VERSION 5.8 ;
BUSBITCHARS "[]" ;
DIVIDERCHAR "/" ;
UNITS
    DATABASE MICRONS 1000 ;
END UNITS

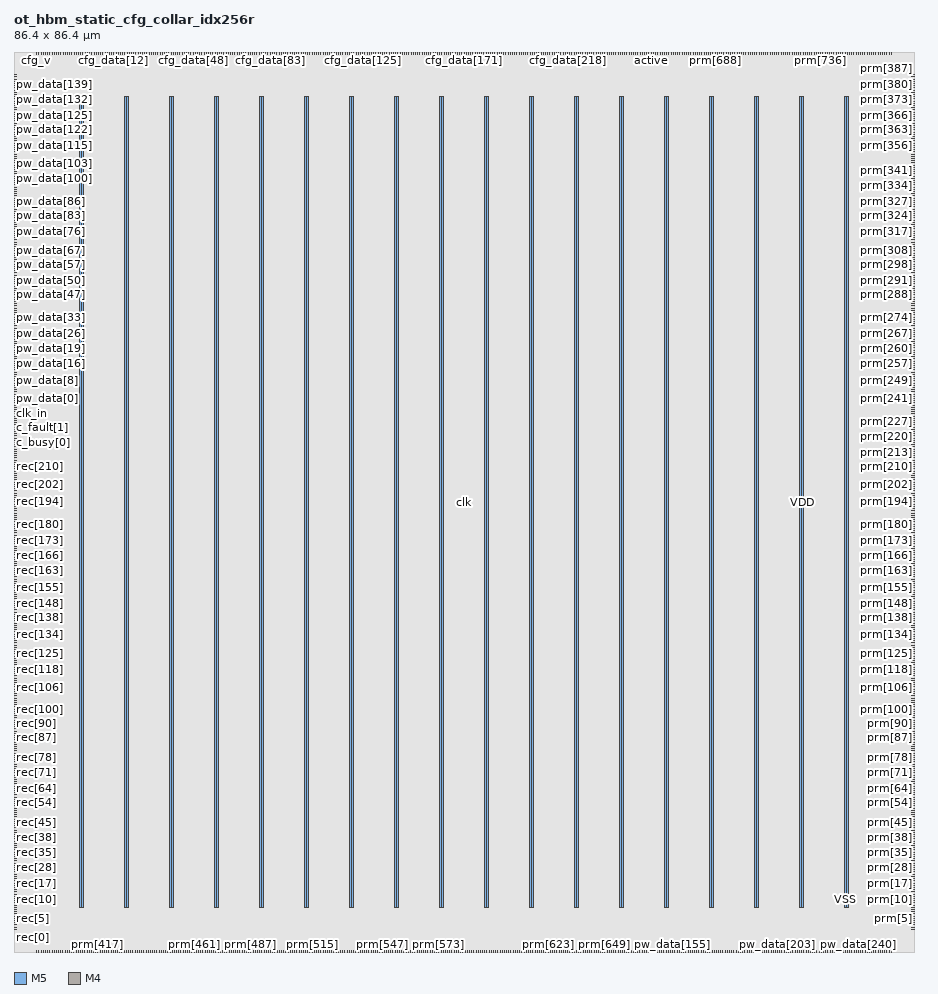
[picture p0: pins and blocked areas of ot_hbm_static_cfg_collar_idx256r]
MACRO ot_hbm_static_cfg_collar_idx256r
  FOREIGN ot_hbm_static_cfg_collar_idx256r 0 0 ;
  CLASS BLOCK ;
  SIZE 86.4 BY 86.4 ;
  PIN active
    DIRECTION OUTPUT ;
    USE SIGNAL ;
    PORT
      LAYER M5 ;
        RECT  61.164 86.208 61.188 86.4 ;
    END
  END active
  PIN c_busy[0]
    DIRECTION INPUT ;
    USE SIGNAL ;
    PORT
      LAYER M4 ;
        RECT  0 48.876 0.192 48.9 ;
    END
  END c_busy[0]
  PIN c_busy[1]
    DIRECTION INPUT ;
    USE SIGNAL ;
    PORT
      LAYER M4 ;
        RECT  0 49.116 0.192 49.14 ;
    END
  END c_busy[1]
  PIN c_done
    DIRECTION INPUT ;
    USE SIGNAL ;
    PORT
      LAYER M5 ;
        RECT  61.788 86.208 61.812 86.4 ;
    END
  END c_done
  PIN c_done__W
    DIRECTION INPUT ;
    USE SIGNAL ;
    PORT
      LAYER M4 ;
        RECT  0 52.908 0.192 52.932 ;
    END
  END c_done__W
  PIN c_fault[0]
    DIRECTION INPUT ;
    USE SIGNAL ;
    PORT
      LAYER M4 ;
        RECT  0 49.308 0.192 49.332 ;
    END
  END c_fault[0]
  PIN c_fault[1]
    DIRECTION INPUT ;
    USE SIGNAL ;
    PORT
      LAYER M4 ;
        RECT  0 49.548 0.192 49.572 ;
    END
  END c_fault[1]
  PIN c_fault[2]
    DIRECTION INPUT ;
    USE SIGNAL ;
    PORT
      LAYER M4 ;
        RECT  0 49.74 0.192 49.764 ;
    END
  END c_fault[2]
  PIN c_fault[3]
    DIRECTION INPUT ;
    USE SIGNAL ;
    PORT
      LAYER M4 ;
        RECT  0 49.932 0.192 49.956 ;
    END
  END c_fault[3]
  PIN c_fault[4]
    DIRECTION INPUT ;
    USE SIGNAL ;
    PORT
      LAYER M4 ;
        RECT  0 50.172 0.192 50.196 ;
    END
  END c_fault[4]
  PIN cfg_addr[0]
    DIRECTION INPUT ;
    USE SIGNAL ;
    PORT
      LAYER M5 ;
        RECT  4.476 86.208 4.5 86.4 ;
    END
  END cfg_addr[0]
  PIN cfg_addr[10]
    DIRECTION INPUT ;
    USE SIGNAL ;
    PORT
      LAYER M5 ;
        RECT  6.588 86.208 6.612 86.4 ;
    END
  END cfg_addr[10]
  PIN cfg_addr[11]
    DIRECTION INPUT ;
    USE SIGNAL ;
    PORT
      LAYER M5 ;
        RECT  6.828 86.208 6.852 86.4 ;
    END
  END cfg_addr[11]
  PIN cfg_addr[1]
    DIRECTION INPUT ;
    USE SIGNAL ;
    PORT
      LAYER M5 ;
        RECT  4.716 86.208 4.74 86.4 ;
    END
  END cfg_addr[1]
  PIN cfg_addr[2]
    DIRECTION INPUT ;
    USE SIGNAL ;
    PORT
      LAYER M5 ;
        RECT  4.908 86.208 4.932 86.4 ;
    END
  END cfg_addr[2]
  PIN cfg_addr[3]
    DIRECTION INPUT ;
    USE SIGNAL ;
    PORT
      LAYER M5 ;
        RECT  5.148 86.208 5.172 86.4 ;
    END
  END cfg_addr[3]
  PIN cfg_addr[4]
    DIRECTION INPUT ;
    USE SIGNAL ;
    PORT
      LAYER M5 ;
        RECT  5.34 86.208 5.364 86.4 ;
    END
  END cfg_addr[4]
  PIN cfg_addr[5]
    DIRECTION INPUT ;
    USE SIGNAL ;
    PORT
      LAYER M5 ;
        RECT  5.532 86.208 5.556 86.4 ;
    END
  END cfg_addr[5]
  PIN cfg_addr[6]
    DIRECTION INPUT ;
    USE SIGNAL ;
    PORT
      LAYER M5 ;
        RECT  5.772 86.208 5.796 86.4 ;
    END
  END cfg_addr[6]
  PIN cfg_addr[7]
    DIRECTION INPUT ;
    USE SIGNAL ;
    PORT
      LAYER M5 ;
        RECT  5.964 86.208 5.988 86.4 ;
    END
  END cfg_addr[7]
  PIN cfg_addr[8]
    DIRECTION INPUT ;
    USE SIGNAL ;
    PORT
      LAYER M5 ;
        RECT  6.204 86.208 6.228 86.4 ;
    END
  END cfg_addr[8]
  PIN cfg_addr[9]
    DIRECTION INPUT ;
    USE SIGNAL ;
    PORT
      LAYER M5 ;
        RECT  6.396 86.208 6.42 86.4 ;
    END
  END cfg_addr[9]
  PIN cfg_data[0]
    DIRECTION INPUT ;
    USE SIGNAL ;
    PORT
      LAYER M5 ;
        RECT  7.02 86.208 7.044 86.4 ;
    END
  END cfg_data[0]
  PIN cfg_data[100]
    DIRECTION INPUT ;
    USE SIGNAL ;
    PORT
      LAYER M5 ;
        RECT  28.188 86.208 28.212 86.4 ;
    END
  END cfg_data[100]
  PIN cfg_data[101]
    DIRECTION INPUT ;
    USE SIGNAL ;
    PORT
      LAYER M5 ;
        RECT  28.38 86.208 28.404 86.4 ;
    END
  END cfg_data[101]
  PIN cfg_data[102]
    DIRECTION INPUT ;
    USE SIGNAL ;
    PORT
      LAYER M5 ;
        RECT  28.62 86.208 28.644 86.4 ;
    END
  END cfg_data[102]
  PIN cfg_data[103]
    DIRECTION INPUT ;
    USE SIGNAL ;
    PORT
      LAYER M5 ;
        RECT  28.812 86.208 28.836 86.4 ;
    END
  END cfg_data[103]
  PIN cfg_data[104]
    DIRECTION INPUT ;
    USE SIGNAL ;
    PORT
      LAYER M5 ;
        RECT  29.004 86.208 29.028 86.4 ;
    END
  END cfg_data[104]
  PIN cfg_data[105]
    DIRECTION INPUT ;
    USE SIGNAL ;
    PORT
      LAYER M5 ;
        RECT  29.244 86.208 29.268 86.4 ;
    END
  END cfg_data[105]
  PIN cfg_data[106]
    DIRECTION INPUT ;
    USE SIGNAL ;
    PORT
      LAYER M5 ;
        RECT  29.436 86.208 29.46 86.4 ;
    END
  END cfg_data[106]
  PIN cfg_data[107]
    DIRECTION INPUT ;
    USE SIGNAL ;
    PORT
      LAYER M5 ;
        RECT  29.676 86.208 29.7 86.4 ;
    END
  END cfg_data[107]
  PIN cfg_data[108]
    DIRECTION INPUT ;
    USE SIGNAL ;
    PORT
      LAYER M5 ;
        RECT  29.868 86.208 29.892 86.4 ;
    END
  END cfg_data[108]
  PIN cfg_data[109]
    DIRECTION INPUT ;
    USE SIGNAL ;
    PORT
      LAYER M5 ;
        RECT  30.06 86.208 30.084 86.4 ;
    END
  END cfg_data[109]
  PIN cfg_data[10]
    DIRECTION INPUT ;
    USE SIGNAL ;
    PORT
      LAYER M5 ;
        RECT  9.132 86.208 9.156 86.4 ;
    END
  END cfg_data[10]
  PIN cfg_data[110]
    DIRECTION INPUT ;
    USE SIGNAL ;
    PORT
      LAYER M5 ;
        RECT  30.3 86.208 30.324 86.4 ;
    END
  END cfg_data[110]
  PIN cfg_data[111]
    DIRECTION INPUT ;
    USE SIGNAL ;
    PORT
      LAYER M5 ;
        RECT  30.492 86.208 30.516 86.4 ;
    END
  END cfg_data[111]
  PIN cfg_data[112]
    DIRECTION INPUT ;
    USE SIGNAL ;
    PORT
      LAYER M5 ;
        RECT  30.732 86.208 30.756 86.4 ;
    END
  END cfg_data[112]
  PIN cfg_data[113]
    DIRECTION INPUT ;
    USE SIGNAL ;
    PORT
      LAYER M5 ;
        RECT  30.924 86.208 30.948 86.4 ;
    END
  END cfg_data[113]
  PIN cfg_data[114]
    DIRECTION INPUT ;
    USE SIGNAL ;
    PORT
      LAYER M5 ;
        RECT  31.116 86.208 31.14 86.4 ;
    END
  END cfg_data[114]
  PIN cfg_data[115]
    DIRECTION INPUT ;
    USE SIGNAL ;
    PORT
      LAYER M5 ;
        RECT  31.356 86.208 31.38 86.4 ;
    END
  END cfg_data[115]
  PIN cfg_data[116]
    DIRECTION INPUT ;
    USE SIGNAL ;
    PORT
      LAYER M5 ;
        RECT  31.548 86.208 31.572 86.4 ;
    END
  END cfg_data[116]
  PIN cfg_data[117]
    DIRECTION INPUT ;
    USE SIGNAL ;
    PORT
      LAYER M5 ;
        RECT  31.788 86.208 31.812 86.4 ;
    END
  END cfg_data[117]
  PIN cfg_data[118]
    DIRECTION INPUT ;
    USE SIGNAL ;
    PORT
      LAYER M5 ;
        RECT  31.98 86.208 32.004 86.4 ;
    END
  END cfg_data[118]
  PIN cfg_data[119]
    DIRECTION INPUT ;
    USE SIGNAL ;
    PORT
      LAYER M5 ;
        RECT  32.172 86.208 32.196 86.4 ;
    END
  END cfg_data[119]
  PIN cfg_data[11]
    DIRECTION INPUT ;
    USE SIGNAL ;
    PORT
      LAYER M5 ;
        RECT  9.372 86.208 9.396 86.4 ;
    END
  END cfg_data[11]
  PIN cfg_data[120]
    DIRECTION INPUT ;
    USE SIGNAL ;
    PORT
      LAYER M5 ;
        RECT  32.412 86.208 32.436 86.4 ;
    END
  END cfg_data[120]
  PIN cfg_data[121]
    DIRECTION INPUT ;
    USE SIGNAL ;
    PORT
      LAYER M5 ;
        RECT  32.604 86.208 32.628 86.4 ;
    END
  END cfg_data[121]
  PIN cfg_data[122]
    DIRECTION INPUT ;
    USE SIGNAL ;
    PORT
      LAYER M5 ;
        RECT  32.844 86.208 32.868 86.4 ;
    END
  END cfg_data[122]
  PIN cfg_data[123]
    DIRECTION INPUT ;
    USE SIGNAL ;
    PORT
      LAYER M5 ;
        RECT  33.036 86.208 33.06 86.4 ;
    END
  END cfg_data[123]
  PIN cfg_data[124]
    DIRECTION INPUT ;
    USE SIGNAL ;
    PORT
      LAYER M5 ;
        RECT  33.228 86.208 33.252 86.4 ;
    END
  END cfg_data[124]
  PIN cfg_data[125]
    DIRECTION INPUT ;
    USE SIGNAL ;
    PORT
      LAYER M5 ;
        RECT  33.468 86.208 33.492 86.4 ;
    END
  END cfg_data[125]
  PIN cfg_data[126]
    DIRECTION INPUT ;
    USE SIGNAL ;
    PORT
      LAYER M5 ;
        RECT  33.66 86.208 33.684 86.4 ;
    END
  END cfg_data[126]
  PIN cfg_data[127]
    DIRECTION INPUT ;
    USE SIGNAL ;
    PORT
      LAYER M5 ;
        RECT  33.9 86.208 33.924 86.4 ;
    END
  END cfg_data[127]
  PIN cfg_data[128]
    DIRECTION INPUT ;
    USE SIGNAL ;
    PORT
      LAYER M5 ;
        RECT  34.092 86.208 34.116 86.4 ;
    END
  END cfg_data[128]
  PIN cfg_data[129]
    DIRECTION INPUT ;
    USE SIGNAL ;
    PORT
      LAYER M5 ;
        RECT  34.332 86.208 34.356 86.4 ;
    END
  END cfg_data[129]
  PIN cfg_data[12]
    DIRECTION INPUT ;
    USE SIGNAL ;
    PORT
      LAYER M5 ;
        RECT  9.564 86.208 9.588 86.4 ;
    END
  END cfg_data[12]
  PIN cfg_data[130]
    DIRECTION INPUT ;
    USE SIGNAL ;
    PORT
      LAYER M5 ;
        RECT  34.524 86.208 34.548 86.4 ;
    END
  END cfg_data[130]
  PIN cfg_data[131]
    DIRECTION INPUT ;
    USE SIGNAL ;
    PORT
      LAYER M5 ;
        RECT  34.716 86.208 34.74 86.4 ;
    END
  END cfg_data[131]
  PIN cfg_data[132]
    DIRECTION INPUT ;
    USE SIGNAL ;
    PORT
      LAYER M5 ;
        RECT  34.956 86.208 34.98 86.4 ;
    END
  END cfg_data[132]
  PIN cfg_data[133]
    DIRECTION INPUT ;
    USE SIGNAL ;
    PORT
      LAYER M5 ;
        RECT  35.148 86.208 35.172 86.4 ;
    END
  END cfg_data[133]
  PIN cfg_data[134]
    DIRECTION INPUT ;
    USE SIGNAL ;
    PORT
      LAYER M5 ;
        RECT  35.388 86.208 35.412 86.4 ;
    END
  END cfg_data[134]
  PIN cfg_data[135]
    DIRECTION INPUT ;
    USE SIGNAL ;
    PORT
      LAYER M5 ;
        RECT  35.58 86.208 35.604 86.4 ;
    END
  END cfg_data[135]
  PIN cfg_data[136]
    DIRECTION INPUT ;
    USE SIGNAL ;
    PORT
      LAYER M5 ;
        RECT  35.772 86.208 35.796 86.4 ;
    END
  END cfg_data[136]
  PIN cfg_data[137]
    DIRECTION INPUT ;
    USE SIGNAL ;
    PORT
      LAYER M5 ;
        RECT  36.012 86.208 36.036 86.4 ;
    END
  END cfg_data[137]
  PIN cfg_data[138]
    DIRECTION INPUT ;
    USE SIGNAL ;
    PORT
      LAYER M5 ;
        RECT  36.204 86.208 36.228 86.4 ;
    END
  END cfg_data[138]
  PIN cfg_data[139]
    DIRECTION INPUT ;
    USE SIGNAL ;
    PORT
      LAYER M5 ;
        RECT  36.444 86.208 36.468 86.4 ;
    END
  END cfg_data[139]
  PIN cfg_data[13]
    DIRECTION INPUT ;
    USE SIGNAL ;
    PORT
      LAYER M5 ;
        RECT  9.804 86.208 9.828 86.4 ;
    END
  END cfg_data[13]
  PIN cfg_data[140]
    DIRECTION INPUT ;
    USE SIGNAL ;
    PORT
      LAYER M5 ;
        RECT  36.636 86.208 36.66 86.4 ;
    END
  END cfg_data[140]
  PIN cfg_data[141]
    DIRECTION INPUT ;
    USE SIGNAL ;
    PORT
      LAYER M5 ;
        RECT  36.828 86.208 36.852 86.4 ;
    END
  END cfg_data[141]
  PIN cfg_data[142]
    DIRECTION INPUT ;
    USE SIGNAL ;
    PORT
      LAYER M5 ;
        RECT  37.068 86.208 37.092 86.4 ;
    END
  END cfg_data[142]
  PIN cfg_data[143]
    DIRECTION INPUT ;
    USE SIGNAL ;
    PORT
      LAYER M5 ;
        RECT  37.26 86.208 37.284 86.4 ;
    END
  END cfg_data[143]
  PIN cfg_data[144]
    DIRECTION INPUT ;
    USE SIGNAL ;
    PORT
      LAYER M5 ;
        RECT  37.5 86.208 37.524 86.4 ;
    END
  END cfg_data[144]
  PIN cfg_data[145]
    DIRECTION INPUT ;
    USE SIGNAL ;
    PORT
      LAYER M5 ;
        RECT  37.692 86.208 37.716 86.4 ;
    END
  END cfg_data[145]
  PIN cfg_data[146]
    DIRECTION INPUT ;
    USE SIGNAL ;
    PORT
      LAYER M5 ;
        RECT  37.884 86.208 37.908 86.4 ;
    END
  END cfg_data[146]
  PIN cfg_data[147]
    DIRECTION INPUT ;
    USE SIGNAL ;
    PORT
      LAYER M5 ;
        RECT  38.124 86.208 38.148 86.4 ;
    END
  END cfg_data[147]
  PIN cfg_data[148]
    DIRECTION INPUT ;
    USE SIGNAL ;
    PORT
      LAYER M5 ;
        RECT  38.316 86.208 38.34 86.4 ;
    END
  END cfg_data[148]
  PIN cfg_data[149]
    DIRECTION INPUT ;
    USE SIGNAL ;
    PORT
      LAYER M5 ;
        RECT  38.556 86.208 38.58 86.4 ;
    END
  END cfg_data[149]
  PIN cfg_data[14]
    DIRECTION INPUT ;
    USE SIGNAL ;
    PORT
      LAYER M5 ;
        RECT  9.996 86.208 10.02 86.4 ;
    END
  END cfg_data[14]
  PIN cfg_data[150]
    DIRECTION INPUT ;
    USE SIGNAL ;
    PORT
      LAYER M5 ;
        RECT  38.748 86.208 38.772 86.4 ;
    END
  END cfg_data[150]
  PIN cfg_data[151]
    DIRECTION INPUT ;
    USE SIGNAL ;
    PORT
      LAYER M5 ;
        RECT  38.94 86.208 38.964 86.4 ;
    END
  END cfg_data[151]
  PIN cfg_data[152]
    DIRECTION INPUT ;
    USE SIGNAL ;
    PORT
      LAYER M5 ;
        RECT  39.18 86.208 39.204 86.4 ;
    END
  END cfg_data[152]
  PIN cfg_data[153]
    DIRECTION INPUT ;
    USE SIGNAL ;
    PORT
      LAYER M5 ;
        RECT  39.372 86.208 39.396 86.4 ;
    END
  END cfg_data[153]
  PIN cfg_data[154]
    DIRECTION INPUT ;
    USE SIGNAL ;
    PORT
      LAYER M5 ;
        RECT  39.612 86.208 39.636 86.4 ;
    END
  END cfg_data[154]
  PIN cfg_data[155]
    DIRECTION INPUT ;
    USE SIGNAL ;
    PORT
      LAYER M5 ;
        RECT  39.804 86.208 39.828 86.4 ;
    END
  END cfg_data[155]
  PIN cfg_data[156]
    DIRECTION INPUT ;
    USE SIGNAL ;
    PORT
      LAYER M5 ;
        RECT  39.996 86.208 40.02 86.4 ;
    END
  END cfg_data[156]
  PIN cfg_data[157]
    DIRECTION INPUT ;
    USE SIGNAL ;
    PORT
      LAYER M5 ;
        RECT  40.236 86.208 40.26 86.4 ;
    END
  END cfg_data[157]
  PIN cfg_data[158]
    DIRECTION INPUT ;
    USE SIGNAL ;
    PORT
      LAYER M5 ;
        RECT  40.428 86.208 40.452 86.4 ;
    END
  END cfg_data[158]
  PIN cfg_data[159]
    DIRECTION INPUT ;
    USE SIGNAL ;
    PORT
      LAYER M5 ;
        RECT  40.668 86.208 40.692 86.4 ;
    END
  END cfg_data[159]
  PIN cfg_data[15]
    DIRECTION INPUT ;
    USE SIGNAL ;
    PORT
      LAYER M5 ;
        RECT  10.188 86.208 10.212 86.4 ;
    END
  END cfg_data[15]
  PIN cfg_data[160]
    DIRECTION INPUT ;
    USE SIGNAL ;
    PORT
      LAYER M5 ;
        RECT  40.86 86.208 40.884 86.4 ;
    END
  END cfg_data[160]
  PIN cfg_data[161]
    DIRECTION INPUT ;
    USE SIGNAL ;
    PORT
      LAYER M5 ;
        RECT  41.052 86.208 41.076 86.4 ;
    END
  END cfg_data[161]
  PIN cfg_data[162]
    DIRECTION INPUT ;
    USE SIGNAL ;
    PORT
      LAYER M5 ;
        RECT  41.292 86.208 41.316 86.4 ;
    END
  END cfg_data[162]
  PIN cfg_data[163]
    DIRECTION INPUT ;
    USE SIGNAL ;
    PORT
      LAYER M5 ;
        RECT  41.484 86.208 41.508 86.4 ;
    END
  END cfg_data[163]
  PIN cfg_data[164]
    DIRECTION INPUT ;
    USE SIGNAL ;
    PORT
      LAYER M5 ;
        RECT  41.724 86.208 41.748 86.4 ;
    END
  END cfg_data[164]
  PIN cfg_data[165]
    DIRECTION INPUT ;
    USE SIGNAL ;
    PORT
      LAYER M5 ;
        RECT  41.916 86.208 41.94 86.4 ;
    END
  END cfg_data[165]
  PIN cfg_data[166]
    DIRECTION INPUT ;
    USE SIGNAL ;
    PORT
      LAYER M5 ;
        RECT  42.108 86.208 42.132 86.4 ;
    END
  END cfg_data[166]
  PIN cfg_data[167]
    DIRECTION INPUT ;
    USE SIGNAL ;
    PORT
      LAYER M5 ;
        RECT  42.348 86.208 42.372 86.4 ;
    END
  END cfg_data[167]
  PIN cfg_data[168]
    DIRECTION INPUT ;
    USE SIGNAL ;
    PORT
      LAYER M5 ;
        RECT  42.54 86.208 42.564 86.4 ;
    END
  END cfg_data[168]
  PIN cfg_data[169]
    DIRECTION INPUT ;
    USE SIGNAL ;
    PORT
      LAYER M5 ;
        RECT  42.78 86.208 42.804 86.4 ;
    END
  END cfg_data[169]
  PIN cfg_data[16]
    DIRECTION INPUT ;
    USE SIGNAL ;
    PORT
      LAYER M5 ;
        RECT  10.428 86.208 10.452 86.4 ;
    END
  END cfg_data[16]
  PIN cfg_data[170]
    DIRECTION INPUT ;
    USE SIGNAL ;
    PORT
      LAYER M5 ;
        RECT  42.972 86.208 42.996 86.4 ;
    END
  END cfg_data[170]
  PIN cfg_data[171]
    DIRECTION INPUT ;
    USE SIGNAL ;
    PORT
      LAYER M5 ;
        RECT  43.212 86.208 43.236 86.4 ;
    END
  END cfg_data[171]
  PIN cfg_data[172]
    DIRECTION INPUT ;
    USE SIGNAL ;
    PORT
      LAYER M5 ;
        RECT  43.404 86.208 43.428 86.4 ;
    END
  END cfg_data[172]
  PIN cfg_data[173]
    DIRECTION INPUT ;
    USE SIGNAL ;
    PORT
      LAYER M5 ;
        RECT  43.596 86.208 43.62 86.4 ;
    END
  END cfg_data[173]
  PIN cfg_data[174]
    DIRECTION INPUT ;
    USE SIGNAL ;
    PORT
      LAYER M5 ;
        RECT  43.836 86.208 43.86 86.4 ;
    END
  END cfg_data[174]
  PIN cfg_data[175]
    DIRECTION INPUT ;
    USE SIGNAL ;
    PORT
      LAYER M5 ;
        RECT  44.028 86.208 44.052 86.4 ;
    END
  END cfg_data[175]
  PIN cfg_data[176]
    DIRECTION INPUT ;
    USE SIGNAL ;
    PORT
      LAYER M5 ;
        RECT  44.268 86.208 44.292 86.4 ;
    END
  END cfg_data[176]
  PIN cfg_data[177]
    DIRECTION INPUT ;
    USE SIGNAL ;
    PORT
      LAYER M5 ;
        RECT  44.46 86.208 44.484 86.4 ;
    END
  END cfg_data[177]
  PIN cfg_data[178]
    DIRECTION INPUT ;
    USE SIGNAL ;
    PORT
      LAYER M5 ;
        RECT  44.652 86.208 44.676 86.4 ;
    END
  END cfg_data[178]
  PIN cfg_data[179]
    DIRECTION INPUT ;
    USE SIGNAL ;
    PORT
      LAYER M5 ;
        RECT  44.892 86.208 44.916 86.4 ;
    END
  END cfg_data[179]
  PIN cfg_data[17]
    DIRECTION INPUT ;
    USE SIGNAL ;
    PORT
      LAYER M5 ;
        RECT  10.62 86.208 10.644 86.4 ;
    END
  END cfg_data[17]
  PIN cfg_data[180]
    DIRECTION INPUT ;
    USE SIGNAL ;
    PORT
      LAYER M5 ;
        RECT  45.084 86.208 45.108 86.4 ;
    END
  END cfg_data[180]
  PIN cfg_data[181]
    DIRECTION INPUT ;
    USE SIGNAL ;
    PORT
      LAYER M5 ;
        RECT  45.324 86.208 45.348 86.4 ;
    END
  END cfg_data[181]
  PIN cfg_data[182]
    DIRECTION INPUT ;
    USE SIGNAL ;
    PORT
      LAYER M5 ;
        RECT  45.516 86.208 45.54 86.4 ;
    END
  END cfg_data[182]
  PIN cfg_data[183]
    DIRECTION INPUT ;
    USE SIGNAL ;
    PORT
      LAYER M5 ;
        RECT  45.708 86.208 45.732 86.4 ;
    END
  END cfg_data[183]
  PIN cfg_data[184]
    DIRECTION INPUT ;
    USE SIGNAL ;
    PORT
      LAYER M5 ;
        RECT  45.948 86.208 45.972 86.4 ;
    END
  END cfg_data[184]
  PIN cfg_data[185]
    DIRECTION INPUT ;
    USE SIGNAL ;
    PORT
      LAYER M5 ;
        RECT  46.14 86.208 46.164 86.4 ;
    END
  END cfg_data[185]
  PIN cfg_data[186]
    DIRECTION INPUT ;
    USE SIGNAL ;
    PORT
      LAYER M5 ;
        RECT  46.38 86.208 46.404 86.4 ;
    END
  END cfg_data[186]
  PIN cfg_data[187]
    DIRECTION INPUT ;
    USE SIGNAL ;
    PORT
      LAYER M5 ;
        RECT  46.572 86.208 46.596 86.4 ;
    END
  END cfg_data[187]
  PIN cfg_data[188]
    DIRECTION INPUT ;
    USE SIGNAL ;
    PORT
      LAYER M5 ;
        RECT  46.764 86.208 46.788 86.4 ;
    END
  END cfg_data[188]
  PIN cfg_data[189]
    DIRECTION INPUT ;
    USE SIGNAL ;
    PORT
      LAYER M5 ;
        RECT  47.004 86.208 47.028 86.4 ;
    END
  END cfg_data[189]
  PIN cfg_data[18]
    DIRECTION INPUT ;
    USE SIGNAL ;
    PORT
      LAYER M5 ;
        RECT  10.86 86.208 10.884 86.4 ;
    END
  END cfg_data[18]
  PIN cfg_data[190]
    DIRECTION INPUT ;
    USE SIGNAL ;
    PORT
      LAYER M5 ;
        RECT  47.196 86.208 47.22 86.4 ;
    END
  END cfg_data[190]
  PIN cfg_data[191]
    DIRECTION INPUT ;
    USE SIGNAL ;
    PORT
      LAYER M5 ;
        RECT  47.436 86.208 47.46 86.4 ;
    END
  END cfg_data[191]
  PIN cfg_data[192]
    DIRECTION INPUT ;
    USE SIGNAL ;
    PORT
      LAYER M5 ;
        RECT  47.628 86.208 47.652 86.4 ;
    END
  END cfg_data[192]
  PIN cfg_data[193]
    DIRECTION INPUT ;
    USE SIGNAL ;
    PORT
      LAYER M5 ;
        RECT  47.82 86.208 47.844 86.4 ;
    END
  END cfg_data[193]
  PIN cfg_data[194]
    DIRECTION INPUT ;
    USE SIGNAL ;
    PORT
      LAYER M5 ;
        RECT  48.06 86.208 48.084 86.4 ;
    END
  END cfg_data[194]
  PIN cfg_data[195]
    DIRECTION INPUT ;
    USE SIGNAL ;
    PORT
      LAYER M5 ;
        RECT  48.252 86.208 48.276 86.4 ;
    END
  END cfg_data[195]
  PIN cfg_data[196]
    DIRECTION INPUT ;
    USE SIGNAL ;
    PORT
      LAYER M5 ;
        RECT  48.492 86.208 48.516 86.4 ;
    END
  END cfg_data[196]
  PIN cfg_data[197]
    DIRECTION INPUT ;
    USE SIGNAL ;
    PORT
      LAYER M5 ;
        RECT  48.684 86.208 48.708 86.4 ;
    END
  END cfg_data[197]
  PIN cfg_data[198]
    DIRECTION INPUT ;
    USE SIGNAL ;
    PORT
      LAYER M5 ;
        RECT  48.876 86.208 48.9 86.4 ;
    END
  END cfg_data[198]
  PIN cfg_data[199]
    DIRECTION INPUT ;
    USE SIGNAL ;
    PORT
      LAYER M5 ;
        RECT  49.116 86.208 49.14 86.4 ;
    END
  END cfg_data[199]
  PIN cfg_data[19]
    DIRECTION INPUT ;
    USE SIGNAL ;
    PORT
      LAYER M5 ;
        RECT  11.052 86.208 11.076 86.4 ;
    END
  END cfg_data[19]
  PIN cfg_data[1]
    DIRECTION INPUT ;
    USE SIGNAL ;
    PORT
      LAYER M5 ;
        RECT  7.26 86.208 7.284 86.4 ;
    END
  END cfg_data[1]
  PIN cfg_data[200]
    DIRECTION INPUT ;
    USE SIGNAL ;
    PORT
      LAYER M5 ;
        RECT  49.308 86.208 49.332 86.4 ;
    END
  END cfg_data[200]
  PIN cfg_data[201]
    DIRECTION INPUT ;
    USE SIGNAL ;
    PORT
      LAYER M5 ;
        RECT  49.548 86.208 49.572 86.4 ;
    END
  END cfg_data[201]
  PIN cfg_data[202]
    DIRECTION INPUT ;
    USE SIGNAL ;
    PORT
      LAYER M5 ;
        RECT  49.74 86.208 49.764 86.4 ;
    END
  END cfg_data[202]
  PIN cfg_data[203]
    DIRECTION INPUT ;
    USE SIGNAL ;
    PORT
      LAYER M5 ;
        RECT  49.932 86.208 49.956 86.4 ;
    END
  END cfg_data[203]
  PIN cfg_data[204]
    DIRECTION INPUT ;
    USE SIGNAL ;
    PORT
      LAYER M5 ;
        RECT  50.172 86.208 50.196 86.4 ;
    END
  END cfg_data[204]
  PIN cfg_data[205]
    DIRECTION INPUT ;
    USE SIGNAL ;
    PORT
      LAYER M5 ;
        RECT  50.364 86.208 50.388 86.4 ;
    END
  END cfg_data[205]
  PIN cfg_data[206]
    DIRECTION INPUT ;
    USE SIGNAL ;
    PORT
      LAYER M5 ;
        RECT  50.604 86.208 50.628 86.4 ;
    END
  END cfg_data[206]
  PIN cfg_data[207]
    DIRECTION INPUT ;
    USE SIGNAL ;
    PORT
      LAYER M5 ;
        RECT  50.796 86.208 50.82 86.4 ;
    END
  END cfg_data[207]
  PIN cfg_data[208]
    DIRECTION INPUT ;
    USE SIGNAL ;
    PORT
      LAYER M5 ;
        RECT  50.988 86.208 51.012 86.4 ;
    END
  END cfg_data[208]
  PIN cfg_data[209]
    DIRECTION INPUT ;
    USE SIGNAL ;
    PORT
      LAYER M5 ;
        RECT  51.228 86.208 51.252 86.4 ;
    END
  END cfg_data[209]
  PIN cfg_data[20]
    DIRECTION INPUT ;
    USE SIGNAL ;
    PORT
      LAYER M5 ;
        RECT  11.244 86.208 11.268 86.4 ;
    END
  END cfg_data[20]
  PIN cfg_data[210]
    DIRECTION INPUT ;
    USE SIGNAL ;
    PORT
      LAYER M5 ;
        RECT  51.42 86.208 51.444 86.4 ;
    END
  END cfg_data[210]
  PIN cfg_data[211]
    DIRECTION INPUT ;
    USE SIGNAL ;
    PORT
      LAYER M5 ;
        RECT  51.66 86.208 51.684 86.4 ;
    END
  END cfg_data[211]
  PIN cfg_data[212]
    DIRECTION INPUT ;
    USE SIGNAL ;
    PORT
      LAYER M5 ;
        RECT  51.852 86.208 51.876 86.4 ;
    END
  END cfg_data[212]
  PIN cfg_data[213]
    DIRECTION INPUT ;
    USE SIGNAL ;
    PORT
      LAYER M5 ;
        RECT  52.044 86.208 52.068 86.4 ;
    END
  END cfg_data[213]
  PIN cfg_data[214]
    DIRECTION INPUT ;
    USE SIGNAL ;
    PORT
      LAYER M5 ;
        RECT  52.284 86.208 52.308 86.4 ;
    END
  END cfg_data[214]
  PIN cfg_data[215]
    DIRECTION INPUT ;
    USE SIGNAL ;
    PORT
      LAYER M5 ;
        RECT  52.476 86.208 52.5 86.4 ;
    END
  END cfg_data[215]
  PIN cfg_data[216]
    DIRECTION INPUT ;
    USE SIGNAL ;
    PORT
      LAYER M5 ;
        RECT  52.716 86.208 52.74 86.4 ;
    END
  END cfg_data[216]
  PIN cfg_data[217]
    DIRECTION INPUT ;
    USE SIGNAL ;
    PORT
      LAYER M5 ;
        RECT  52.908 86.208 52.932 86.4 ;
    END
  END cfg_data[217]
  PIN cfg_data[218]
    DIRECTION INPUT ;
    USE SIGNAL ;
    PORT
      LAYER M5 ;
        RECT  53.148 86.208 53.172 86.4 ;
    END
  END cfg_data[218]
  PIN cfg_data[219]
    DIRECTION INPUT ;
    USE SIGNAL ;
    PORT
      LAYER M5 ;
        RECT  53.34 86.208 53.364 86.4 ;
    END
  END cfg_data[219]
  PIN cfg_data[21]
    DIRECTION INPUT ;
    USE SIGNAL ;
    PORT
      LAYER M5 ;
        RECT  11.484 86.208 11.508 86.4 ;
    END
  END cfg_data[21]
  PIN cfg_data[220]
    DIRECTION INPUT ;
    USE SIGNAL ;
    PORT
      LAYER M5 ;
        RECT  53.532 86.208 53.556 86.4 ;
    END
  END cfg_data[220]
  PIN cfg_data[221]
    DIRECTION INPUT ;
    USE SIGNAL ;
    PORT
      LAYER M5 ;
        RECT  53.772 86.208 53.796 86.4 ;
    END
  END cfg_data[221]
  PIN cfg_data[222]
    DIRECTION INPUT ;
    USE SIGNAL ;
    PORT
      LAYER M5 ;
        RECT  53.964 86.208 53.988 86.4 ;
    END
  END cfg_data[222]
  PIN cfg_data[223]
    DIRECTION INPUT ;
    USE SIGNAL ;
    PORT
      LAYER M5 ;
        RECT  54.204 86.208 54.228 86.4 ;
    END
  END cfg_data[223]
  PIN cfg_data[224]
    DIRECTION INPUT ;
    USE SIGNAL ;
    PORT
      LAYER M5 ;
        RECT  54.396 86.208 54.42 86.4 ;
    END
  END cfg_data[224]
  PIN cfg_data[225]
    DIRECTION INPUT ;
    USE SIGNAL ;
    PORT
      LAYER M5 ;
        RECT  54.588 86.208 54.612 86.4 ;
    END
  END cfg_data[225]
  PIN cfg_data[226]
    DIRECTION INPUT ;
    USE SIGNAL ;
    PORT
      LAYER M5 ;
        RECT  54.828 86.208 54.852 86.4 ;
    END
  END cfg_data[226]
  PIN cfg_data[227]
    DIRECTION INPUT ;
    USE SIGNAL ;
    PORT
      LAYER M5 ;
        RECT  55.02 86.208 55.044 86.4 ;
    END
  END cfg_data[227]
  PIN cfg_data[228]
    DIRECTION INPUT ;
    USE SIGNAL ;
    PORT
      LAYER M5 ;
        RECT  55.26 86.208 55.284 86.4 ;
    END
  END cfg_data[228]
  PIN cfg_data[229]
    DIRECTION INPUT ;
    USE SIGNAL ;
    PORT
      LAYER M5 ;
        RECT  55.452 86.208 55.476 86.4 ;
    END
  END cfg_data[229]
  PIN cfg_data[22]
    DIRECTION INPUT ;
    USE SIGNAL ;
    PORT
      LAYER M5 ;
        RECT  11.676 86.208 11.7 86.4 ;
    END
  END cfg_data[22]
  PIN cfg_data[230]
    DIRECTION INPUT ;
    USE SIGNAL ;
    PORT
      LAYER M5 ;
        RECT  55.644 86.208 55.668 86.4 ;
    END
  END cfg_data[230]
  PIN cfg_data[231]
    DIRECTION INPUT ;
    USE SIGNAL ;
    PORT
      LAYER M5 ;
        RECT  55.884 86.208 55.908 86.4 ;
    END
  END cfg_data[231]
  PIN cfg_data[232]
    DIRECTION INPUT ;
    USE SIGNAL ;
    PORT
      LAYER M5 ;
        RECT  56.076 86.208 56.1 86.4 ;
    END
  END cfg_data[232]
  PIN cfg_data[233]
    DIRECTION INPUT ;
    USE SIGNAL ;
    PORT
      LAYER M5 ;
        RECT  56.316 86.208 56.34 86.4 ;
    END
  END cfg_data[233]
  PIN cfg_data[234]
    DIRECTION INPUT ;
    USE SIGNAL ;
    PORT
      LAYER M5 ;
        RECT  56.508 86.208 56.532 86.4 ;
    END
  END cfg_data[234]
  PIN cfg_data[235]
    DIRECTION INPUT ;
    USE SIGNAL ;
    PORT
      LAYER M5 ;
        RECT  56.7 86.208 56.724 86.4 ;
    END
  END cfg_data[235]
  PIN cfg_data[236]
    DIRECTION INPUT ;
    USE SIGNAL ;
    PORT
      LAYER M5 ;
        RECT  56.94 86.208 56.964 86.4 ;
    END
  END cfg_data[236]
  PIN cfg_data[237]
    DIRECTION INPUT ;
    USE SIGNAL ;
    PORT
      LAYER M5 ;
        RECT  57.132 86.208 57.156 86.4 ;
    END
  END cfg_data[237]
  PIN cfg_data[238]
    DIRECTION INPUT ;
    USE SIGNAL ;
    PORT
      LAYER M5 ;
        RECT  57.372 86.208 57.396 86.4 ;
    END
  END cfg_data[238]
  PIN cfg_data[239]
    DIRECTION INPUT ;
    USE SIGNAL ;
    PORT
      LAYER M5 ;
        RECT  57.564 86.208 57.588 86.4 ;
    END
  END cfg_data[239]
  PIN cfg_data[23]
    DIRECTION INPUT ;
    USE SIGNAL ;
    PORT
      LAYER M5 ;
        RECT  11.916 86.208 11.94 86.4 ;
    END
  END cfg_data[23]
  PIN cfg_data[240]
    DIRECTION INPUT ;
    USE SIGNAL ;
    PORT
      LAYER M5 ;
        RECT  57.756 86.208 57.78 86.4 ;
    END
  END cfg_data[240]
  PIN cfg_data[241]
    DIRECTION INPUT ;
    USE SIGNAL ;
    PORT
      LAYER M5 ;
        RECT  57.996 86.208 58.02 86.4 ;
    END
  END cfg_data[241]
  PIN cfg_data[242]
    DIRECTION INPUT ;
    USE SIGNAL ;
    PORT
      LAYER M5 ;
        RECT  58.188 86.208 58.212 86.4 ;
    END
  END cfg_data[242]
  PIN cfg_data[243]
    DIRECTION INPUT ;
    USE SIGNAL ;
    PORT
      LAYER M5 ;
        RECT  58.428 86.208 58.452 86.4 ;
    END
  END cfg_data[243]
  PIN cfg_data[244]
    DIRECTION INPUT ;
    USE SIGNAL ;
    PORT
      LAYER M5 ;
        RECT  58.62 86.208 58.644 86.4 ;
    END
  END cfg_data[244]
  PIN cfg_data[245]
    DIRECTION INPUT ;
    USE SIGNAL ;
    PORT
      LAYER M5 ;
        RECT  58.812 86.208 58.836 86.4 ;
    END
  END cfg_data[245]
  PIN cfg_data[246]
    DIRECTION INPUT ;
    USE SIGNAL ;
    PORT
      LAYER M5 ;
        RECT  59.052 86.208 59.076 86.4 ;
    END
  END cfg_data[246]
  PIN cfg_data[247]
    DIRECTION INPUT ;
    USE SIGNAL ;
    PORT
      LAYER M5 ;
        RECT  59.244 86.208 59.268 86.4 ;
    END
  END cfg_data[247]
  PIN cfg_data[248]
    DIRECTION INPUT ;
    USE SIGNAL ;
    PORT
      LAYER M5 ;
        RECT  59.484 86.208 59.508 86.4 ;
    END
  END cfg_data[248]
  PIN cfg_data[249]
    DIRECTION INPUT ;
    USE SIGNAL ;
    PORT
      LAYER M5 ;
        RECT  59.676 86.208 59.7 86.4 ;
    END
  END cfg_data[249]
  PIN cfg_data[24]
    DIRECTION INPUT ;
    USE SIGNAL ;
    PORT
      LAYER M5 ;
        RECT  12.108 86.208 12.132 86.4 ;
    END
  END cfg_data[24]
  PIN cfg_data[250]
    DIRECTION INPUT ;
    USE SIGNAL ;
    PORT
      LAYER M5 ;
        RECT  59.868 86.208 59.892 86.4 ;
    END
  END cfg_data[250]
  PIN cfg_data[251]
    DIRECTION INPUT ;
    USE SIGNAL ;
    PORT
      LAYER M5 ;
        RECT  60.108 86.208 60.132 86.4 ;
    END
  END cfg_data[251]
  PIN cfg_data[252]
    DIRECTION INPUT ;
    USE SIGNAL ;
    PORT
      LAYER M5 ;
        RECT  60.3 86.208 60.324 86.4 ;
    END
  END cfg_data[252]
  PIN cfg_data[253]
    DIRECTION INPUT ;
    USE SIGNAL ;
    PORT
      LAYER M5 ;
        RECT  60.54 86.208 60.564 86.4 ;
    END
  END cfg_data[253]
  PIN cfg_data[254]
    DIRECTION INPUT ;
    USE SIGNAL ;
    PORT
      LAYER M5 ;
        RECT  60.732 86.208 60.756 86.4 ;
    END
  END cfg_data[254]
  PIN cfg_data[255]
    DIRECTION INPUT ;
    USE SIGNAL ;
    PORT
      LAYER M5 ;
        RECT  60.924 86.208 60.948 86.4 ;
    END
  END cfg_data[255]
  PIN cfg_data[25]
    DIRECTION INPUT ;
    USE SIGNAL ;
    PORT
      LAYER M5 ;
        RECT  12.3 86.208 12.324 86.4 ;
    END
  END cfg_data[25]
  PIN cfg_data[26]
    DIRECTION INPUT ;
    USE SIGNAL ;
    PORT
      LAYER M5 ;
        RECT  12.54 86.208 12.564 86.4 ;
    END
  END cfg_data[26]
  PIN cfg_data[27]
    DIRECTION INPUT ;
    USE SIGNAL ;
    PORT
      LAYER M5 ;
        RECT  12.732 86.208 12.756 86.4 ;
    END
  END cfg_data[27]
  PIN cfg_data[28]
    DIRECTION INPUT ;
    USE SIGNAL ;
    PORT
      LAYER M5 ;
        RECT  12.972 86.208 12.996 86.4 ;
    END
  END cfg_data[28]
  PIN cfg_data[29]
    DIRECTION INPUT ;
    USE SIGNAL ;
    PORT
      LAYER M5 ;
        RECT  13.164 86.208 13.188 86.4 ;
    END
  END cfg_data[29]
  PIN cfg_data[2]
    DIRECTION INPUT ;
    USE SIGNAL ;
    PORT
      LAYER M5 ;
        RECT  7.452 86.208 7.476 86.4 ;
    END
  END cfg_data[2]
  PIN cfg_data[30]
    DIRECTION INPUT ;
    USE SIGNAL ;
    PORT
      LAYER M5 ;
        RECT  13.356 86.208 13.38 86.4 ;
    END
  END cfg_data[30]
  PIN cfg_data[31]
    DIRECTION INPUT ;
    USE SIGNAL ;
    PORT
      LAYER M5 ;
        RECT  13.596 86.208 13.62 86.4 ;
    END
  END cfg_data[31]
  PIN cfg_data[32]
    DIRECTION INPUT ;
    USE SIGNAL ;
    PORT
      LAYER M5 ;
        RECT  13.788 86.208 13.812 86.4 ;
    END
  END cfg_data[32]
  PIN cfg_data[33]
    DIRECTION INPUT ;
    USE SIGNAL ;
    PORT
      LAYER M5 ;
        RECT  14.028 86.208 14.052 86.4 ;
    END
  END cfg_data[33]
  PIN cfg_data[34]
    DIRECTION INPUT ;
    USE SIGNAL ;
    PORT
      LAYER M5 ;
        RECT  14.22 86.208 14.244 86.4 ;
    END
  END cfg_data[34]
  PIN cfg_data[35]
    DIRECTION INPUT ;
    USE SIGNAL ;
    PORT
      LAYER M5 ;
        RECT  14.412 86.208 14.436 86.4 ;
    END
  END cfg_data[35]
  PIN cfg_data[36]
    DIRECTION INPUT ;
    USE SIGNAL ;
    PORT
      LAYER M5 ;
        RECT  14.652 86.208 14.676 86.4 ;
    END
  END cfg_data[36]
  PIN cfg_data[37]
    DIRECTION INPUT ;
    USE SIGNAL ;
    PORT
      LAYER M5 ;
        RECT  14.844 86.208 14.868 86.4 ;
    END
  END cfg_data[37]
  PIN cfg_data[38]
    DIRECTION INPUT ;
    USE SIGNAL ;
    PORT
      LAYER M5 ;
        RECT  15.084 86.208 15.108 86.4 ;
    END
  END cfg_data[38]
  PIN cfg_data[39]
    DIRECTION INPUT ;
    USE SIGNAL ;
    PORT
      LAYER M5 ;
        RECT  15.276 86.208 15.3 86.4 ;
    END
  END cfg_data[39]
  PIN cfg_data[3]
    DIRECTION INPUT ;
    USE SIGNAL ;
    PORT
      LAYER M5 ;
        RECT  7.692 86.208 7.716 86.4 ;
    END
  END cfg_data[3]
  PIN cfg_data[40]
    DIRECTION INPUT ;
    USE SIGNAL ;
    PORT
      LAYER M5 ;
        RECT  15.468 86.208 15.492 86.4 ;
    END
  END cfg_data[40]
  PIN cfg_data[41]
    DIRECTION INPUT ;
    USE SIGNAL ;
    PORT
      LAYER M5 ;
        RECT  15.708 86.208 15.732 86.4 ;
    END
  END cfg_data[41]
  PIN cfg_data[42]
    DIRECTION INPUT ;
    USE SIGNAL ;
    PORT
      LAYER M5 ;
        RECT  15.9 86.208 15.924 86.4 ;
    END
  END cfg_data[42]
  PIN cfg_data[43]
    DIRECTION INPUT ;
    USE SIGNAL ;
    PORT
      LAYER M5 ;
        RECT  16.14 86.208 16.164 86.4 ;
    END
  END cfg_data[43]
  PIN cfg_data[44]
    DIRECTION INPUT ;
    USE SIGNAL ;
    PORT
      LAYER M5 ;
        RECT  16.332 86.208 16.356 86.4 ;
    END
  END cfg_data[44]
  PIN cfg_data[45]
    DIRECTION INPUT ;
    USE SIGNAL ;
    PORT
      LAYER M5 ;
        RECT  16.572 86.208 16.596 86.4 ;
    END
  END cfg_data[45]
  PIN cfg_data[46]
    DIRECTION INPUT ;
    USE SIGNAL ;
    PORT
      LAYER M5 ;
        RECT  16.764 86.208 16.788 86.4 ;
    END
  END cfg_data[46]
  PIN cfg_data[47]
    DIRECTION INPUT ;
    USE SIGNAL ;
    PORT
      LAYER M5 ;
        RECT  16.956 86.208 16.98 86.4 ;
    END
  END cfg_data[47]
  PIN cfg_data[48]
    DIRECTION INPUT ;
    USE SIGNAL ;
    PORT
      LAYER M5 ;
        RECT  17.196 86.208 17.22 86.4 ;
    END
  END cfg_data[48]
  PIN cfg_data[49]
    DIRECTION INPUT ;
    USE SIGNAL ;
    PORT
      LAYER M5 ;
        RECT  17.388 86.208 17.412 86.4 ;
    END
  END cfg_data[49]
  PIN cfg_data[4]
    DIRECTION INPUT ;
    USE SIGNAL ;
    PORT
      LAYER M5 ;
        RECT  7.884 86.208 7.908 86.4 ;
    END
  END cfg_data[4]
  PIN cfg_data[50]
    DIRECTION INPUT ;
    USE SIGNAL ;
    PORT
      LAYER M5 ;
        RECT  17.628 86.208 17.652 86.4 ;
    END
  END cfg_data[50]
  PIN cfg_data[51]
    DIRECTION INPUT ;
    USE SIGNAL ;
    PORT
      LAYER M5 ;
        RECT  17.82 86.208 17.844 86.4 ;
    END
  END cfg_data[51]
  PIN cfg_data[52]
    DIRECTION INPUT ;
    USE SIGNAL ;
    PORT
      LAYER M5 ;
        RECT  18.012 86.208 18.036 86.4 ;
    END
  END cfg_data[52]
  PIN cfg_data[53]
    DIRECTION INPUT ;
    USE SIGNAL ;
    PORT
      LAYER M5 ;
        RECT  18.252 86.208 18.276 86.4 ;
    END
  END cfg_data[53]
  PIN cfg_data[54]
    DIRECTION INPUT ;
    USE SIGNAL ;
    PORT
      LAYER M5 ;
        RECT  18.444 86.208 18.468 86.4 ;
    END
  END cfg_data[54]
  PIN cfg_data[55]
    DIRECTION INPUT ;
    USE SIGNAL ;
    PORT
      LAYER M5 ;
        RECT  18.684 86.208 18.708 86.4 ;
    END
  END cfg_data[55]
  PIN cfg_data[56]
    DIRECTION INPUT ;
    USE SIGNAL ;
    PORT
      LAYER M5 ;
        RECT  18.876 86.208 18.9 86.4 ;
    END
  END cfg_data[56]
  PIN cfg_data[57]
    DIRECTION INPUT ;
    USE SIGNAL ;
    PORT
      LAYER M5 ;
        RECT  19.068 86.208 19.092 86.4 ;
    END
  END cfg_data[57]
  PIN cfg_data[58]
    DIRECTION INPUT ;
    USE SIGNAL ;
    PORT
      LAYER M5 ;
        RECT  19.308 86.208 19.332 86.4 ;
    END
  END cfg_data[58]
  PIN cfg_data[59]
    DIRECTION INPUT ;
    USE SIGNAL ;
    PORT
      LAYER M5 ;
        RECT  19.5 86.208 19.524 86.4 ;
    END
  END cfg_data[59]
  PIN cfg_data[5]
    DIRECTION INPUT ;
    USE SIGNAL ;
    PORT
      LAYER M5 ;
        RECT  8.076 86.208 8.1 86.4 ;
    END
  END cfg_data[5]
  PIN cfg_data[60]
    DIRECTION INPUT ;
    USE SIGNAL ;
    PORT
      LAYER M5 ;
        RECT  19.74 86.208 19.764 86.4 ;
    END
  END cfg_data[60]
  PIN cfg_data[61]
    DIRECTION INPUT ;
    USE SIGNAL ;
    PORT
      LAYER M5 ;
        RECT  19.932 86.208 19.956 86.4 ;
    END
  END cfg_data[61]
  PIN cfg_data[62]
    DIRECTION INPUT ;
    USE SIGNAL ;
    PORT
      LAYER M5 ;
        RECT  20.124 86.208 20.148 86.4 ;
    END
  END cfg_data[62]
  PIN cfg_data[63]
    DIRECTION INPUT ;
    USE SIGNAL ;
    PORT
      LAYER M5 ;
        RECT  20.364 86.208 20.388 86.4 ;
    END
  END cfg_data[63]
  PIN cfg_data[64]
    DIRECTION INPUT ;
    USE SIGNAL ;
    PORT
      LAYER M5 ;
        RECT  20.556 86.208 20.58 86.4 ;
    END
  END cfg_data[64]
  PIN cfg_data[65]
    DIRECTION INPUT ;
    USE SIGNAL ;
    PORT
      LAYER M5 ;
        RECT  20.796 86.208 20.82 86.4 ;
    END
  END cfg_data[65]
  PIN cfg_data[66]
    DIRECTION INPUT ;
    USE SIGNAL ;
    PORT
      LAYER M5 ;
        RECT  20.988 86.208 21.012 86.4 ;
    END
  END cfg_data[66]
  PIN cfg_data[67]
    DIRECTION INPUT ;
    USE SIGNAL ;
    PORT
      LAYER M5 ;
        RECT  21.18 86.208 21.204 86.4 ;
    END
  END cfg_data[67]
  PIN cfg_data[68]
    DIRECTION INPUT ;
    USE SIGNAL ;
    PORT
      LAYER M5 ;
        RECT  21.42 86.208 21.444 86.4 ;
    END
  END cfg_data[68]
  PIN cfg_data[69]
    DIRECTION INPUT ;
    USE SIGNAL ;
    PORT
      LAYER M5 ;
        RECT  21.612 86.208 21.636 86.4 ;
    END
  END cfg_data[69]
  PIN cfg_data[6]
    DIRECTION INPUT ;
    USE SIGNAL ;
    PORT
      LAYER M5 ;
        RECT  8.316 86.208 8.34 86.4 ;
    END
  END cfg_data[6]
  PIN cfg_data[70]
    DIRECTION INPUT ;
    USE SIGNAL ;
    PORT
      LAYER M5 ;
        RECT  21.852 86.208 21.876 86.4 ;
    END
  END cfg_data[70]
  PIN cfg_data[71]
    DIRECTION INPUT ;
    USE SIGNAL ;
    PORT
      LAYER M5 ;
        RECT  22.044 86.208 22.068 86.4 ;
    END
  END cfg_data[71]
  PIN cfg_data[72]
    DIRECTION INPUT ;
    USE SIGNAL ;
    PORT
      LAYER M5 ;
        RECT  22.236 86.208 22.26 86.4 ;
    END
  END cfg_data[72]
  PIN cfg_data[73]
    DIRECTION INPUT ;
    USE SIGNAL ;
    PORT
      LAYER M5 ;
        RECT  22.476 86.208 22.5 86.4 ;
    END
  END cfg_data[73]
  PIN cfg_data[74]
    DIRECTION INPUT ;
    USE SIGNAL ;
    PORT
      LAYER M5 ;
        RECT  22.668 86.208 22.692 86.4 ;
    END
  END cfg_data[74]
  PIN cfg_data[75]
    DIRECTION INPUT ;
    USE SIGNAL ;
    PORT
      LAYER M5 ;
        RECT  22.908 86.208 22.932 86.4 ;
    END
  END cfg_data[75]
  PIN cfg_data[76]
    DIRECTION INPUT ;
    USE SIGNAL ;
    PORT
      LAYER M5 ;
        RECT  23.1 86.208 23.124 86.4 ;
    END
  END cfg_data[76]
  PIN cfg_data[77]
    DIRECTION INPUT ;
    USE SIGNAL ;
    PORT
      LAYER M5 ;
        RECT  23.292 86.208 23.316 86.4 ;
    END
  END cfg_data[77]
  PIN cfg_data[78]
    DIRECTION INPUT ;
    USE SIGNAL ;
    PORT
      LAYER M5 ;
        RECT  23.532 86.208 23.556 86.4 ;
    END
  END cfg_data[78]
  PIN cfg_data[79]
    DIRECTION INPUT ;
    USE SIGNAL ;
    PORT
      LAYER M5 ;
        RECT  23.724 86.208 23.748 86.4 ;
    END
  END cfg_data[79]
  PIN cfg_data[7]
    DIRECTION INPUT ;
    USE SIGNAL ;
    PORT
      LAYER M5 ;
        RECT  8.508 86.208 8.532 86.4 ;
    END
  END cfg_data[7]
  PIN cfg_data[80]
    DIRECTION INPUT ;
    USE SIGNAL ;
    PORT
      LAYER M5 ;
        RECT  23.964 86.208 23.988 86.4 ;
    END
  END cfg_data[80]
  PIN cfg_data[81]
    DIRECTION INPUT ;
    USE SIGNAL ;
    PORT
      LAYER M5 ;
        RECT  24.156 86.208 24.18 86.4 ;
    END
  END cfg_data[81]
  PIN cfg_data[82]
    DIRECTION INPUT ;
    USE SIGNAL ;
    PORT
      LAYER M5 ;
        RECT  24.348 86.208 24.372 86.4 ;
    END
  END cfg_data[82]
  PIN cfg_data[83]
    DIRECTION INPUT ;
    USE SIGNAL ;
    PORT
      LAYER M5 ;
        RECT  24.588 86.208 24.612 86.4 ;
    END
  END cfg_data[83]
  PIN cfg_data[84]
    DIRECTION INPUT ;
    USE SIGNAL ;
    PORT
      LAYER M5 ;
        RECT  24.78 86.208 24.804 86.4 ;
    END
  END cfg_data[84]
  PIN cfg_data[85]
    DIRECTION INPUT ;
    USE SIGNAL ;
    PORT
      LAYER M5 ;
        RECT  25.02 86.208 25.044 86.4 ;
    END
  END cfg_data[85]
  PIN cfg_data[86]
    DIRECTION INPUT ;
    USE SIGNAL ;
    PORT
      LAYER M5 ;
        RECT  25.212 86.208 25.236 86.4 ;
    END
  END cfg_data[86]
  PIN cfg_data[87]
    DIRECTION INPUT ;
    USE SIGNAL ;
    PORT
      LAYER M5 ;
        RECT  25.452 86.208 25.476 86.4 ;
    END
  END cfg_data[87]
  PIN cfg_data[88]
    DIRECTION INPUT ;
    USE SIGNAL ;
    PORT
      LAYER M5 ;
        RECT  25.644 86.208 25.668 86.4 ;
    END
  END cfg_data[88]
  PIN cfg_data[89]
    DIRECTION INPUT ;
    USE SIGNAL ;
    PORT
      LAYER M5 ;
        RECT  25.836 86.208 25.86 86.4 ;
    END
  END cfg_data[89]
  PIN cfg_data[8]
    DIRECTION INPUT ;
    USE SIGNAL ;
    PORT
      LAYER M5 ;
        RECT  8.748 86.208 8.772 86.4 ;
    END
  END cfg_data[8]
  PIN cfg_data[90]
    DIRECTION INPUT ;
    USE SIGNAL ;
    PORT
      LAYER M5 ;
        RECT  26.076 86.208 26.1 86.4 ;
    END
  END cfg_data[90]
  PIN cfg_data[91]
    DIRECTION INPUT ;
    USE SIGNAL ;
    PORT
      LAYER M5 ;
        RECT  26.268 86.208 26.292 86.4 ;
    END
  END cfg_data[91]
  PIN cfg_data[92]
    DIRECTION INPUT ;
    USE SIGNAL ;
    PORT
      LAYER M5 ;
        RECT  26.508 86.208 26.532 86.4 ;
    END
  END cfg_data[92]
  PIN cfg_data[93]
    DIRECTION INPUT ;
    USE SIGNAL ;
    PORT
      LAYER M5 ;
        RECT  26.7 86.208 26.724 86.4 ;
    END
  END cfg_data[93]
  PIN cfg_data[94]
    DIRECTION INPUT ;
    USE SIGNAL ;
    PORT
      LAYER M5 ;
        RECT  26.892 86.208 26.916 86.4 ;
    END
  END cfg_data[94]
  PIN cfg_data[95]
    DIRECTION INPUT ;
    USE SIGNAL ;
    PORT
      LAYER M5 ;
        RECT  27.132 86.208 27.156 86.4 ;
    END
  END cfg_data[95]
  PIN cfg_data[96]
    DIRECTION INPUT ;
    USE SIGNAL ;
    PORT
      LAYER M5 ;
        RECT  27.324 86.208 27.348 86.4 ;
    END
  END cfg_data[96]
  PIN cfg_data[97]
    DIRECTION INPUT ;
    USE SIGNAL ;
    PORT
      LAYER M5 ;
        RECT  27.564 86.208 27.588 86.4 ;
    END
  END cfg_data[97]
  PIN cfg_data[98]
    DIRECTION INPUT ;
    USE SIGNAL ;
    PORT
      LAYER M5 ;
        RECT  27.756 86.208 27.78 86.4 ;
    END
  END cfg_data[98]
  PIN cfg_data[99]
    DIRECTION INPUT ;
    USE SIGNAL ;
    PORT
      LAYER M5 ;
        RECT  27.948 86.208 27.972 86.4 ;
    END
  END cfg_data[99]
  PIN cfg_data[9]
    DIRECTION INPUT ;
    USE SIGNAL ;
    PORT
      LAYER M5 ;
        RECT  8.94 86.208 8.964 86.4 ;
    END
  END cfg_data[9]
  PIN cfg_target[0]
    DIRECTION INPUT ;
    USE SIGNAL ;
    PORT
      LAYER M5 ;
        RECT  2.796 86.208 2.82 86.4 ;
    END
  END cfg_target[0]
  PIN cfg_target[1]
    DIRECTION INPUT ;
    USE SIGNAL ;
    PORT
      LAYER M5 ;
        RECT  3.036 86.208 3.06 86.4 ;
    END
  END cfg_target[1]
  PIN cfg_target[2]
    DIRECTION INPUT ;
    USE SIGNAL ;
    PORT
      LAYER M5 ;
        RECT  3.228 86.208 3.252 86.4 ;
    END
  END cfg_target[2]
  PIN cfg_target[3]
    DIRECTION INPUT ;
    USE SIGNAL ;
    PORT
      LAYER M5 ;
        RECT  3.42 86.208 3.444 86.4 ;
    END
  END cfg_target[3]
  PIN cfg_target[4]
    DIRECTION INPUT ;
    USE SIGNAL ;
    PORT
      LAYER M5 ;
        RECT  3.66 86.208 3.684 86.4 ;
    END
  END cfg_target[4]
  PIN cfg_target[5]
    DIRECTION INPUT ;
    USE SIGNAL ;
    PORT
      LAYER M5 ;
        RECT  3.852 86.208 3.876 86.4 ;
    END
  END cfg_target[5]
  PIN cfg_target[6]
    DIRECTION INPUT ;
    USE SIGNAL ;
    PORT
      LAYER M5 ;
        RECT  4.092 86.208 4.116 86.4 ;
    END
  END cfg_target[6]
  PIN cfg_target[7]
    DIRECTION INPUT ;
    USE SIGNAL ;
    PORT
      LAYER M5 ;
        RECT  4.284 86.208 4.308 86.4 ;
    END
  END cfg_target[7]
  PIN cfg_v
    DIRECTION INPUT ;
    USE SIGNAL ;
    PORT
      LAYER M5 ;
        RECT  2.172 86.208 2.196 86.4 ;
    END
  END cfg_v
  PIN clk
    DIRECTION INPUT ;
    USE SIGNAL ;
    PORT
      LAYER M5 ;
        RECT  43.208 43.104 43.24 43.296 ;
    END
  END clk
  PIN clk_in
    DIRECTION INPUT ;
    USE SIGNAL ;
    PORT
      LAYER M4 ;
        RECT  0 52.476 0.192 52.5 ;
    END
  END clk_in
  PIN desc_v
    DIRECTION INPUT ;
    USE SIGNAL ;
    PORT
      LAYER M5 ;
        RECT  2.364 86.208 2.388 86.4 ;
    END
  END desc_v
  PIN fault
    DIRECTION OUTPUT ;
    USE SIGNAL ;
    PORT
      LAYER M5 ;
        RECT  61.356 86.208 61.38 86.4 ;
    END
  END fault
  PIN go[0]
    DIRECTION OUTPUT ;
    USE SIGNAL ;
    PORT
      LAYER M4 ;
        RECT  0 50.364 0.192 50.388 ;
    END
  END go[0]
  PIN go[1]
    DIRECTION OUTPUT ;
    USE SIGNAL ;
    PORT
      LAYER M4 ;
        RECT  0 50.604 0.192 50.628 ;
    END
  END go[1]
  PIN launch_v
    DIRECTION INPUT ;
    USE SIGNAL ;
    PORT
      LAYER M5 ;
        RECT  2.604 86.208 2.628 86.4 ;
    END
  END launch_v
  PIN prm[0]
    DIRECTION OUTPUT ;
    USE SIGNAL ;
    PORT
      LAYER M4 ;
        RECT  86.208 2.172 86.4 2.196 ;
    END
  END prm[0]
  PIN prm[100]
    DIRECTION OUTPUT ;
    USE SIGNAL ;
    PORT
      LAYER M4 ;
        RECT  86.208 23.292 86.4 23.316 ;
    END
  END prm[100]
  PIN prm[101]
    DIRECTION OUTPUT ;
    USE SIGNAL ;
    PORT
      LAYER M4 ;
        RECT  86.208 23.532 86.4 23.556 ;
    END
  END prm[101]
  PIN prm[102]
    DIRECTION OUTPUT ;
    USE SIGNAL ;
    PORT
      LAYER M4 ;
        RECT  86.208 23.724 86.4 23.748 ;
    END
  END prm[102]
  PIN prm[103]
    DIRECTION OUTPUT ;
    USE SIGNAL ;
    PORT
      LAYER M4 ;
        RECT  86.208 23.964 86.4 23.988 ;
    END
  END prm[103]
  PIN prm[104]
    DIRECTION OUTPUT ;
    USE SIGNAL ;
    PORT
      LAYER M4 ;
        RECT  86.208 24.156 86.4 24.18 ;
    END
  END prm[104]
  PIN prm[105]
    DIRECTION OUTPUT ;
    USE SIGNAL ;
    PORT
      LAYER M4 ;
        RECT  86.208 24.348 86.4 24.372 ;
    END
  END prm[105]
  PIN prm[106]
    DIRECTION OUTPUT ;
    USE SIGNAL ;
    PORT
      LAYER M4 ;
        RECT  86.208 24.588 86.4 24.612 ;
    END
  END prm[106]
  PIN prm[107]
    DIRECTION OUTPUT ;
    USE SIGNAL ;
    PORT
      LAYER M4 ;
        RECT  86.208 24.78 86.4 24.804 ;
    END
  END prm[107]
  PIN prm[108]
    DIRECTION OUTPUT ;
    USE SIGNAL ;
    PORT
      LAYER M4 ;
        RECT  86.208 25.02 86.4 25.044 ;
    END
  END prm[108]
  PIN prm[109]
    DIRECTION OUTPUT ;
    USE SIGNAL ;
    PORT
      LAYER M4 ;
        RECT  86.208 25.212 86.4 25.236 ;
    END
  END prm[109]
  PIN prm[10]
    DIRECTION OUTPUT ;
    USE SIGNAL ;
    PORT
      LAYER M4 ;
        RECT  86.208 4.284 86.4 4.308 ;
    END
  END prm[10]
  PIN prm[110]
    DIRECTION OUTPUT ;
    USE SIGNAL ;
    PORT
      LAYER M4 ;
        RECT  86.208 25.452 86.4 25.476 ;
    END
  END prm[110]
  PIN prm[111]
    DIRECTION OUTPUT ;
    USE SIGNAL ;
    PORT
      LAYER M4 ;
        RECT  86.208 25.644 86.4 25.668 ;
    END
  END prm[111]
  PIN prm[112]
    DIRECTION OUTPUT ;
    USE SIGNAL ;
    PORT
      LAYER M4 ;
        RECT  86.208 25.836 86.4 25.86 ;
    END
  END prm[112]
  PIN prm[113]
    DIRECTION OUTPUT ;
    USE SIGNAL ;
    PORT
      LAYER M4 ;
        RECT  86.208 26.076 86.4 26.1 ;
    END
  END prm[113]
  PIN prm[114]
    DIRECTION OUTPUT ;
    USE SIGNAL ;
    PORT
      LAYER M4 ;
        RECT  86.208 26.268 86.4 26.292 ;
    END
  END prm[114]
  PIN prm[115]
    DIRECTION OUTPUT ;
    USE SIGNAL ;
    PORT
      LAYER M4 ;
        RECT  86.208 26.508 86.4 26.532 ;
    END
  END prm[115]
  PIN prm[116]
    DIRECTION OUTPUT ;
    USE SIGNAL ;
    PORT
      LAYER M4 ;
        RECT  86.208 26.7 86.4 26.724 ;
    END
  END prm[116]
  PIN prm[117]
    DIRECTION OUTPUT ;
    USE SIGNAL ;
    PORT
      LAYER M4 ;
        RECT  86.208 26.892 86.4 26.916 ;
    END
  END prm[117]
  PIN prm[118]
    DIRECTION OUTPUT ;
    USE SIGNAL ;
    PORT
      LAYER M4 ;
        RECT  86.208 27.132 86.4 27.156 ;
    END
  END prm[118]
  PIN prm[119]
    DIRECTION OUTPUT ;
    USE SIGNAL ;
    PORT
      LAYER M4 ;
        RECT  86.208 27.324 86.4 27.348 ;
    END
  END prm[119]
  PIN prm[11]
    DIRECTION OUTPUT ;
    USE SIGNAL ;
    PORT
      LAYER M4 ;
        RECT  86.208 4.476 86.4 4.5 ;
    END
  END prm[11]
  PIN prm[120]
    DIRECTION OUTPUT ;
    USE SIGNAL ;
    PORT
      LAYER M4 ;
        RECT  86.208 27.564 86.4 27.588 ;
    END
  END prm[120]
  PIN prm[121]
    DIRECTION OUTPUT ;
    USE SIGNAL ;
    PORT
      LAYER M4 ;
        RECT  86.208 27.756 86.4 27.78 ;
    END
  END prm[121]
  PIN prm[122]
    DIRECTION OUTPUT ;
    USE SIGNAL ;
    PORT
      LAYER M4 ;
        RECT  86.208 27.948 86.4 27.972 ;
    END
  END prm[122]
  PIN prm[123]
    DIRECTION OUTPUT ;
    USE SIGNAL ;
    PORT
      LAYER M4 ;
        RECT  86.208 28.188 86.4 28.212 ;
    END
  END prm[123]
  PIN prm[124]
    DIRECTION OUTPUT ;
    USE SIGNAL ;
    PORT
      LAYER M4 ;
        RECT  86.208 28.38 86.4 28.404 ;
    END
  END prm[124]
  PIN prm[125]
    DIRECTION OUTPUT ;
    USE SIGNAL ;
    PORT
      LAYER M4 ;
        RECT  86.208 28.62 86.4 28.644 ;
    END
  END prm[125]
  PIN prm[126]
    DIRECTION OUTPUT ;
    USE SIGNAL ;
    PORT
      LAYER M4 ;
        RECT  86.208 28.812 86.4 28.836 ;
    END
  END prm[126]
  PIN prm[127]
    DIRECTION OUTPUT ;
    USE SIGNAL ;
    PORT
      LAYER M4 ;
        RECT  86.208 29.004 86.4 29.028 ;
    END
  END prm[127]
  PIN prm[128]
    DIRECTION OUTPUT ;
    USE SIGNAL ;
    PORT
      LAYER M4 ;
        RECT  86.208 29.244 86.4 29.268 ;
    END
  END prm[128]
  PIN prm[129]
    DIRECTION OUTPUT ;
    USE SIGNAL ;
    PORT
      LAYER M4 ;
        RECT  86.208 29.436 86.4 29.46 ;
    END
  END prm[129]
  PIN prm[12]
    DIRECTION OUTPUT ;
    USE SIGNAL ;
    PORT
      LAYER M4 ;
        RECT  86.208 4.716 86.4 4.74 ;
    END
  END prm[12]
  PIN prm[130]
    DIRECTION OUTPUT ;
    USE SIGNAL ;
    PORT
      LAYER M4 ;
        RECT  86.208 29.676 86.4 29.7 ;
    END
  END prm[130]
  PIN prm[131]
    DIRECTION OUTPUT ;
    USE SIGNAL ;
    PORT
      LAYER M4 ;
        RECT  86.208 29.868 86.4 29.892 ;
    END
  END prm[131]
  PIN prm[132]
    DIRECTION OUTPUT ;
    USE SIGNAL ;
    PORT
      LAYER M4 ;
        RECT  86.208 30.06 86.4 30.084 ;
    END
  END prm[132]
  PIN prm[133]
    DIRECTION OUTPUT ;
    USE SIGNAL ;
    PORT
      LAYER M4 ;
        RECT  86.208 30.3 86.4 30.324 ;
    END
  END prm[133]
  PIN prm[134]
    DIRECTION OUTPUT ;
    USE SIGNAL ;
    PORT
      LAYER M4 ;
        RECT  86.208 30.492 86.4 30.516 ;
    END
  END prm[134]
  PIN prm[135]
    DIRECTION OUTPUT ;
    USE SIGNAL ;
    PORT
      LAYER M4 ;
        RECT  86.208 30.732 86.4 30.756 ;
    END
  END prm[135]
  PIN prm[136]
    DIRECTION OUTPUT ;
    USE SIGNAL ;
    PORT
      LAYER M4 ;
        RECT  86.208 30.924 86.4 30.948 ;
    END
  END prm[136]
  PIN prm[137]
    DIRECTION OUTPUT ;
    USE SIGNAL ;
    PORT
      LAYER M4 ;
        RECT  86.208 31.116 86.4 31.14 ;
    END
  END prm[137]
  PIN prm[138]
    DIRECTION OUTPUT ;
    USE SIGNAL ;
    PORT
      LAYER M4 ;
        RECT  86.208 31.356 86.4 31.38 ;
    END
  END prm[138]
  PIN prm[139]
    DIRECTION OUTPUT ;
    USE SIGNAL ;
    PORT
      LAYER M4 ;
        RECT  86.208 31.548 86.4 31.572 ;
    END
  END prm[139]
  PIN prm[13]
    DIRECTION OUTPUT ;
    USE SIGNAL ;
    PORT
      LAYER M4 ;
        RECT  86.208 4.908 86.4 4.932 ;
    END
  END prm[13]
  PIN prm[140]
    DIRECTION OUTPUT ;
    USE SIGNAL ;
    PORT
      LAYER M4 ;
        RECT  86.208 31.788 86.4 31.812 ;
    END
  END prm[140]
  PIN prm[141]
    DIRECTION OUTPUT ;
    USE SIGNAL ;
    PORT
      LAYER M4 ;
        RECT  86.208 31.98 86.4 32.004 ;
    END
  END prm[141]
  PIN prm[142]
    DIRECTION OUTPUT ;
    USE SIGNAL ;
    PORT
      LAYER M4 ;
        RECT  86.208 32.172 86.4 32.196 ;
    END
  END prm[142]
  PIN prm[143]
    DIRECTION OUTPUT ;
    USE SIGNAL ;
    PORT
      LAYER M4 ;
        RECT  86.208 32.412 86.4 32.436 ;
    END
  END prm[143]
  PIN prm[144]
    DIRECTION OUTPUT ;
    USE SIGNAL ;
    PORT
      LAYER M4 ;
        RECT  86.208 32.604 86.4 32.628 ;
    END
  END prm[144]
  PIN prm[145]
    DIRECTION OUTPUT ;
    USE SIGNAL ;
    PORT
      LAYER M4 ;
        RECT  86.208 32.844 86.4 32.868 ;
    END
  END prm[145]
  PIN prm[146]
    DIRECTION OUTPUT ;
    USE SIGNAL ;
    PORT
      LAYER M4 ;
        RECT  86.208 33.036 86.4 33.06 ;
    END
  END prm[146]
  PIN prm[147]
    DIRECTION OUTPUT ;
    USE SIGNAL ;
    PORT
      LAYER M4 ;
        RECT  86.208 33.228 86.4 33.252 ;
    END
  END prm[147]
  PIN prm[148]
    DIRECTION OUTPUT ;
    USE SIGNAL ;
    PORT
      LAYER M4 ;
        RECT  86.208 33.468 86.4 33.492 ;
    END
  END prm[148]
  PIN prm[149]
    DIRECTION OUTPUT ;
    USE SIGNAL ;
    PORT
      LAYER M4 ;
        RECT  86.208 33.66 86.4 33.684 ;
    END
  END prm[149]
  PIN prm[14]
    DIRECTION OUTPUT ;
    USE SIGNAL ;
    PORT
      LAYER M4 ;
        RECT  86.208 5.148 86.4 5.172 ;
    END
  END prm[14]
  PIN prm[150]
    DIRECTION OUTPUT ;
    USE SIGNAL ;
    PORT
      LAYER M4 ;
        RECT  86.208 33.9 86.4 33.924 ;
    END
  END prm[150]
  PIN prm[151]
    DIRECTION OUTPUT ;
    USE SIGNAL ;
    PORT
      LAYER M4 ;
        RECT  86.208 34.092 86.4 34.116 ;
    END
  END prm[151]
  PIN prm[152]
    DIRECTION OUTPUT ;
    USE SIGNAL ;
    PORT
      LAYER M4 ;
        RECT  86.208 34.332 86.4 34.356 ;
    END
  END prm[152]
  PIN prm[153]
    DIRECTION OUTPUT ;
    USE SIGNAL ;
    PORT
      LAYER M4 ;
        RECT  86.208 34.524 86.4 34.548 ;
    END
  END prm[153]
  PIN prm[154]
    DIRECTION OUTPUT ;
    USE SIGNAL ;
    PORT
      LAYER M4 ;
        RECT  86.208 34.716 86.4 34.74 ;
    END
  END prm[154]
  PIN prm[155]
    DIRECTION OUTPUT ;
    USE SIGNAL ;
    PORT
      LAYER M4 ;
        RECT  86.208 34.956 86.4 34.98 ;
    END
  END prm[155]
  PIN prm[156]
    DIRECTION OUTPUT ;
    USE SIGNAL ;
    PORT
      LAYER M4 ;
        RECT  86.208 35.148 86.4 35.172 ;
    END
  END prm[156]
  PIN prm[157]
    DIRECTION OUTPUT ;
    USE SIGNAL ;
    PORT
      LAYER M4 ;
        RECT  86.208 35.388 86.4 35.412 ;
    END
  END prm[157]
  PIN prm[158]
    DIRECTION OUTPUT ;
    USE SIGNAL ;
    PORT
      LAYER M4 ;
        RECT  86.208 35.58 86.4 35.604 ;
    END
  END prm[158]
  PIN prm[159]
    DIRECTION OUTPUT ;
    USE SIGNAL ;
    PORT
      LAYER M4 ;
        RECT  86.208 35.772 86.4 35.796 ;
    END
  END prm[159]
  PIN prm[15]
    DIRECTION OUTPUT ;
    USE SIGNAL ;
    PORT
      LAYER M4 ;
        RECT  86.208 5.34 86.4 5.364 ;
    END
  END prm[15]
  PIN prm[160]
    DIRECTION OUTPUT ;
    USE SIGNAL ;
    PORT
      LAYER M4 ;
        RECT  86.208 36.012 86.4 36.036 ;
    END
  END prm[160]
  PIN prm[161]
    DIRECTION OUTPUT ;
    USE SIGNAL ;
    PORT
      LAYER M4 ;
        RECT  86.208 36.204 86.4 36.228 ;
    END
  END prm[161]
  PIN prm[162]
    DIRECTION OUTPUT ;
    USE SIGNAL ;
    PORT
      LAYER M4 ;
        RECT  86.208 36.444 86.4 36.468 ;
    END
  END prm[162]
  PIN prm[163]
    DIRECTION OUTPUT ;
    USE SIGNAL ;
    PORT
      LAYER M4 ;
        RECT  86.208 36.636 86.4 36.66 ;
    END
  END prm[163]
  PIN prm[164]
    DIRECTION OUTPUT ;
    USE SIGNAL ;
    PORT
      LAYER M4 ;
        RECT  86.208 36.828 86.4 36.852 ;
    END
  END prm[164]
  PIN prm[165]
    DIRECTION OUTPUT ;
    USE SIGNAL ;
    PORT
      LAYER M4 ;
        RECT  86.208 37.068 86.4 37.092 ;
    END
  END prm[165]
  PIN prm[166]
    DIRECTION OUTPUT ;
    USE SIGNAL ;
    PORT
      LAYER M4 ;
        RECT  86.208 37.26 86.4 37.284 ;
    END
  END prm[166]
  PIN prm[167]
    DIRECTION OUTPUT ;
    USE SIGNAL ;
    PORT
      LAYER M4 ;
        RECT  86.208 37.5 86.4 37.524 ;
    END
  END prm[167]
  PIN prm[168]
    DIRECTION OUTPUT ;
    USE SIGNAL ;
    PORT
      LAYER M4 ;
        RECT  86.208 37.692 86.4 37.716 ;
    END
  END prm[168]
  PIN prm[169]
    DIRECTION OUTPUT ;
    USE SIGNAL ;
    PORT
      LAYER M4 ;
        RECT  86.208 37.884 86.4 37.908 ;
    END
  END prm[169]
  PIN prm[16]
    DIRECTION OUTPUT ;
    USE SIGNAL ;
    PORT
      LAYER M4 ;
        RECT  86.208 5.532 86.4 5.556 ;
    END
  END prm[16]
  PIN prm[170]
    DIRECTION OUTPUT ;
    USE SIGNAL ;
    PORT
      LAYER M4 ;
        RECT  86.208 38.124 86.4 38.148 ;
    END
  END prm[170]
  PIN prm[171]
    DIRECTION OUTPUT ;
    USE SIGNAL ;
    PORT
      LAYER M4 ;
        RECT  86.208 38.316 86.4 38.34 ;
    END
  END prm[171]
  PIN prm[172]
    DIRECTION OUTPUT ;
    USE SIGNAL ;
    PORT
      LAYER M4 ;
        RECT  86.208 38.556 86.4 38.58 ;
    END
  END prm[172]
  PIN prm[173]
    DIRECTION OUTPUT ;
    USE SIGNAL ;
    PORT
      LAYER M4 ;
        RECT  86.208 38.748 86.4 38.772 ;
    END
  END prm[173]
  PIN prm[174]
    DIRECTION OUTPUT ;
    USE SIGNAL ;
    PORT
      LAYER M4 ;
        RECT  86.208 38.94 86.4 38.964 ;
    END
  END prm[174]
  PIN prm[175]
    DIRECTION OUTPUT ;
    USE SIGNAL ;
    PORT
      LAYER M4 ;
        RECT  86.208 39.18 86.4 39.204 ;
    END
  END prm[175]
  PIN prm[176]
    DIRECTION OUTPUT ;
    USE SIGNAL ;
    PORT
      LAYER M4 ;
        RECT  86.208 39.372 86.4 39.396 ;
    END
  END prm[176]
  PIN prm[177]
    DIRECTION OUTPUT ;
    USE SIGNAL ;
    PORT
      LAYER M4 ;
        RECT  86.208 39.612 86.4 39.636 ;
    END
  END prm[177]
  PIN prm[178]
    DIRECTION OUTPUT ;
    USE SIGNAL ;
    PORT
      LAYER M4 ;
        RECT  86.208 39.804 86.4 39.828 ;
    END
  END prm[178]
  PIN prm[179]
    DIRECTION OUTPUT ;
    USE SIGNAL ;
    PORT
      LAYER M4 ;
        RECT  86.208 39.996 86.4 40.02 ;
    END
  END prm[179]
  PIN prm[17]
    DIRECTION OUTPUT ;
    USE SIGNAL ;
    PORT
      LAYER M4 ;
        RECT  86.208 5.772 86.4 5.796 ;
    END
  END prm[17]
  PIN prm[180]
    DIRECTION OUTPUT ;
    USE SIGNAL ;
    PORT
      LAYER M4 ;
        RECT  86.208 40.236 86.4 40.26 ;
    END
  END prm[180]
  PIN prm[181]
    DIRECTION OUTPUT ;
    USE SIGNAL ;
    PORT
      LAYER M4 ;
        RECT  86.208 40.428 86.4 40.452 ;
    END
  END prm[181]
  PIN prm[182]
    DIRECTION OUTPUT ;
    USE SIGNAL ;
    PORT
      LAYER M4 ;
        RECT  86.208 40.668 86.4 40.692 ;
    END
  END prm[182]
  PIN prm[183]
    DIRECTION OUTPUT ;
    USE SIGNAL ;
    PORT
      LAYER M4 ;
        RECT  86.208 40.86 86.4 40.884 ;
    END
  END prm[183]
  PIN prm[184]
    DIRECTION OUTPUT ;
    USE SIGNAL ;
    PORT
      LAYER M4 ;
        RECT  86.208 41.052 86.4 41.076 ;
    END
  END prm[184]
  PIN prm[185]
    DIRECTION OUTPUT ;
    USE SIGNAL ;
    PORT
      LAYER M4 ;
        RECT  86.208 41.292 86.4 41.316 ;
    END
  END prm[185]
  PIN prm[186]
    DIRECTION OUTPUT ;
    USE SIGNAL ;
    PORT
      LAYER M4 ;
        RECT  86.208 41.484 86.4 41.508 ;
    END
  END prm[186]
  PIN prm[187]
    DIRECTION OUTPUT ;
    USE SIGNAL ;
    PORT
      LAYER M4 ;
        RECT  86.208 41.724 86.4 41.748 ;
    END
  END prm[187]
  PIN prm[188]
    DIRECTION OUTPUT ;
    USE SIGNAL ;
    PORT
      LAYER M4 ;
        RECT  86.208 41.916 86.4 41.94 ;
    END
  END prm[188]
  PIN prm[189]
    DIRECTION OUTPUT ;
    USE SIGNAL ;
    PORT
      LAYER M4 ;
        RECT  86.208 42.108 86.4 42.132 ;
    END
  END prm[189]
  PIN prm[18]
    DIRECTION OUTPUT ;
    USE SIGNAL ;
    PORT
      LAYER M4 ;
        RECT  86.208 5.964 86.4 5.988 ;
    END
  END prm[18]
  PIN prm[190]
    DIRECTION OUTPUT ;
    USE SIGNAL ;
    PORT
      LAYER M4 ;
        RECT  86.208 42.348 86.4 42.372 ;
    END
  END prm[190]
  PIN prm[191]
    DIRECTION OUTPUT ;
    USE SIGNAL ;
    PORT
      LAYER M4 ;
        RECT  86.208 42.54 86.4 42.564 ;
    END
  END prm[191]
  PIN prm[192]
    DIRECTION OUTPUT ;
    USE SIGNAL ;
    PORT
      LAYER M4 ;
        RECT  86.208 42.78 86.4 42.804 ;
    END
  END prm[192]
  PIN prm[193]
    DIRECTION OUTPUT ;
    USE SIGNAL ;
    PORT
      LAYER M4 ;
        RECT  86.208 42.972 86.4 42.996 ;
    END
  END prm[193]
  PIN prm[194]
    DIRECTION OUTPUT ;
    USE SIGNAL ;
    PORT
      LAYER M4 ;
        RECT  86.208 43.212 86.4 43.236 ;
    END
  END prm[194]
  PIN prm[195]
    DIRECTION OUTPUT ;
    USE SIGNAL ;
    PORT
      LAYER M4 ;
        RECT  86.208 43.404 86.4 43.428 ;
    END
  END prm[195]
  PIN prm[196]
    DIRECTION OUTPUT ;
    USE SIGNAL ;
    PORT
      LAYER M4 ;
        RECT  86.208 43.596 86.4 43.62 ;
    END
  END prm[196]
  PIN prm[197]
    DIRECTION OUTPUT ;
    USE SIGNAL ;
    PORT
      LAYER M4 ;
        RECT  86.208 43.836 86.4 43.86 ;
    END
  END prm[197]
  PIN prm[198]
    DIRECTION OUTPUT ;
    USE SIGNAL ;
    PORT
      LAYER M4 ;
        RECT  86.208 44.028 86.4 44.052 ;
    END
  END prm[198]
  PIN prm[199]
    DIRECTION OUTPUT ;
    USE SIGNAL ;
    PORT
      LAYER M4 ;
        RECT  86.208 44.268 86.4 44.292 ;
    END
  END prm[199]
  PIN prm[19]
    DIRECTION OUTPUT ;
    USE SIGNAL ;
    PORT
      LAYER M4 ;
        RECT  86.208 6.204 86.4 6.228 ;
    END
  END prm[19]
  PIN prm[1]
    DIRECTION OUTPUT ;
    USE SIGNAL ;
    PORT
      LAYER M4 ;
        RECT  86.208 2.364 86.4 2.388 ;
    END
  END prm[1]
  PIN prm[200]
    DIRECTION OUTPUT ;
    USE SIGNAL ;
    PORT
      LAYER M4 ;
        RECT  86.208 44.46 86.4 44.484 ;
    END
  END prm[200]
  PIN prm[201]
    DIRECTION OUTPUT ;
    USE SIGNAL ;
    PORT
      LAYER M4 ;
        RECT  86.208 44.652 86.4 44.676 ;
    END
  END prm[201]
  PIN prm[202]
    DIRECTION OUTPUT ;
    USE SIGNAL ;
    PORT
      LAYER M4 ;
        RECT  86.208 44.892 86.4 44.916 ;
    END
  END prm[202]
  PIN prm[203]
    DIRECTION OUTPUT ;
    USE SIGNAL ;
    PORT
      LAYER M4 ;
        RECT  86.208 45.084 86.4 45.108 ;
    END
  END prm[203]
  PIN prm[204]
    DIRECTION OUTPUT ;
    USE SIGNAL ;
    PORT
      LAYER M4 ;
        RECT  86.208 45.324 86.4 45.348 ;
    END
  END prm[204]
  PIN prm[205]
    DIRECTION OUTPUT ;
    USE SIGNAL ;
    PORT
      LAYER M4 ;
        RECT  86.208 45.516 86.4 45.54 ;
    END
  END prm[205]
  PIN prm[206]
    DIRECTION OUTPUT ;
    USE SIGNAL ;
    PORT
      LAYER M4 ;
        RECT  86.208 45.708 86.4 45.732 ;
    END
  END prm[206]
  PIN prm[207]
    DIRECTION OUTPUT ;
    USE SIGNAL ;
    PORT
      LAYER M4 ;
        RECT  86.208 45.948 86.4 45.972 ;
    END
  END prm[207]
  PIN prm[208]
    DIRECTION OUTPUT ;
    USE SIGNAL ;
    PORT
      LAYER M4 ;
        RECT  86.208 46.14 86.4 46.164 ;
    END
  END prm[208]
  PIN prm[209]
    DIRECTION OUTPUT ;
    USE SIGNAL ;
    PORT
      LAYER M4 ;
        RECT  86.208 46.38 86.4 46.404 ;
    END
  END prm[209]
  PIN prm[20]
    DIRECTION OUTPUT ;
    USE SIGNAL ;
    PORT
      LAYER M4 ;
        RECT  86.208 6.396 86.4 6.42 ;
    END
  END prm[20]
  PIN prm[210]
    DIRECTION OUTPUT ;
    USE SIGNAL ;
    PORT
      LAYER M4 ;
        RECT  86.208 46.572 86.4 46.596 ;
    END
  END prm[210]
  PIN prm[211]
    DIRECTION OUTPUT ;
    USE SIGNAL ;
    PORT
      LAYER M4 ;
        RECT  86.208 46.764 86.4 46.788 ;
    END
  END prm[211]
  PIN prm[212]
    DIRECTION OUTPUT ;
    USE SIGNAL ;
    PORT
      LAYER M4 ;
        RECT  86.208 47.004 86.4 47.028 ;
    END
  END prm[212]
  PIN prm[213]
    DIRECTION OUTPUT ;
    USE SIGNAL ;
    PORT
      LAYER M4 ;
        RECT  86.208 47.196 86.4 47.22 ;
    END
  END prm[213]
  PIN prm[214]
    DIRECTION OUTPUT ;
    USE SIGNAL ;
    PORT
      LAYER M4 ;
        RECT  86.208 47.436 86.4 47.46 ;
    END
  END prm[214]
  PIN prm[215]
    DIRECTION OUTPUT ;
    USE SIGNAL ;
    PORT
      LAYER M4 ;
        RECT  86.208 47.628 86.4 47.652 ;
    END
  END prm[215]
  PIN prm[216]
    DIRECTION OUTPUT ;
    USE SIGNAL ;
    PORT
      LAYER M4 ;
        RECT  86.208 47.82 86.4 47.844 ;
    END
  END prm[216]
  PIN prm[217]
    DIRECTION OUTPUT ;
    USE SIGNAL ;
    PORT
      LAYER M4 ;
        RECT  86.208 48.06 86.4 48.084 ;
    END
  END prm[217]
  PIN prm[218]
    DIRECTION OUTPUT ;
    USE SIGNAL ;
    PORT
      LAYER M4 ;
        RECT  86.208 48.252 86.4 48.276 ;
    END
  END prm[218]
  PIN prm[219]
    DIRECTION OUTPUT ;
    USE SIGNAL ;
    PORT
      LAYER M4 ;
        RECT  86.208 48.492 86.4 48.516 ;
    END
  END prm[219]
  PIN prm[21]
    DIRECTION OUTPUT ;
    USE SIGNAL ;
    PORT
      LAYER M4 ;
        RECT  86.208 6.588 86.4 6.612 ;
    END
  END prm[21]
  PIN prm[220]
    DIRECTION OUTPUT ;
    USE SIGNAL ;
    PORT
      LAYER M4 ;
        RECT  86.208 48.684 86.4 48.708 ;
    END
  END prm[220]
  PIN prm[221]
    DIRECTION OUTPUT ;
    USE SIGNAL ;
    PORT
      LAYER M4 ;
        RECT  86.208 48.876 86.4 48.9 ;
    END
  END prm[221]
  PIN prm[222]
    DIRECTION OUTPUT ;
    USE SIGNAL ;
    PORT
      LAYER M4 ;
        RECT  86.208 49.116 86.4 49.14 ;
    END
  END prm[222]
  PIN prm[223]
    DIRECTION OUTPUT ;
    USE SIGNAL ;
    PORT
      LAYER M4 ;
        RECT  86.208 49.308 86.4 49.332 ;
    END
  END prm[223]
  PIN prm[224]
    DIRECTION OUTPUT ;
    USE SIGNAL ;
    PORT
      LAYER M4 ;
        RECT  86.208 49.548 86.4 49.572 ;
    END
  END prm[224]
  PIN prm[225]
    DIRECTION OUTPUT ;
    USE SIGNAL ;
    PORT
      LAYER M4 ;
        RECT  86.208 49.74 86.4 49.764 ;
    END
  END prm[225]
  PIN prm[226]
    DIRECTION OUTPUT ;
    USE SIGNAL ;
    PORT
      LAYER M4 ;
        RECT  86.208 49.932 86.4 49.956 ;
    END
  END prm[226]
  PIN prm[227]
    DIRECTION OUTPUT ;
    USE SIGNAL ;
    PORT
      LAYER M4 ;
        RECT  86.208 50.172 86.4 50.196 ;
    END
  END prm[227]
  PIN prm[228]
    DIRECTION OUTPUT ;
    USE SIGNAL ;
    PORT
      LAYER M4 ;
        RECT  86.208 50.364 86.4 50.388 ;
    END
  END prm[228]
  PIN prm[229]
    DIRECTION OUTPUT ;
    USE SIGNAL ;
    PORT
      LAYER M4 ;
        RECT  86.208 50.604 86.4 50.628 ;
    END
  END prm[229]
  PIN prm[22]
    DIRECTION OUTPUT ;
    USE SIGNAL ;
    PORT
      LAYER M4 ;
        RECT  86.208 6.828 86.4 6.852 ;
    END
  END prm[22]
  PIN prm[230]
    DIRECTION OUTPUT ;
    USE SIGNAL ;
    PORT
      LAYER M4 ;
        RECT  86.208 50.796 86.4 50.82 ;
    END
  END prm[230]
  PIN prm[231]
    DIRECTION OUTPUT ;
    USE SIGNAL ;
    PORT
      LAYER M4 ;
        RECT  86.208 50.988 86.4 51.012 ;
    END
  END prm[231]
  PIN prm[232]
    DIRECTION OUTPUT ;
    USE SIGNAL ;
    PORT
      LAYER M4 ;
        RECT  86.208 51.228 86.4 51.252 ;
    END
  END prm[232]
  PIN prm[233]
    DIRECTION OUTPUT ;
    USE SIGNAL ;
    PORT
      LAYER M4 ;
        RECT  86.208 51.42 86.4 51.444 ;
    END
  END prm[233]
  PIN prm[234]
    DIRECTION OUTPUT ;
    USE SIGNAL ;
    PORT
      LAYER M4 ;
        RECT  86.208 51.66 86.4 51.684 ;
    END
  END prm[234]
  PIN prm[235]
    DIRECTION OUTPUT ;
    USE SIGNAL ;
    PORT
      LAYER M4 ;
        RECT  86.208 51.852 86.4 51.876 ;
    END
  END prm[235]
  PIN prm[236]
    DIRECTION OUTPUT ;
    USE SIGNAL ;
    PORT
      LAYER M4 ;
        RECT  86.208 52.044 86.4 52.068 ;
    END
  END prm[236]
  PIN prm[237]
    DIRECTION OUTPUT ;
    USE SIGNAL ;
    PORT
      LAYER M4 ;
        RECT  86.208 52.284 86.4 52.308 ;
    END
  END prm[237]
  PIN prm[238]
    DIRECTION OUTPUT ;
    USE SIGNAL ;
    PORT
      LAYER M4 ;
        RECT  86.208 52.476 86.4 52.5 ;
    END
  END prm[238]
  PIN prm[239]
    DIRECTION OUTPUT ;
    USE SIGNAL ;
    PORT
      LAYER M4 ;
        RECT  86.208 52.716 86.4 52.74 ;
    END
  END prm[239]
  PIN prm[23]
    DIRECTION OUTPUT ;
    USE SIGNAL ;
    PORT
      LAYER M4 ;
        RECT  86.208 7.02 86.4 7.044 ;
    END
  END prm[23]
  PIN prm[240]
    DIRECTION OUTPUT ;
    USE SIGNAL ;
    PORT
      LAYER M4 ;
        RECT  86.208 52.908 86.4 52.932 ;
    END
  END prm[240]
  PIN prm[241]
    DIRECTION OUTPUT ;
    USE SIGNAL ;
    PORT
      LAYER M4 ;
        RECT  86.208 53.148 86.4 53.172 ;
    END
  END prm[241]
  PIN prm[242]
    DIRECTION OUTPUT ;
    USE SIGNAL ;
    PORT
      LAYER M4 ;
        RECT  86.208 53.34 86.4 53.364 ;
    END
  END prm[242]
  PIN prm[243]
    DIRECTION OUTPUT ;
    USE SIGNAL ;
    PORT
      LAYER M4 ;
        RECT  86.208 53.532 86.4 53.556 ;
    END
  END prm[243]
  PIN prm[244]
    DIRECTION OUTPUT ;
    USE SIGNAL ;
    PORT
      LAYER M4 ;
        RECT  86.208 53.772 86.4 53.796 ;
    END
  END prm[244]
  PIN prm[245]
    DIRECTION OUTPUT ;
    USE SIGNAL ;
    PORT
      LAYER M4 ;
        RECT  86.208 53.964 86.4 53.988 ;
    END
  END prm[245]
  PIN prm[246]
    DIRECTION OUTPUT ;
    USE SIGNAL ;
    PORT
      LAYER M4 ;
        RECT  86.208 54.204 86.4 54.228 ;
    END
  END prm[246]
  PIN prm[247]
    DIRECTION OUTPUT ;
    USE SIGNAL ;
    PORT
      LAYER M4 ;
        RECT  86.208 54.396 86.4 54.42 ;
    END
  END prm[247]
  PIN prm[248]
    DIRECTION OUTPUT ;
    USE SIGNAL ;
    PORT
      LAYER M4 ;
        RECT  86.208 54.588 86.4 54.612 ;
    END
  END prm[248]
  PIN prm[249]
    DIRECTION OUTPUT ;
    USE SIGNAL ;
    PORT
      LAYER M4 ;
        RECT  86.208 54.828 86.4 54.852 ;
    END
  END prm[249]
  PIN prm[24]
    DIRECTION OUTPUT ;
    USE SIGNAL ;
    PORT
      LAYER M4 ;
        RECT  86.208 7.26 86.4 7.284 ;
    END
  END prm[24]
  PIN prm[250]
    DIRECTION OUTPUT ;
    USE SIGNAL ;
    PORT
      LAYER M4 ;
        RECT  86.208 55.02 86.4 55.044 ;
    END
  END prm[250]
  PIN prm[251]
    DIRECTION OUTPUT ;
    USE SIGNAL ;
    PORT
      LAYER M4 ;
        RECT  86.208 55.26 86.4 55.284 ;
    END
  END prm[251]
  PIN prm[252]
    DIRECTION OUTPUT ;
    USE SIGNAL ;
    PORT
      LAYER M4 ;
        RECT  86.208 55.452 86.4 55.476 ;
    END
  END prm[252]
  PIN prm[253]
    DIRECTION OUTPUT ;
    USE SIGNAL ;
    PORT
      LAYER M4 ;
        RECT  86.208 55.644 86.4 55.668 ;
    END
  END prm[253]
  PIN prm[254]
    DIRECTION OUTPUT ;
    USE SIGNAL ;
    PORT
      LAYER M4 ;
        RECT  86.208 55.884 86.4 55.908 ;
    END
  END prm[254]
  PIN prm[255]
    DIRECTION OUTPUT ;
    USE SIGNAL ;
    PORT
      LAYER M4 ;
        RECT  86.208 56.076 86.4 56.1 ;
    END
  END prm[255]
  PIN prm[256]
    DIRECTION OUTPUT ;
    USE SIGNAL ;
    PORT
      LAYER M4 ;
        RECT  86.208 56.316 86.4 56.34 ;
    END
  END prm[256]
  PIN prm[257]
    DIRECTION OUTPUT ;
    USE SIGNAL ;
    PORT
      LAYER M4 ;
        RECT  86.208 56.508 86.4 56.532 ;
    END
  END prm[257]
  PIN prm[258]
    DIRECTION OUTPUT ;
    USE SIGNAL ;
    PORT
      LAYER M4 ;
        RECT  86.208 56.7 86.4 56.724 ;
    END
  END prm[258]
  PIN prm[259]
    DIRECTION OUTPUT ;
    USE SIGNAL ;
    PORT
      LAYER M4 ;
        RECT  86.208 56.94 86.4 56.964 ;
    END
  END prm[259]
  PIN prm[25]
    DIRECTION OUTPUT ;
    USE SIGNAL ;
    PORT
      LAYER M4 ;
        RECT  86.208 7.452 86.4 7.476 ;
    END
  END prm[25]
  PIN prm[260]
    DIRECTION OUTPUT ;
    USE SIGNAL ;
    PORT
      LAYER M4 ;
        RECT  86.208 57.132 86.4 57.156 ;
    END
  END prm[260]
  PIN prm[261]
    DIRECTION OUTPUT ;
    USE SIGNAL ;
    PORT
      LAYER M4 ;
        RECT  86.208 57.372 86.4 57.396 ;
    END
  END prm[261]
  PIN prm[262]
    DIRECTION OUTPUT ;
    USE SIGNAL ;
    PORT
      LAYER M4 ;
        RECT  86.208 57.564 86.4 57.588 ;
    END
  END prm[262]
  PIN prm[263]
    DIRECTION OUTPUT ;
    USE SIGNAL ;
    PORT
      LAYER M4 ;
        RECT  86.208 57.756 86.4 57.78 ;
    END
  END prm[263]
  PIN prm[264]
    DIRECTION OUTPUT ;
    USE SIGNAL ;
    PORT
      LAYER M4 ;
        RECT  86.208 57.996 86.4 58.02 ;
    END
  END prm[264]
  PIN prm[265]
    DIRECTION OUTPUT ;
    USE SIGNAL ;
    PORT
      LAYER M4 ;
        RECT  86.208 58.188 86.4 58.212 ;
    END
  END prm[265]
  PIN prm[266]
    DIRECTION OUTPUT ;
    USE SIGNAL ;
    PORT
      LAYER M4 ;
        RECT  86.208 58.428 86.4 58.452 ;
    END
  END prm[266]
  PIN prm[267]
    DIRECTION OUTPUT ;
    USE SIGNAL ;
    PORT
      LAYER M4 ;
        RECT  86.208 58.62 86.4 58.644 ;
    END
  END prm[267]
  PIN prm[268]
    DIRECTION OUTPUT ;
    USE SIGNAL ;
    PORT
      LAYER M4 ;
        RECT  86.208 58.812 86.4 58.836 ;
    END
  END prm[268]
  PIN prm[269]
    DIRECTION OUTPUT ;
    USE SIGNAL ;
    PORT
      LAYER M4 ;
        RECT  86.208 59.052 86.4 59.076 ;
    END
  END prm[269]
  PIN prm[26]
    DIRECTION OUTPUT ;
    USE SIGNAL ;
    PORT
      LAYER M4 ;
        RECT  86.208 7.692 86.4 7.716 ;
    END
  END prm[26]
  PIN prm[270]
    DIRECTION OUTPUT ;
    USE SIGNAL ;
    PORT
      LAYER M4 ;
        RECT  86.208 59.244 86.4 59.268 ;
    END
  END prm[270]
  PIN prm[271]
    DIRECTION OUTPUT ;
    USE SIGNAL ;
    PORT
      LAYER M4 ;
        RECT  86.208 59.484 86.4 59.508 ;
    END
  END prm[271]
  PIN prm[272]
    DIRECTION OUTPUT ;
    USE SIGNAL ;
    PORT
      LAYER M4 ;
        RECT  86.208 59.676 86.4 59.7 ;
    END
  END prm[272]
  PIN prm[273]
    DIRECTION OUTPUT ;
    USE SIGNAL ;
    PORT
      LAYER M4 ;
        RECT  86.208 59.868 86.4 59.892 ;
    END
  END prm[273]
  PIN prm[274]
    DIRECTION OUTPUT ;
    USE SIGNAL ;
    PORT
      LAYER M4 ;
        RECT  86.208 60.108 86.4 60.132 ;
    END
  END prm[274]
  PIN prm[275]
    DIRECTION OUTPUT ;
    USE SIGNAL ;
    PORT
      LAYER M4 ;
        RECT  86.208 60.3 86.4 60.324 ;
    END
  END prm[275]
  PIN prm[276]
    DIRECTION OUTPUT ;
    USE SIGNAL ;
    PORT
      LAYER M4 ;
        RECT  86.208 60.54 86.4 60.564 ;
    END
  END prm[276]
  PIN prm[277]
    DIRECTION OUTPUT ;
    USE SIGNAL ;
    PORT
      LAYER M4 ;
        RECT  86.208 60.732 86.4 60.756 ;
    END
  END prm[277]
  PIN prm[278]
    DIRECTION OUTPUT ;
    USE SIGNAL ;
    PORT
      LAYER M4 ;
        RECT  86.208 60.924 86.4 60.948 ;
    END
  END prm[278]
  PIN prm[279]
    DIRECTION OUTPUT ;
    USE SIGNAL ;
    PORT
      LAYER M4 ;
        RECT  86.208 61.164 86.4 61.188 ;
    END
  END prm[279]
  PIN prm[27]
    DIRECTION OUTPUT ;
    USE SIGNAL ;
    PORT
      LAYER M4 ;
        RECT  86.208 7.884 86.4 7.908 ;
    END
  END prm[27]
  PIN prm[280]
    DIRECTION OUTPUT ;
    USE SIGNAL ;
    PORT
      LAYER M4 ;
        RECT  86.208 61.356 86.4 61.38 ;
    END
  END prm[280]
  PIN prm[281]
    DIRECTION OUTPUT ;
    USE SIGNAL ;
    PORT
      LAYER M4 ;
        RECT  86.208 61.596 86.4 61.62 ;
    END
  END prm[281]
  PIN prm[282]
    DIRECTION OUTPUT ;
    USE SIGNAL ;
    PORT
      LAYER M4 ;
        RECT  86.208 61.788 86.4 61.812 ;
    END
  END prm[282]
  PIN prm[283]
    DIRECTION OUTPUT ;
    USE SIGNAL ;
    PORT
      LAYER M4 ;
        RECT  86.208 62.028 86.4 62.052 ;
    END
  END prm[283]
  PIN prm[284]
    DIRECTION OUTPUT ;
    USE SIGNAL ;
    PORT
      LAYER M4 ;
        RECT  86.208 62.22 86.4 62.244 ;
    END
  END prm[284]
  PIN prm[285]
    DIRECTION OUTPUT ;
    USE SIGNAL ;
    PORT
      LAYER M4 ;
        RECT  86.208 62.412 86.4 62.436 ;
    END
  END prm[285]
  PIN prm[286]
    DIRECTION OUTPUT ;
    USE SIGNAL ;
    PORT
      LAYER M4 ;
        RECT  86.208 62.652 86.4 62.676 ;
    END
  END prm[286]
  PIN prm[287]
    DIRECTION OUTPUT ;
    USE SIGNAL ;
    PORT
      LAYER M4 ;
        RECT  86.208 62.844 86.4 62.868 ;
    END
  END prm[287]
  PIN prm[288]
    DIRECTION OUTPUT ;
    USE SIGNAL ;
    PORT
      LAYER M4 ;
        RECT  86.208 63.084 86.4 63.108 ;
    END
  END prm[288]
  PIN prm[289]
    DIRECTION OUTPUT ;
    USE SIGNAL ;
    PORT
      LAYER M4 ;
        RECT  86.208 63.276 86.4 63.3 ;
    END
  END prm[289]
  PIN prm[28]
    DIRECTION OUTPUT ;
    USE SIGNAL ;
    PORT
      LAYER M4 ;
        RECT  86.208 8.076 86.4 8.1 ;
    END
  END prm[28]
  PIN prm[290]
    DIRECTION OUTPUT ;
    USE SIGNAL ;
    PORT
      LAYER M4 ;
        RECT  86.208 63.468 86.4 63.492 ;
    END
  END prm[290]
  PIN prm[291]
    DIRECTION OUTPUT ;
    USE SIGNAL ;
    PORT
      LAYER M4 ;
        RECT  86.208 63.708 86.4 63.732 ;
    END
  END prm[291]
  PIN prm[292]
    DIRECTION OUTPUT ;
    USE SIGNAL ;
    PORT
      LAYER M4 ;
        RECT  86.208 63.9 86.4 63.924 ;
    END
  END prm[292]
  PIN prm[293]
    DIRECTION OUTPUT ;
    USE SIGNAL ;
    PORT
      LAYER M4 ;
        RECT  86.208 64.14 86.4 64.164 ;
    END
  END prm[293]
  PIN prm[294]
    DIRECTION OUTPUT ;
    USE SIGNAL ;
    PORT
      LAYER M4 ;
        RECT  86.208 64.332 86.4 64.356 ;
    END
  END prm[294]
  PIN prm[295]
    DIRECTION OUTPUT ;
    USE SIGNAL ;
    PORT
      LAYER M4 ;
        RECT  86.208 64.524 86.4 64.548 ;
    END
  END prm[295]
  PIN prm[296]
    DIRECTION OUTPUT ;
    USE SIGNAL ;
    PORT
      LAYER M4 ;
        RECT  86.208 64.764 86.4 64.788 ;
    END
  END prm[296]
  PIN prm[297]
    DIRECTION OUTPUT ;
    USE SIGNAL ;
    PORT
      LAYER M4 ;
        RECT  86.208 64.956 86.4 64.98 ;
    END
  END prm[297]
  PIN prm[298]
    DIRECTION OUTPUT ;
    USE SIGNAL ;
    PORT
      LAYER M4 ;
        RECT  86.208 65.196 86.4 65.22 ;
    END
  END prm[298]
  PIN prm[299]
    DIRECTION OUTPUT ;
    USE SIGNAL ;
    PORT
      LAYER M4 ;
        RECT  86.208 65.388 86.4 65.412 ;
    END
  END prm[299]
  PIN prm[29]
    DIRECTION OUTPUT ;
    USE SIGNAL ;
    PORT
      LAYER M4 ;
        RECT  86.208 8.316 86.4 8.34 ;
    END
  END prm[29]
  PIN prm[2]
    DIRECTION OUTPUT ;
    USE SIGNAL ;
    PORT
      LAYER M4 ;
        RECT  86.208 2.604 86.4 2.628 ;
    END
  END prm[2]
  PIN prm[300]
    DIRECTION OUTPUT ;
    USE SIGNAL ;
    PORT
      LAYER M4 ;
        RECT  86.208 65.58 86.4 65.604 ;
    END
  END prm[300]
  PIN prm[301]
    DIRECTION OUTPUT ;
    USE SIGNAL ;
    PORT
      LAYER M4 ;
        RECT  86.208 65.82 86.4 65.844 ;
    END
  END prm[301]
  PIN prm[302]
    DIRECTION OUTPUT ;
    USE SIGNAL ;
    PORT
      LAYER M4 ;
        RECT  86.208 66.012 86.4 66.036 ;
    END
  END prm[302]
  PIN prm[303]
    DIRECTION OUTPUT ;
    USE SIGNAL ;
    PORT
      LAYER M4 ;
        RECT  86.208 66.252 86.4 66.276 ;
    END
  END prm[303]
  PIN prm[304]
    DIRECTION OUTPUT ;
    USE SIGNAL ;
    PORT
      LAYER M4 ;
        RECT  86.208 66.444 86.4 66.468 ;
    END
  END prm[304]
  PIN prm[305]
    DIRECTION OUTPUT ;
    USE SIGNAL ;
    PORT
      LAYER M4 ;
        RECT  86.208 66.636 86.4 66.66 ;
    END
  END prm[305]
  PIN prm[306]
    DIRECTION OUTPUT ;
    USE SIGNAL ;
    PORT
      LAYER M4 ;
        RECT  86.208 66.876 86.4 66.9 ;
    END
  END prm[306]
  PIN prm[307]
    DIRECTION OUTPUT ;
    USE SIGNAL ;
    PORT
      LAYER M4 ;
        RECT  86.208 67.068 86.4 67.092 ;
    END
  END prm[307]
  PIN prm[308]
    DIRECTION OUTPUT ;
    USE SIGNAL ;
    PORT
      LAYER M4 ;
        RECT  86.208 67.308 86.4 67.332 ;
    END
  END prm[308]
  PIN prm[309]
    DIRECTION OUTPUT ;
    USE SIGNAL ;
    PORT
      LAYER M4 ;
        RECT  86.208 67.5 86.4 67.524 ;
    END
  END prm[309]
  PIN prm[30]
    DIRECTION OUTPUT ;
    USE SIGNAL ;
    PORT
      LAYER M4 ;
        RECT  86.208 8.508 86.4 8.532 ;
    END
  END prm[30]
  PIN prm[310]
    DIRECTION OUTPUT ;
    USE SIGNAL ;
    PORT
      LAYER M4 ;
        RECT  86.208 67.692 86.4 67.716 ;
    END
  END prm[310]
  PIN prm[311]
    DIRECTION OUTPUT ;
    USE SIGNAL ;
    PORT
      LAYER M4 ;
        RECT  86.208 67.932 86.4 67.956 ;
    END
  END prm[311]
  PIN prm[312]
    DIRECTION OUTPUT ;
    USE SIGNAL ;
    PORT
      LAYER M4 ;
        RECT  86.208 68.124 86.4 68.148 ;
    END
  END prm[312]
  PIN prm[313]
    DIRECTION OUTPUT ;
    USE SIGNAL ;
    PORT
      LAYER M4 ;
        RECT  86.208 68.364 86.4 68.388 ;
    END
  END prm[313]
  PIN prm[314]
    DIRECTION OUTPUT ;
    USE SIGNAL ;
    PORT
      LAYER M4 ;
        RECT  86.208 68.556 86.4 68.58 ;
    END
  END prm[314]
  PIN prm[315]
    DIRECTION OUTPUT ;
    USE SIGNAL ;
    PORT
      LAYER M4 ;
        RECT  86.208 68.748 86.4 68.772 ;
    END
  END prm[315]
  PIN prm[316]
    DIRECTION OUTPUT ;
    USE SIGNAL ;
    PORT
      LAYER M4 ;
        RECT  86.208 68.988 86.4 69.012 ;
    END
  END prm[316]
  PIN prm[317]
    DIRECTION OUTPUT ;
    USE SIGNAL ;
    PORT
      LAYER M4 ;
        RECT  86.208 69.18 86.4 69.204 ;
    END
  END prm[317]
  PIN prm[318]
    DIRECTION OUTPUT ;
    USE SIGNAL ;
    PORT
      LAYER M4 ;
        RECT  86.208 69.42 86.4 69.444 ;
    END
  END prm[318]
  PIN prm[319]
    DIRECTION OUTPUT ;
    USE SIGNAL ;
    PORT
      LAYER M4 ;
        RECT  86.208 69.612 86.4 69.636 ;
    END
  END prm[319]
  PIN prm[31]
    DIRECTION OUTPUT ;
    USE SIGNAL ;
    PORT
      LAYER M4 ;
        RECT  86.208 8.748 86.4 8.772 ;
    END
  END prm[31]
  PIN prm[320]
    DIRECTION OUTPUT ;
    USE SIGNAL ;
    PORT
      LAYER M4 ;
        RECT  86.208 69.804 86.4 69.828 ;
    END
  END prm[320]
  PIN prm[321]
    DIRECTION OUTPUT ;
    USE SIGNAL ;
    PORT
      LAYER M4 ;
        RECT  86.208 70.044 86.4 70.068 ;
    END
  END prm[321]
  PIN prm[322]
    DIRECTION OUTPUT ;
    USE SIGNAL ;
    PORT
      LAYER M4 ;
        RECT  86.208 70.236 86.4 70.26 ;
    END
  END prm[322]
  PIN prm[323]
    DIRECTION OUTPUT ;
    USE SIGNAL ;
    PORT
      LAYER M4 ;
        RECT  86.208 70.476 86.4 70.5 ;
    END
  END prm[323]
  PIN prm[324]
    DIRECTION OUTPUT ;
    USE SIGNAL ;
    PORT
      LAYER M4 ;
        RECT  86.208 70.668 86.4 70.692 ;
    END
  END prm[324]
  PIN prm[325]
    DIRECTION OUTPUT ;
    USE SIGNAL ;
    PORT
      LAYER M4 ;
        RECT  86.208 70.908 86.4 70.932 ;
    END
  END prm[325]
  PIN prm[326]
    DIRECTION OUTPUT ;
    USE SIGNAL ;
    PORT
      LAYER M4 ;
        RECT  86.208 71.1 86.4 71.124 ;
    END
  END prm[326]
  PIN prm[327]
    DIRECTION OUTPUT ;
    USE SIGNAL ;
    PORT
      LAYER M4 ;
        RECT  86.208 71.292 86.4 71.316 ;
    END
  END prm[327]
  PIN prm[328]
    DIRECTION OUTPUT ;
    USE SIGNAL ;
    PORT
      LAYER M4 ;
        RECT  86.208 71.532 86.4 71.556 ;
    END
  END prm[328]
  PIN prm[329]
    DIRECTION OUTPUT ;
    USE SIGNAL ;
    PORT
      LAYER M4 ;
        RECT  86.208 71.724 86.4 71.748 ;
    END
  END prm[329]
  PIN prm[32]
    DIRECTION OUTPUT ;
    USE SIGNAL ;
    PORT
      LAYER M4 ;
        RECT  86.208 8.94 86.4 8.964 ;
    END
  END prm[32]
  PIN prm[330]
    DIRECTION OUTPUT ;
    USE SIGNAL ;
    PORT
      LAYER M4 ;
        RECT  86.208 71.964 86.4 71.988 ;
    END
  END prm[330]
  PIN prm[331]
    DIRECTION OUTPUT ;
    USE SIGNAL ;
    PORT
      LAYER M4 ;
        RECT  86.208 72.156 86.4 72.18 ;
    END
  END prm[331]
  PIN prm[332]
    DIRECTION OUTPUT ;
    USE SIGNAL ;
    PORT
      LAYER M4 ;
        RECT  86.208 72.348 86.4 72.372 ;
    END
  END prm[332]
  PIN prm[333]
    DIRECTION OUTPUT ;
    USE SIGNAL ;
    PORT
      LAYER M4 ;
        RECT  86.208 72.588 86.4 72.612 ;
    END
  END prm[333]
  PIN prm[334]
    DIRECTION OUTPUT ;
    USE SIGNAL ;
    PORT
      LAYER M4 ;
        RECT  86.208 72.78 86.4 72.804 ;
    END
  END prm[334]
  PIN prm[335]
    DIRECTION OUTPUT ;
    USE SIGNAL ;
    PORT
      LAYER M4 ;
        RECT  86.208 73.02 86.4 73.044 ;
    END
  END prm[335]
  PIN prm[336]
    DIRECTION OUTPUT ;
    USE SIGNAL ;
    PORT
      LAYER M4 ;
        RECT  86.208 73.212 86.4 73.236 ;
    END
  END prm[336]
  PIN prm[337]
    DIRECTION OUTPUT ;
    USE SIGNAL ;
    PORT
      LAYER M4 ;
        RECT  86.208 73.404 86.4 73.428 ;
    END
  END prm[337]
  PIN prm[338]
    DIRECTION OUTPUT ;
    USE SIGNAL ;
    PORT
      LAYER M4 ;
        RECT  86.208 73.644 86.4 73.668 ;
    END
  END prm[338]
  PIN prm[339]
    DIRECTION OUTPUT ;
    USE SIGNAL ;
    PORT
      LAYER M4 ;
        RECT  86.208 73.836 86.4 73.86 ;
    END
  END prm[339]
  PIN prm[33]
    DIRECTION OUTPUT ;
    USE SIGNAL ;
    PORT
      LAYER M4 ;
        RECT  86.208 9.132 86.4 9.156 ;
    END
  END prm[33]
  PIN prm[340]
    DIRECTION OUTPUT ;
    USE SIGNAL ;
    PORT
      LAYER M4 ;
        RECT  86.208 74.076 86.4 74.1 ;
    END
  END prm[340]
  PIN prm[341]
    DIRECTION OUTPUT ;
    USE SIGNAL ;
    PORT
      LAYER M4 ;
        RECT  86.208 74.268 86.4 74.292 ;
    END
  END prm[341]
  PIN prm[342]
    DIRECTION OUTPUT ;
    USE SIGNAL ;
    PORT
      LAYER M4 ;
        RECT  86.208 74.46 86.4 74.484 ;
    END
  END prm[342]
  PIN prm[343]
    DIRECTION OUTPUT ;
    USE SIGNAL ;
    PORT
      LAYER M4 ;
        RECT  86.208 74.7 86.4 74.724 ;
    END
  END prm[343]
  PIN prm[344]
    DIRECTION OUTPUT ;
    USE SIGNAL ;
    PORT
      LAYER M4 ;
        RECT  86.208 74.892 86.4 74.916 ;
    END
  END prm[344]
  PIN prm[345]
    DIRECTION OUTPUT ;
    USE SIGNAL ;
    PORT
      LAYER M4 ;
        RECT  86.208 75.132 86.4 75.156 ;
    END
  END prm[345]
  PIN prm[346]
    DIRECTION OUTPUT ;
    USE SIGNAL ;
    PORT
      LAYER M4 ;
        RECT  86.208 75.324 86.4 75.348 ;
    END
  END prm[346]
  PIN prm[347]
    DIRECTION OUTPUT ;
    USE SIGNAL ;
    PORT
      LAYER M4 ;
        RECT  86.208 75.516 86.4 75.54 ;
    END
  END prm[347]
  PIN prm[348]
    DIRECTION OUTPUT ;
    USE SIGNAL ;
    PORT
      LAYER M4 ;
        RECT  86.208 75.756 86.4 75.78 ;
    END
  END prm[348]
  PIN prm[349]
    DIRECTION OUTPUT ;
    USE SIGNAL ;
    PORT
      LAYER M4 ;
        RECT  86.208 75.948 86.4 75.972 ;
    END
  END prm[349]
  PIN prm[34]
    DIRECTION OUTPUT ;
    USE SIGNAL ;
    PORT
      LAYER M4 ;
        RECT  86.208 9.372 86.4 9.396 ;
    END
  END prm[34]
  PIN prm[350]
    DIRECTION OUTPUT ;
    USE SIGNAL ;
    PORT
      LAYER M4 ;
        RECT  86.208 76.188 86.4 76.212 ;
    END
  END prm[350]
  PIN prm[351]
    DIRECTION OUTPUT ;
    USE SIGNAL ;
    PORT
      LAYER M4 ;
        RECT  86.208 76.38 86.4 76.404 ;
    END
  END prm[351]
  PIN prm[352]
    DIRECTION OUTPUT ;
    USE SIGNAL ;
    PORT
      LAYER M4 ;
        RECT  86.208 76.572 86.4 76.596 ;
    END
  END prm[352]
  PIN prm[353]
    DIRECTION OUTPUT ;
    USE SIGNAL ;
    PORT
      LAYER M4 ;
        RECT  86.208 76.812 86.4 76.836 ;
    END
  END prm[353]
  PIN prm[354]
    DIRECTION OUTPUT ;
    USE SIGNAL ;
    PORT
      LAYER M4 ;
        RECT  86.208 77.004 86.4 77.028 ;
    END
  END prm[354]
  PIN prm[355]
    DIRECTION OUTPUT ;
    USE SIGNAL ;
    PORT
      LAYER M4 ;
        RECT  86.208 77.244 86.4 77.268 ;
    END
  END prm[355]
  PIN prm[356]
    DIRECTION OUTPUT ;
    USE SIGNAL ;
    PORT
      LAYER M4 ;
        RECT  86.208 77.436 86.4 77.46 ;
    END
  END prm[356]
  PIN prm[357]
    DIRECTION OUTPUT ;
    USE SIGNAL ;
    PORT
      LAYER M4 ;
        RECT  86.208 77.628 86.4 77.652 ;
    END
  END prm[357]
  PIN prm[358]
    DIRECTION OUTPUT ;
    USE SIGNAL ;
    PORT
      LAYER M4 ;
        RECT  86.208 77.868 86.4 77.892 ;
    END
  END prm[358]
  PIN prm[359]
    DIRECTION OUTPUT ;
    USE SIGNAL ;
    PORT
      LAYER M4 ;
        RECT  86.208 78.06 86.4 78.084 ;
    END
  END prm[359]
  PIN prm[35]
    DIRECTION OUTPUT ;
    USE SIGNAL ;
    PORT
      LAYER M4 ;
        RECT  86.208 9.564 86.4 9.588 ;
    END
  END prm[35]
  PIN prm[360]
    DIRECTION OUTPUT ;
    USE SIGNAL ;
    PORT
      LAYER M4 ;
        RECT  86.208 78.3 86.4 78.324 ;
    END
  END prm[360]
  PIN prm[361]
    DIRECTION OUTPUT ;
    USE SIGNAL ;
    PORT
      LAYER M4 ;
        RECT  86.208 78.492 86.4 78.516 ;
    END
  END prm[361]
  PIN prm[362]
    DIRECTION OUTPUT ;
    USE SIGNAL ;
    PORT
      LAYER M4 ;
        RECT  86.208 78.684 86.4 78.708 ;
    END
  END prm[362]
  PIN prm[363]
    DIRECTION OUTPUT ;
    USE SIGNAL ;
    PORT
      LAYER M4 ;
        RECT  86.208 78.924 86.4 78.948 ;
    END
  END prm[363]
  PIN prm[364]
    DIRECTION OUTPUT ;
    USE SIGNAL ;
    PORT
      LAYER M4 ;
        RECT  86.208 79.116 86.4 79.14 ;
    END
  END prm[364]
  PIN prm[365]
    DIRECTION OUTPUT ;
    USE SIGNAL ;
    PORT
      LAYER M4 ;
        RECT  86.208 79.356 86.4 79.38 ;
    END
  END prm[365]
  PIN prm[366]
    DIRECTION OUTPUT ;
    USE SIGNAL ;
    PORT
      LAYER M4 ;
        RECT  86.208 79.548 86.4 79.572 ;
    END
  END prm[366]
  PIN prm[367]
    DIRECTION OUTPUT ;
    USE SIGNAL ;
    PORT
      LAYER M4 ;
        RECT  86.208 79.788 86.4 79.812 ;
    END
  END prm[367]
  PIN prm[368]
    DIRECTION OUTPUT ;
    USE SIGNAL ;
    PORT
      LAYER M4 ;
        RECT  86.208 79.98 86.4 80.004 ;
    END
  END prm[368]
  PIN prm[369]
    DIRECTION OUTPUT ;
    USE SIGNAL ;
    PORT
      LAYER M4 ;
        RECT  86.208 80.172 86.4 80.196 ;
    END
  END prm[369]
  PIN prm[36]
    DIRECTION OUTPUT ;
    USE SIGNAL ;
    PORT
      LAYER M4 ;
        RECT  86.208 9.804 86.4 9.828 ;
    END
  END prm[36]
  PIN prm[370]
    DIRECTION OUTPUT ;
    USE SIGNAL ;
    PORT
      LAYER M4 ;
        RECT  86.208 80.412 86.4 80.436 ;
    END
  END prm[370]
  PIN prm[371]
    DIRECTION OUTPUT ;
    USE SIGNAL ;
    PORT
      LAYER M4 ;
        RECT  86.208 80.604 86.4 80.628 ;
    END
  END prm[371]
  PIN prm[372]
    DIRECTION OUTPUT ;
    USE SIGNAL ;
    PORT
      LAYER M4 ;
        RECT  86.208 80.844 86.4 80.868 ;
    END
  END prm[372]
  PIN prm[373]
    DIRECTION OUTPUT ;
    USE SIGNAL ;
    PORT
      LAYER M4 ;
        RECT  86.208 81.036 86.4 81.06 ;
    END
  END prm[373]
  PIN prm[374]
    DIRECTION OUTPUT ;
    USE SIGNAL ;
    PORT
      LAYER M4 ;
        RECT  86.208 81.228 86.4 81.252 ;
    END
  END prm[374]
  PIN prm[375]
    DIRECTION OUTPUT ;
    USE SIGNAL ;
    PORT
      LAYER M4 ;
        RECT  86.208 81.468 86.4 81.492 ;
    END
  END prm[375]
  PIN prm[376]
    DIRECTION OUTPUT ;
    USE SIGNAL ;
    PORT
      LAYER M4 ;
        RECT  86.208 81.66 86.4 81.684 ;
    END
  END prm[376]
  PIN prm[377]
    DIRECTION OUTPUT ;
    USE SIGNAL ;
    PORT
      LAYER M4 ;
        RECT  86.208 81.9 86.4 81.924 ;
    END
  END prm[377]
  PIN prm[378]
    DIRECTION OUTPUT ;
    USE SIGNAL ;
    PORT
      LAYER M4 ;
        RECT  86.208 82.092 86.4 82.116 ;
    END
  END prm[378]
  PIN prm[379]
    DIRECTION OUTPUT ;
    USE SIGNAL ;
    PORT
      LAYER M4 ;
        RECT  86.208 82.284 86.4 82.308 ;
    END
  END prm[379]
  PIN prm[37]
    DIRECTION OUTPUT ;
    USE SIGNAL ;
    PORT
      LAYER M4 ;
        RECT  86.208 9.996 86.4 10.02 ;
    END
  END prm[37]
  PIN prm[380]
    DIRECTION OUTPUT ;
    USE SIGNAL ;
    PORT
      LAYER M4 ;
        RECT  86.208 82.524 86.4 82.548 ;
    END
  END prm[380]
  PIN prm[381]
    DIRECTION OUTPUT ;
    USE SIGNAL ;
    PORT
      LAYER M4 ;
        RECT  86.208 82.716 86.4 82.74 ;
    END
  END prm[381]
  PIN prm[382]
    DIRECTION OUTPUT ;
    USE SIGNAL ;
    PORT
      LAYER M4 ;
        RECT  86.208 82.956 86.4 82.98 ;
    END
  END prm[382]
  PIN prm[383]
    DIRECTION OUTPUT ;
    USE SIGNAL ;
    PORT
      LAYER M4 ;
        RECT  86.208 83.148 86.4 83.172 ;
    END
  END prm[383]
  PIN prm[384]
    DIRECTION OUTPUT ;
    USE SIGNAL ;
    PORT
      LAYER M4 ;
        RECT  86.208 83.34 86.4 83.364 ;
    END
  END prm[384]
  PIN prm[385]
    DIRECTION OUTPUT ;
    USE SIGNAL ;
    PORT
      LAYER M4 ;
        RECT  86.208 83.58 86.4 83.604 ;
    END
  END prm[385]
  PIN prm[386]
    DIRECTION OUTPUT ;
    USE SIGNAL ;
    PORT
      LAYER M4 ;
        RECT  86.208 83.772 86.4 83.796 ;
    END
  END prm[386]
  PIN prm[387]
    DIRECTION OUTPUT ;
    USE SIGNAL ;
    PORT
      LAYER M4 ;
        RECT  86.208 84.012 86.4 84.036 ;
    END
  END prm[387]
  PIN prm[388]
    DIRECTION OUTPUT ;
    USE SIGNAL ;
    PORT
      LAYER M4 ;
        RECT  86.208 84.204 86.4 84.228 ;
    END
  END prm[388]
  PIN prm[389]
    DIRECTION OUTPUT ;
    USE SIGNAL ;
    PORT
      LAYER M5 ;
        RECT  2.172 0 2.196 0.192 ;
    END
  END prm[389]
  PIN prm[38]
    DIRECTION OUTPUT ;
    USE SIGNAL ;
    PORT
      LAYER M4 ;
        RECT  86.208 10.188 86.4 10.212 ;
    END
  END prm[38]
  PIN prm[390]
    DIRECTION OUTPUT ;
    USE SIGNAL ;
    PORT
      LAYER M5 ;
        RECT  2.364 0 2.388 0.192 ;
    END
  END prm[390]
  PIN prm[391]
    DIRECTION OUTPUT ;
    USE SIGNAL ;
    PORT
      LAYER M5 ;
        RECT  2.604 0 2.628 0.192 ;
    END
  END prm[391]
  PIN prm[392]
    DIRECTION OUTPUT ;
    USE SIGNAL ;
    PORT
      LAYER M5 ;
        RECT  2.796 0 2.82 0.192 ;
    END
  END prm[392]
  PIN prm[393]
    DIRECTION OUTPUT ;
    USE SIGNAL ;
    PORT
      LAYER M5 ;
        RECT  2.988 0 3.012 0.192 ;
    END
  END prm[393]
  PIN prm[394]
    DIRECTION OUTPUT ;
    USE SIGNAL ;
    PORT
      LAYER M5 ;
        RECT  3.228 0 3.252 0.192 ;
    END
  END prm[394]
  PIN prm[395]
    DIRECTION OUTPUT ;
    USE SIGNAL ;
    PORT
      LAYER M5 ;
        RECT  3.42 0 3.444 0.192 ;
    END
  END prm[395]
  PIN prm[396]
    DIRECTION OUTPUT ;
    USE SIGNAL ;
    PORT
      LAYER M5 ;
        RECT  3.66 0 3.684 0.192 ;
    END
  END prm[396]
  PIN prm[397]
    DIRECTION OUTPUT ;
    USE SIGNAL ;
    PORT
      LAYER M5 ;
        RECT  3.852 0 3.876 0.192 ;
    END
  END prm[397]
  PIN prm[398]
    DIRECTION OUTPUT ;
    USE SIGNAL ;
    PORT
      LAYER M5 ;
        RECT  4.044 0 4.068 0.192 ;
    END
  END prm[398]
  PIN prm[399]
    DIRECTION OUTPUT ;
    USE SIGNAL ;
    PORT
      LAYER M5 ;
        RECT  4.284 0 4.308 0.192 ;
    END
  END prm[399]
  PIN prm[39]
    DIRECTION OUTPUT ;
    USE SIGNAL ;
    PORT
      LAYER M4 ;
        RECT  86.208 10.428 86.4 10.452 ;
    END
  END prm[39]
  PIN prm[3]
    DIRECTION OUTPUT ;
    USE SIGNAL ;
    PORT
      LAYER M4 ;
        RECT  86.208 2.796 86.4 2.82 ;
    END
  END prm[3]
  PIN prm[400]
    DIRECTION OUTPUT ;
    USE SIGNAL ;
    PORT
      LAYER M5 ;
        RECT  4.476 0 4.5 0.192 ;
    END
  END prm[400]
  PIN prm[401]
    DIRECTION OUTPUT ;
    USE SIGNAL ;
    PORT
      LAYER M5 ;
        RECT  4.668 0 4.692 0.192 ;
    END
  END prm[401]
  PIN prm[402]
    DIRECTION OUTPUT ;
    USE SIGNAL ;
    PORT
      LAYER M5 ;
        RECT  4.908 0 4.932 0.192 ;
    END
  END prm[402]
  PIN prm[403]
    DIRECTION OUTPUT ;
    USE SIGNAL ;
    PORT
      LAYER M5 ;
        RECT  5.1 0 5.124 0.192 ;
    END
  END prm[403]
  PIN prm[404]
    DIRECTION OUTPUT ;
    USE SIGNAL ;
    PORT
      LAYER M5 ;
        RECT  5.34 0 5.364 0.192 ;
    END
  END prm[404]
  PIN prm[405]
    DIRECTION OUTPUT ;
    USE SIGNAL ;
    PORT
      LAYER M5 ;
        RECT  5.532 0 5.556 0.192 ;
    END
  END prm[405]
  PIN prm[406]
    DIRECTION OUTPUT ;
    USE SIGNAL ;
    PORT
      LAYER M5 ;
        RECT  5.724 0 5.748 0.192 ;
    END
  END prm[406]
  PIN prm[407]
    DIRECTION OUTPUT ;
    USE SIGNAL ;
    PORT
      LAYER M5 ;
        RECT  5.964 0 5.988 0.192 ;
    END
  END prm[407]
  PIN prm[408]
    DIRECTION OUTPUT ;
    USE SIGNAL ;
    PORT
      LAYER M5 ;
        RECT  6.156 0 6.18 0.192 ;
    END
  END prm[408]
  PIN prm[409]
    DIRECTION OUTPUT ;
    USE SIGNAL ;
    PORT
      LAYER M5 ;
        RECT  6.348 0 6.372 0.192 ;
    END
  END prm[409]
  PIN prm[40]
    DIRECTION OUTPUT ;
    USE SIGNAL ;
    PORT
      LAYER M4 ;
        RECT  86.208 10.62 86.4 10.644 ;
    END
  END prm[40]
  PIN prm[410]
    DIRECTION OUTPUT ;
    USE SIGNAL ;
    PORT
      LAYER M5 ;
        RECT  6.588 0 6.612 0.192 ;
    END
  END prm[410]
  PIN prm[411]
    DIRECTION OUTPUT ;
    USE SIGNAL ;
    PORT
      LAYER M5 ;
        RECT  6.78 0 6.804 0.192 ;
    END
  END prm[411]
  PIN prm[412]
    DIRECTION OUTPUT ;
    USE SIGNAL ;
    PORT
      LAYER M5 ;
        RECT  7.02 0 7.044 0.192 ;
    END
  END prm[412]
  PIN prm[413]
    DIRECTION OUTPUT ;
    USE SIGNAL ;
    PORT
      LAYER M5 ;
        RECT  7.212 0 7.236 0.192 ;
    END
  END prm[413]
  PIN prm[414]
    DIRECTION OUTPUT ;
    USE SIGNAL ;
    PORT
      LAYER M5 ;
        RECT  7.404 0 7.428 0.192 ;
    END
  END prm[414]
  PIN prm[415]
    DIRECTION OUTPUT ;
    USE SIGNAL ;
    PORT
      LAYER M5 ;
        RECT  7.644 0 7.668 0.192 ;
    END
  END prm[415]
  PIN prm[416]
    DIRECTION OUTPUT ;
    USE SIGNAL ;
    PORT
      LAYER M5 ;
        RECT  7.836 0 7.86 0.192 ;
    END
  END prm[416]
  PIN prm[417]
    DIRECTION OUTPUT ;
    USE SIGNAL ;
    PORT
      LAYER M5 ;
        RECT  8.028 0 8.052 0.192 ;
    END
  END prm[417]
  PIN prm[418]
    DIRECTION OUTPUT ;
    USE SIGNAL ;
    PORT
      LAYER M5 ;
        RECT  8.268 0 8.292 0.192 ;
    END
  END prm[418]
  PIN prm[419]
    DIRECTION OUTPUT ;
    USE SIGNAL ;
    PORT
      LAYER M5 ;
        RECT  8.46 0 8.484 0.192 ;
    END
  END prm[419]
  PIN prm[41]
    DIRECTION OUTPUT ;
    USE SIGNAL ;
    PORT
      LAYER M4 ;
        RECT  86.208 10.86 86.4 10.884 ;
    END
  END prm[41]
  PIN prm[420]
    DIRECTION OUTPUT ;
    USE SIGNAL ;
    PORT
      LAYER M5 ;
        RECT  8.652 0 8.676 0.192 ;
    END
  END prm[420]
  PIN prm[421]
    DIRECTION OUTPUT ;
    USE SIGNAL ;
    PORT
      LAYER M5 ;
        RECT  8.892 0 8.916 0.192 ;
    END
  END prm[421]
  PIN prm[422]
    DIRECTION OUTPUT ;
    USE SIGNAL ;
    PORT
      LAYER M5 ;
        RECT  9.084 0 9.108 0.192 ;
    END
  END prm[422]
  PIN prm[423]
    DIRECTION OUTPUT ;
    USE SIGNAL ;
    PORT
      LAYER M5 ;
        RECT  9.324 0 9.348 0.192 ;
    END
  END prm[423]
  PIN prm[424]
    DIRECTION OUTPUT ;
    USE SIGNAL ;
    PORT
      LAYER M5 ;
        RECT  9.516 0 9.54 0.192 ;
    END
  END prm[424]
  PIN prm[425]
    DIRECTION OUTPUT ;
    USE SIGNAL ;
    PORT
      LAYER M5 ;
        RECT  9.708 0 9.732 0.192 ;
    END
  END prm[425]
  PIN prm[426]
    DIRECTION OUTPUT ;
    USE SIGNAL ;
    PORT
      LAYER M5 ;
        RECT  9.948 0 9.972 0.192 ;
    END
  END prm[426]
  PIN prm[427]
    DIRECTION OUTPUT ;
    USE SIGNAL ;
    PORT
      LAYER M5 ;
        RECT  10.14 0 10.164 0.192 ;
    END
  END prm[427]
  PIN prm[428]
    DIRECTION OUTPUT ;
    USE SIGNAL ;
    PORT
      LAYER M5 ;
        RECT  10.332 0 10.356 0.192 ;
    END
  END prm[428]
  PIN prm[429]
    DIRECTION OUTPUT ;
    USE SIGNAL ;
    PORT
      LAYER M5 ;
        RECT  10.572 0 10.596 0.192 ;
    END
  END prm[429]
  PIN prm[42]
    DIRECTION OUTPUT ;
    USE SIGNAL ;
    PORT
      LAYER M4 ;
        RECT  86.208 11.052 86.4 11.076 ;
    END
  END prm[42]
  PIN prm[430]
    DIRECTION OUTPUT ;
    USE SIGNAL ;
    PORT
      LAYER M5 ;
        RECT  10.764 0 10.788 0.192 ;
    END
  END prm[430]
  PIN prm[431]
    DIRECTION OUTPUT ;
    USE SIGNAL ;
    PORT
      LAYER M5 ;
        RECT  11.004 0 11.028 0.192 ;
    END
  END prm[431]
  PIN prm[432]
    DIRECTION OUTPUT ;
    USE SIGNAL ;
    PORT
      LAYER M5 ;
        RECT  11.196 0 11.22 0.192 ;
    END
  END prm[432]
  PIN prm[433]
    DIRECTION OUTPUT ;
    USE SIGNAL ;
    PORT
      LAYER M5 ;
        RECT  11.388 0 11.412 0.192 ;
    END
  END prm[433]
  PIN prm[434]
    DIRECTION OUTPUT ;
    USE SIGNAL ;
    PORT
      LAYER M5 ;
        RECT  11.628 0 11.652 0.192 ;
    END
  END prm[434]
  PIN prm[435]
    DIRECTION OUTPUT ;
    USE SIGNAL ;
    PORT
      LAYER M5 ;
        RECT  11.82 0 11.844 0.192 ;
    END
  END prm[435]
  PIN prm[436]
    DIRECTION OUTPUT ;
    USE SIGNAL ;
    PORT
      LAYER M5 ;
        RECT  12.012 0 12.036 0.192 ;
    END
  END prm[436]
  PIN prm[437]
    DIRECTION OUTPUT ;
    USE SIGNAL ;
    PORT
      LAYER M5 ;
        RECT  12.252 0 12.276 0.192 ;
    END
  END prm[437]
  PIN prm[438]
    DIRECTION OUTPUT ;
    USE SIGNAL ;
    PORT
      LAYER M5 ;
        RECT  12.444 0 12.468 0.192 ;
    END
  END prm[438]
  PIN prm[439]
    DIRECTION OUTPUT ;
    USE SIGNAL ;
    PORT
      LAYER M5 ;
        RECT  12.684 0 12.708 0.192 ;
    END
  END prm[439]
  PIN prm[43]
    DIRECTION OUTPUT ;
    USE SIGNAL ;
    PORT
      LAYER M4 ;
        RECT  86.208 11.244 86.4 11.268 ;
    END
  END prm[43]
  PIN prm[440]
    DIRECTION OUTPUT ;
    USE SIGNAL ;
    PORT
      LAYER M5 ;
        RECT  12.876 0 12.9 0.192 ;
    END
  END prm[440]
  PIN prm[441]
    DIRECTION OUTPUT ;
    USE SIGNAL ;
    PORT
      LAYER M5 ;
        RECT  13.068 0 13.092 0.192 ;
    END
  END prm[441]
  PIN prm[442]
    DIRECTION OUTPUT ;
    USE SIGNAL ;
    PORT
      LAYER M5 ;
        RECT  13.308 0 13.332 0.192 ;
    END
  END prm[442]
  PIN prm[443]
    DIRECTION OUTPUT ;
    USE SIGNAL ;
    PORT
      LAYER M5 ;
        RECT  13.5 0 13.524 0.192 ;
    END
  END prm[443]
  PIN prm[444]
    DIRECTION OUTPUT ;
    USE SIGNAL ;
    PORT
      LAYER M5 ;
        RECT  13.692 0 13.716 0.192 ;
    END
  END prm[444]
  PIN prm[445]
    DIRECTION OUTPUT ;
    USE SIGNAL ;
    PORT
      LAYER M5 ;
        RECT  13.932 0 13.956 0.192 ;
    END
  END prm[445]
  PIN prm[446]
    DIRECTION OUTPUT ;
    USE SIGNAL ;
    PORT
      LAYER M5 ;
        RECT  14.124 0 14.148 0.192 ;
    END
  END prm[446]
  PIN prm[447]
    DIRECTION OUTPUT ;
    USE SIGNAL ;
    PORT
      LAYER M5 ;
        RECT  14.364 0 14.388 0.192 ;
    END
  END prm[447]
  PIN prm[448]
    DIRECTION OUTPUT ;
    USE SIGNAL ;
    PORT
      LAYER M5 ;
        RECT  14.556 0 14.58 0.192 ;
    END
  END prm[448]
  PIN prm[449]
    DIRECTION OUTPUT ;
    USE SIGNAL ;
    PORT
      LAYER M5 ;
        RECT  14.748 0 14.772 0.192 ;
    END
  END prm[449]
  PIN prm[44]
    DIRECTION OUTPUT ;
    USE SIGNAL ;
    PORT
      LAYER M4 ;
        RECT  86.208 11.484 86.4 11.508 ;
    END
  END prm[44]
  PIN prm[450]
    DIRECTION OUTPUT ;
    USE SIGNAL ;
    PORT
      LAYER M5 ;
        RECT  14.988 0 15.012 0.192 ;
    END
  END prm[450]
  PIN prm[451]
    DIRECTION OUTPUT ;
    USE SIGNAL ;
    PORT
      LAYER M5 ;
        RECT  15.18 0 15.204 0.192 ;
    END
  END prm[451]
  PIN prm[452]
    DIRECTION OUTPUT ;
    USE SIGNAL ;
    PORT
      LAYER M5 ;
        RECT  15.372 0 15.396 0.192 ;
    END
  END prm[452]
  PIN prm[453]
    DIRECTION OUTPUT ;
    USE SIGNAL ;
    PORT
      LAYER M5 ;
        RECT  15.612 0 15.636 0.192 ;
    END
  END prm[453]
  PIN prm[454]
    DIRECTION OUTPUT ;
    USE SIGNAL ;
    PORT
      LAYER M5 ;
        RECT  15.804 0 15.828 0.192 ;
    END
  END prm[454]
  PIN prm[455]
    DIRECTION OUTPUT ;
    USE SIGNAL ;
    PORT
      LAYER M5 ;
        RECT  15.996 0 16.02 0.192 ;
    END
  END prm[455]
  PIN prm[456]
    DIRECTION OUTPUT ;
    USE SIGNAL ;
    PORT
      LAYER M5 ;
        RECT  16.236 0 16.26 0.192 ;
    END
  END prm[456]
  PIN prm[457]
    DIRECTION OUTPUT ;
    USE SIGNAL ;
    PORT
      LAYER M5 ;
        RECT  16.428 0 16.452 0.192 ;
    END
  END prm[457]
  PIN prm[458]
    DIRECTION OUTPUT ;
    USE SIGNAL ;
    PORT
      LAYER M5 ;
        RECT  16.668 0 16.692 0.192 ;
    END
  END prm[458]
  PIN prm[459]
    DIRECTION OUTPUT ;
    USE SIGNAL ;
    PORT
      LAYER M5 ;
        RECT  16.86 0 16.884 0.192 ;
    END
  END prm[459]
  PIN prm[45]
    DIRECTION OUTPUT ;
    USE SIGNAL ;
    PORT
      LAYER M4 ;
        RECT  86.208 11.676 86.4 11.7 ;
    END
  END prm[45]
  PIN prm[460]
    DIRECTION OUTPUT ;
    USE SIGNAL ;
    PORT
      LAYER M5 ;
        RECT  17.052 0 17.076 0.192 ;
    END
  END prm[460]
  PIN prm[461]
    DIRECTION OUTPUT ;
    USE SIGNAL ;
    PORT
      LAYER M5 ;
        RECT  17.292 0 17.316 0.192 ;
    END
  END prm[461]
  PIN prm[462]
    DIRECTION OUTPUT ;
    USE SIGNAL ;
    PORT
      LAYER M5 ;
        RECT  17.484 0 17.508 0.192 ;
    END
  END prm[462]
  PIN prm[463]
    DIRECTION OUTPUT ;
    USE SIGNAL ;
    PORT
      LAYER M5 ;
        RECT  17.676 0 17.7 0.192 ;
    END
  END prm[463]
  PIN prm[464]
    DIRECTION OUTPUT ;
    USE SIGNAL ;
    PORT
      LAYER M5 ;
        RECT  17.916 0 17.94 0.192 ;
    END
  END prm[464]
  PIN prm[465]
    DIRECTION OUTPUT ;
    USE SIGNAL ;
    PORT
      LAYER M5 ;
        RECT  18.108 0 18.132 0.192 ;
    END
  END prm[465]
  PIN prm[466]
    DIRECTION OUTPUT ;
    USE SIGNAL ;
    PORT
      LAYER M5 ;
        RECT  18.348 0 18.372 0.192 ;
    END
  END prm[466]
  PIN prm[467]
    DIRECTION OUTPUT ;
    USE SIGNAL ;
    PORT
      LAYER M5 ;
        RECT  18.54 0 18.564 0.192 ;
    END
  END prm[467]
  PIN prm[468]
    DIRECTION OUTPUT ;
    USE SIGNAL ;
    PORT
      LAYER M5 ;
        RECT  18.732 0 18.756 0.192 ;
    END
  END prm[468]
  PIN prm[469]
    DIRECTION OUTPUT ;
    USE SIGNAL ;
    PORT
      LAYER M5 ;
        RECT  18.972 0 18.996 0.192 ;
    END
  END prm[469]
  PIN prm[46]
    DIRECTION OUTPUT ;
    USE SIGNAL ;
    PORT
      LAYER M4 ;
        RECT  86.208 11.916 86.4 11.94 ;
    END
  END prm[46]
  PIN prm[470]
    DIRECTION OUTPUT ;
    USE SIGNAL ;
    PORT
      LAYER M5 ;
        RECT  19.164 0 19.188 0.192 ;
    END
  END prm[470]
  PIN prm[471]
    DIRECTION OUTPUT ;
    USE SIGNAL ;
    PORT
      LAYER M5 ;
        RECT  19.356 0 19.38 0.192 ;
    END
  END prm[471]
  PIN prm[472]
    DIRECTION OUTPUT ;
    USE SIGNAL ;
    PORT
      LAYER M5 ;
        RECT  19.596 0 19.62 0.192 ;
    END
  END prm[472]
  PIN prm[473]
    DIRECTION OUTPUT ;
    USE SIGNAL ;
    PORT
      LAYER M5 ;
        RECT  19.788 0 19.812 0.192 ;
    END
  END prm[473]
  PIN prm[474]
    DIRECTION OUTPUT ;
    USE SIGNAL ;
    PORT
      LAYER M5 ;
        RECT  20.028 0 20.052 0.192 ;
    END
  END prm[474]
  PIN prm[475]
    DIRECTION OUTPUT ;
    USE SIGNAL ;
    PORT
      LAYER M5 ;
        RECT  20.22 0 20.244 0.192 ;
    END
  END prm[475]
  PIN prm[476]
    DIRECTION OUTPUT ;
    USE SIGNAL ;
    PORT
      LAYER M5 ;
        RECT  20.412 0 20.436 0.192 ;
    END
  END prm[476]
  PIN prm[477]
    DIRECTION OUTPUT ;
    USE SIGNAL ;
    PORT
      LAYER M5 ;
        RECT  20.652 0 20.676 0.192 ;
    END
  END prm[477]
  PIN prm[478]
    DIRECTION OUTPUT ;
    USE SIGNAL ;
    PORT
      LAYER M5 ;
        RECT  20.844 0 20.868 0.192 ;
    END
  END prm[478]
  PIN prm[479]
    DIRECTION OUTPUT ;
    USE SIGNAL ;
    PORT
      LAYER M5 ;
        RECT  21.036 0 21.06 0.192 ;
    END
  END prm[479]
  PIN prm[47]
    DIRECTION OUTPUT ;
    USE SIGNAL ;
    PORT
      LAYER M4 ;
        RECT  86.208 12.108 86.4 12.132 ;
    END
  END prm[47]
  PIN prm[480]
    DIRECTION OUTPUT ;
    USE SIGNAL ;
    PORT
      LAYER M5 ;
        RECT  21.276 0 21.3 0.192 ;
    END
  END prm[480]
  PIN prm[481]
    DIRECTION OUTPUT ;
    USE SIGNAL ;
    PORT
      LAYER M5 ;
        RECT  21.468 0 21.492 0.192 ;
    END
  END prm[481]
  PIN prm[482]
    DIRECTION OUTPUT ;
    USE SIGNAL ;
    PORT
      LAYER M5 ;
        RECT  21.66 0 21.684 0.192 ;
    END
  END prm[482]
  PIN prm[483]
    DIRECTION OUTPUT ;
    USE SIGNAL ;
    PORT
      LAYER M5 ;
        RECT  21.9 0 21.924 0.192 ;
    END
  END prm[483]
  PIN prm[484]
    DIRECTION OUTPUT ;
    USE SIGNAL ;
    PORT
      LAYER M5 ;
        RECT  22.092 0 22.116 0.192 ;
    END
  END prm[484]
  PIN prm[485]
    DIRECTION OUTPUT ;
    USE SIGNAL ;
    PORT
      LAYER M5 ;
        RECT  22.332 0 22.356 0.192 ;
    END
  END prm[485]
  PIN prm[486]
    DIRECTION OUTPUT ;
    USE SIGNAL ;
    PORT
      LAYER M5 ;
        RECT  22.524 0 22.548 0.192 ;
    END
  END prm[486]
  PIN prm[487]
    DIRECTION OUTPUT ;
    USE SIGNAL ;
    PORT
      LAYER M5 ;
        RECT  22.716 0 22.74 0.192 ;
    END
  END prm[487]
  PIN prm[488]
    DIRECTION OUTPUT ;
    USE SIGNAL ;
    PORT
      LAYER M5 ;
        RECT  22.956 0 22.98 0.192 ;
    END
  END prm[488]
  PIN prm[489]
    DIRECTION OUTPUT ;
    USE SIGNAL ;
    PORT
      LAYER M5 ;
        RECT  23.148 0 23.172 0.192 ;
    END
  END prm[489]
  PIN prm[48]
    DIRECTION OUTPUT ;
    USE SIGNAL ;
    PORT
      LAYER M4 ;
        RECT  86.208 12.3 86.4 12.324 ;
    END
  END prm[48]
  PIN prm[490]
    DIRECTION OUTPUT ;
    USE SIGNAL ;
    PORT
      LAYER M5 ;
        RECT  23.34 0 23.364 0.192 ;
    END
  END prm[490]
  PIN prm[491]
    DIRECTION OUTPUT ;
    USE SIGNAL ;
    PORT
      LAYER M5 ;
        RECT  23.58 0 23.604 0.192 ;
    END
  END prm[491]
  PIN prm[492]
    DIRECTION OUTPUT ;
    USE SIGNAL ;
    PORT
      LAYER M5 ;
        RECT  23.772 0 23.796 0.192 ;
    END
  END prm[492]
  PIN prm[493]
    DIRECTION OUTPUT ;
    USE SIGNAL ;
    PORT
      LAYER M5 ;
        RECT  24.012 0 24.036 0.192 ;
    END
  END prm[493]
  PIN prm[494]
    DIRECTION OUTPUT ;
    USE SIGNAL ;
    PORT
      LAYER M5 ;
        RECT  24.204 0 24.228 0.192 ;
    END
  END prm[494]
  PIN prm[495]
    DIRECTION OUTPUT ;
    USE SIGNAL ;
    PORT
      LAYER M5 ;
        RECT  24.396 0 24.42 0.192 ;
    END
  END prm[495]
  PIN prm[496]
    DIRECTION OUTPUT ;
    USE SIGNAL ;
    PORT
      LAYER M5 ;
        RECT  24.636 0 24.66 0.192 ;
    END
  END prm[496]
  PIN prm[497]
    DIRECTION OUTPUT ;
    USE SIGNAL ;
    PORT
      LAYER M5 ;
        RECT  24.828 0 24.852 0.192 ;
    END
  END prm[497]
  PIN prm[498]
    DIRECTION OUTPUT ;
    USE SIGNAL ;
    PORT
      LAYER M5 ;
        RECT  25.02 0 25.044 0.192 ;
    END
  END prm[498]
  PIN prm[499]
    DIRECTION OUTPUT ;
    USE SIGNAL ;
    PORT
      LAYER M5 ;
        RECT  25.26 0 25.284 0.192 ;
    END
  END prm[499]
  PIN prm[49]
    DIRECTION OUTPUT ;
    USE SIGNAL ;
    PORT
      LAYER M4 ;
        RECT  86.208 12.54 86.4 12.564 ;
    END
  END prm[49]
  PIN prm[4]
    DIRECTION OUTPUT ;
    USE SIGNAL ;
    PORT
      LAYER M4 ;
        RECT  86.208 3.036 86.4 3.06 ;
    END
  END prm[4]
  PIN prm[500]
    DIRECTION OUTPUT ;
    USE SIGNAL ;
    PORT
      LAYER M5 ;
        RECT  25.452 0 25.476 0.192 ;
    END
  END prm[500]
  PIN prm[501]
    DIRECTION OUTPUT ;
    USE SIGNAL ;
    PORT
      LAYER M5 ;
        RECT  25.692 0 25.716 0.192 ;
    END
  END prm[501]
  PIN prm[502]
    DIRECTION OUTPUT ;
    USE SIGNAL ;
    PORT
      LAYER M5 ;
        RECT  25.884 0 25.908 0.192 ;
    END
  END prm[502]
  PIN prm[503]
    DIRECTION OUTPUT ;
    USE SIGNAL ;
    PORT
      LAYER M5 ;
        RECT  26.076 0 26.1 0.192 ;
    END
  END prm[503]
  PIN prm[504]
    DIRECTION OUTPUT ;
    USE SIGNAL ;
    PORT
      LAYER M5 ;
        RECT  26.316 0 26.34 0.192 ;
    END
  END prm[504]
  PIN prm[505]
    DIRECTION OUTPUT ;
    USE SIGNAL ;
    PORT
      LAYER M5 ;
        RECT  26.508 0 26.532 0.192 ;
    END
  END prm[505]
  PIN prm[506]
    DIRECTION OUTPUT ;
    USE SIGNAL ;
    PORT
      LAYER M5 ;
        RECT  26.7 0 26.724 0.192 ;
    END
  END prm[506]
  PIN prm[507]
    DIRECTION OUTPUT ;
    USE SIGNAL ;
    PORT
      LAYER M5 ;
        RECT  26.94 0 26.964 0.192 ;
    END
  END prm[507]
  PIN prm[508]
    DIRECTION OUTPUT ;
    USE SIGNAL ;
    PORT
      LAYER M5 ;
        RECT  27.132 0 27.156 0.192 ;
    END
  END prm[508]
  PIN prm[509]
    DIRECTION OUTPUT ;
    USE SIGNAL ;
    PORT
      LAYER M5 ;
        RECT  27.372 0 27.396 0.192 ;
    END
  END prm[509]
  PIN prm[50]
    DIRECTION OUTPUT ;
    USE SIGNAL ;
    PORT
      LAYER M4 ;
        RECT  86.208 12.732 86.4 12.756 ;
    END
  END prm[50]
  PIN prm[510]
    DIRECTION OUTPUT ;
    USE SIGNAL ;
    PORT
      LAYER M5 ;
        RECT  27.564 0 27.588 0.192 ;
    END
  END prm[510]
  PIN prm[511]
    DIRECTION OUTPUT ;
    USE SIGNAL ;
    PORT
      LAYER M5 ;
        RECT  27.756 0 27.78 0.192 ;
    END
  END prm[511]
  PIN prm[512]
    DIRECTION OUTPUT ;
    USE SIGNAL ;
    PORT
      LAYER M5 ;
        RECT  27.996 0 28.02 0.192 ;
    END
  END prm[512]
  PIN prm[513]
    DIRECTION OUTPUT ;
    USE SIGNAL ;
    PORT
      LAYER M5 ;
        RECT  28.188 0 28.212 0.192 ;
    END
  END prm[513]
  PIN prm[514]
    DIRECTION OUTPUT ;
    USE SIGNAL ;
    PORT
      LAYER M5 ;
        RECT  28.38 0 28.404 0.192 ;
    END
  END prm[514]
  PIN prm[515]
    DIRECTION OUTPUT ;
    USE SIGNAL ;
    PORT
      LAYER M5 ;
        RECT  28.62 0 28.644 0.192 ;
    END
  END prm[515]
  PIN prm[516]
    DIRECTION OUTPUT ;
    USE SIGNAL ;
    PORT
      LAYER M5 ;
        RECT  28.812 0 28.836 0.192 ;
    END
  END prm[516]
  PIN prm[517]
    DIRECTION OUTPUT ;
    USE SIGNAL ;
    PORT
      LAYER M5 ;
        RECT  29.004 0 29.028 0.192 ;
    END
  END prm[517]
  PIN prm[518]
    DIRECTION OUTPUT ;
    USE SIGNAL ;
    PORT
      LAYER M5 ;
        RECT  29.244 0 29.268 0.192 ;
    END
  END prm[518]
  PIN prm[519]
    DIRECTION OUTPUT ;
    USE SIGNAL ;
    PORT
      LAYER M5 ;
        RECT  29.436 0 29.46 0.192 ;
    END
  END prm[519]
  PIN prm[51]
    DIRECTION OUTPUT ;
    USE SIGNAL ;
    PORT
      LAYER M4 ;
        RECT  86.208 12.972 86.4 12.996 ;
    END
  END prm[51]
  PIN prm[520]
    DIRECTION OUTPUT ;
    USE SIGNAL ;
    PORT
      LAYER M5 ;
        RECT  29.676 0 29.7 0.192 ;
    END
  END prm[520]
  PIN prm[521]
    DIRECTION OUTPUT ;
    USE SIGNAL ;
    PORT
      LAYER M5 ;
        RECT  29.868 0 29.892 0.192 ;
    END
  END prm[521]
  PIN prm[522]
    DIRECTION OUTPUT ;
    USE SIGNAL ;
    PORT
      LAYER M5 ;
        RECT  30.06 0 30.084 0.192 ;
    END
  END prm[522]
  PIN prm[523]
    DIRECTION OUTPUT ;
    USE SIGNAL ;
    PORT
      LAYER M5 ;
        RECT  30.3 0 30.324 0.192 ;
    END
  END prm[523]
  PIN prm[524]
    DIRECTION OUTPUT ;
    USE SIGNAL ;
    PORT
      LAYER M5 ;
        RECT  30.492 0 30.516 0.192 ;
    END
  END prm[524]
  PIN prm[525]
    DIRECTION OUTPUT ;
    USE SIGNAL ;
    PORT
      LAYER M5 ;
        RECT  30.684 0 30.708 0.192 ;
    END
  END prm[525]
  PIN prm[526]
    DIRECTION OUTPUT ;
    USE SIGNAL ;
    PORT
      LAYER M5 ;
        RECT  30.924 0 30.948 0.192 ;
    END
  END prm[526]
  PIN prm[527]
    DIRECTION OUTPUT ;
    USE SIGNAL ;
    PORT
      LAYER M5 ;
        RECT  31.116 0 31.14 0.192 ;
    END
  END prm[527]
  PIN prm[528]
    DIRECTION OUTPUT ;
    USE SIGNAL ;
    PORT
      LAYER M5 ;
        RECT  31.356 0 31.38 0.192 ;
    END
  END prm[528]
  PIN prm[529]
    DIRECTION OUTPUT ;
    USE SIGNAL ;
    PORT
      LAYER M5 ;
        RECT  31.548 0 31.572 0.192 ;
    END
  END prm[529]
  PIN prm[52]
    DIRECTION OUTPUT ;
    USE SIGNAL ;
    PORT
      LAYER M4 ;
        RECT  86.208 13.164 86.4 13.188 ;
    END
  END prm[52]
  PIN prm[530]
    DIRECTION OUTPUT ;
    USE SIGNAL ;
    PORT
      LAYER M5 ;
        RECT  31.74 0 31.764 0.192 ;
    END
  END prm[530]
  PIN prm[531]
    DIRECTION OUTPUT ;
    USE SIGNAL ;
    PORT
      LAYER M5 ;
        RECT  31.98 0 32.004 0.192 ;
    END
  END prm[531]
  PIN prm[532]
    DIRECTION OUTPUT ;
    USE SIGNAL ;
    PORT
      LAYER M5 ;
        RECT  32.172 0 32.196 0.192 ;
    END
  END prm[532]
  PIN prm[533]
    DIRECTION OUTPUT ;
    USE SIGNAL ;
    PORT
      LAYER M5 ;
        RECT  32.364 0 32.388 0.192 ;
    END
  END prm[533]
  PIN prm[534]
    DIRECTION OUTPUT ;
    USE SIGNAL ;
    PORT
      LAYER M5 ;
        RECT  32.604 0 32.628 0.192 ;
    END
  END prm[534]
  PIN prm[535]
    DIRECTION OUTPUT ;
    USE SIGNAL ;
    PORT
      LAYER M5 ;
        RECT  32.796 0 32.82 0.192 ;
    END
  END prm[535]
  PIN prm[536]
    DIRECTION OUTPUT ;
    USE SIGNAL ;
    PORT
      LAYER M5 ;
        RECT  33.036 0 33.06 0.192 ;
    END
  END prm[536]
  PIN prm[537]
    DIRECTION OUTPUT ;
    USE SIGNAL ;
    PORT
      LAYER M5 ;
        RECT  33.228 0 33.252 0.192 ;
    END
  END prm[537]
  PIN prm[538]
    DIRECTION OUTPUT ;
    USE SIGNAL ;
    PORT
      LAYER M5 ;
        RECT  33.42 0 33.444 0.192 ;
    END
  END prm[538]
  PIN prm[539]
    DIRECTION OUTPUT ;
    USE SIGNAL ;
    PORT
      LAYER M5 ;
        RECT  33.66 0 33.684 0.192 ;
    END
  END prm[539]
  PIN prm[53]
    DIRECTION OUTPUT ;
    USE SIGNAL ;
    PORT
      LAYER M4 ;
        RECT  86.208 13.356 86.4 13.38 ;
    END
  END prm[53]
  PIN prm[540]
    DIRECTION OUTPUT ;
    USE SIGNAL ;
    PORT
      LAYER M5 ;
        RECT  33.852 0 33.876 0.192 ;
    END
  END prm[540]
  PIN prm[541]
    DIRECTION OUTPUT ;
    USE SIGNAL ;
    PORT
      LAYER M5 ;
        RECT  34.044 0 34.068 0.192 ;
    END
  END prm[541]
  PIN prm[542]
    DIRECTION OUTPUT ;
    USE SIGNAL ;
    PORT
      LAYER M5 ;
        RECT  34.284 0 34.308 0.192 ;
    END
  END prm[542]
  PIN prm[543]
    DIRECTION OUTPUT ;
    USE SIGNAL ;
    PORT
      LAYER M5 ;
        RECT  34.476 0 34.5 0.192 ;
    END
  END prm[543]
  PIN prm[544]
    DIRECTION OUTPUT ;
    USE SIGNAL ;
    PORT
      LAYER M5 ;
        RECT  34.668 0 34.692 0.192 ;
    END
  END prm[544]
  PIN prm[545]
    DIRECTION OUTPUT ;
    USE SIGNAL ;
    PORT
      LAYER M5 ;
        RECT  34.908 0 34.932 0.192 ;
    END
  END prm[545]
  PIN prm[546]
    DIRECTION OUTPUT ;
    USE SIGNAL ;
    PORT
      LAYER M5 ;
        RECT  35.1 0 35.124 0.192 ;
    END
  END prm[546]
  PIN prm[547]
    DIRECTION OUTPUT ;
    USE SIGNAL ;
    PORT
      LAYER M5 ;
        RECT  35.34 0 35.364 0.192 ;
    END
  END prm[547]
  PIN prm[548]
    DIRECTION OUTPUT ;
    USE SIGNAL ;
    PORT
      LAYER M5 ;
        RECT  35.532 0 35.556 0.192 ;
    END
  END prm[548]
  PIN prm[549]
    DIRECTION OUTPUT ;
    USE SIGNAL ;
    PORT
      LAYER M5 ;
        RECT  35.724 0 35.748 0.192 ;
    END
  END prm[549]
  PIN prm[54]
    DIRECTION OUTPUT ;
    USE SIGNAL ;
    PORT
      LAYER M4 ;
        RECT  86.208 13.596 86.4 13.62 ;
    END
  END prm[54]
  PIN prm[550]
    DIRECTION OUTPUT ;
    USE SIGNAL ;
    PORT
      LAYER M5 ;
        RECT  35.964 0 35.988 0.192 ;
    END
  END prm[550]
  PIN prm[551]
    DIRECTION OUTPUT ;
    USE SIGNAL ;
    PORT
      LAYER M5 ;
        RECT  36.156 0 36.18 0.192 ;
    END
  END prm[551]
  PIN prm[552]
    DIRECTION OUTPUT ;
    USE SIGNAL ;
    PORT
      LAYER M5 ;
        RECT  36.348 0 36.372 0.192 ;
    END
  END prm[552]
  PIN prm[553]
    DIRECTION OUTPUT ;
    USE SIGNAL ;
    PORT
      LAYER M5 ;
        RECT  36.588 0 36.612 0.192 ;
    END
  END prm[553]
  PIN prm[554]
    DIRECTION OUTPUT ;
    USE SIGNAL ;
    PORT
      LAYER M5 ;
        RECT  36.78 0 36.804 0.192 ;
    END
  END prm[554]
  PIN prm[555]
    DIRECTION OUTPUT ;
    USE SIGNAL ;
    PORT
      LAYER M5 ;
        RECT  37.02 0 37.044 0.192 ;
    END
  END prm[555]
  PIN prm[556]
    DIRECTION OUTPUT ;
    USE SIGNAL ;
    PORT
      LAYER M5 ;
        RECT  37.212 0 37.236 0.192 ;
    END
  END prm[556]
  PIN prm[557]
    DIRECTION OUTPUT ;
    USE SIGNAL ;
    PORT
      LAYER M5 ;
        RECT  37.404 0 37.428 0.192 ;
    END
  END prm[557]
  PIN prm[558]
    DIRECTION OUTPUT ;
    USE SIGNAL ;
    PORT
      LAYER M5 ;
        RECT  37.644 0 37.668 0.192 ;
    END
  END prm[558]
  PIN prm[559]
    DIRECTION OUTPUT ;
    USE SIGNAL ;
    PORT
      LAYER M5 ;
        RECT  37.836 0 37.86 0.192 ;
    END
  END prm[559]
  PIN prm[55]
    DIRECTION OUTPUT ;
    USE SIGNAL ;
    PORT
      LAYER M4 ;
        RECT  86.208 13.788 86.4 13.812 ;
    END
  END prm[55]
  PIN prm[560]
    DIRECTION OUTPUT ;
    USE SIGNAL ;
    PORT
      LAYER M5 ;
        RECT  38.028 0 38.052 0.192 ;
    END
  END prm[560]
  PIN prm[561]
    DIRECTION OUTPUT ;
    USE SIGNAL ;
    PORT
      LAYER M5 ;
        RECT  38.268 0 38.292 0.192 ;
    END
  END prm[561]
  PIN prm[562]
    DIRECTION OUTPUT ;
    USE SIGNAL ;
    PORT
      LAYER M5 ;
        RECT  38.46 0 38.484 0.192 ;
    END
  END prm[562]
  PIN prm[563]
    DIRECTION OUTPUT ;
    USE SIGNAL ;
    PORT
      LAYER M5 ;
        RECT  38.7 0 38.724 0.192 ;
    END
  END prm[563]
  PIN prm[564]
    DIRECTION OUTPUT ;
    USE SIGNAL ;
    PORT
      LAYER M5 ;
        RECT  38.892 0 38.916 0.192 ;
    END
  END prm[564]
  PIN prm[565]
    DIRECTION OUTPUT ;
    USE SIGNAL ;
    PORT
      LAYER M5 ;
        RECT  39.084 0 39.108 0.192 ;
    END
  END prm[565]
  PIN prm[566]
    DIRECTION OUTPUT ;
    USE SIGNAL ;
    PORT
      LAYER M5 ;
        RECT  39.324 0 39.348 0.192 ;
    END
  END prm[566]
  PIN prm[567]
    DIRECTION OUTPUT ;
    USE SIGNAL ;
    PORT
      LAYER M5 ;
        RECT  39.516 0 39.54 0.192 ;
    END
  END prm[567]
  PIN prm[568]
    DIRECTION OUTPUT ;
    USE SIGNAL ;
    PORT
      LAYER M5 ;
        RECT  39.708 0 39.732 0.192 ;
    END
  END prm[568]
  PIN prm[569]
    DIRECTION OUTPUT ;
    USE SIGNAL ;
    PORT
      LAYER M5 ;
        RECT  39.948 0 39.972 0.192 ;
    END
  END prm[569]
  PIN prm[56]
    DIRECTION OUTPUT ;
    USE SIGNAL ;
    PORT
      LAYER M4 ;
        RECT  86.208 14.028 86.4 14.052 ;
    END
  END prm[56]
  PIN prm[570]
    DIRECTION OUTPUT ;
    USE SIGNAL ;
    PORT
      LAYER M5 ;
        RECT  40.14 0 40.164 0.192 ;
    END
  END prm[570]
  PIN prm[571]
    DIRECTION OUTPUT ;
    USE SIGNAL ;
    PORT
      LAYER M5 ;
        RECT  40.332 0 40.356 0.192 ;
    END
  END prm[571]
  PIN prm[572]
    DIRECTION OUTPUT ;
    USE SIGNAL ;
    PORT
      LAYER M5 ;
        RECT  40.572 0 40.596 0.192 ;
    END
  END prm[572]
  PIN prm[573]
    DIRECTION OUTPUT ;
    USE SIGNAL ;
    PORT
      LAYER M5 ;
        RECT  40.764 0 40.788 0.192 ;
    END
  END prm[573]
  PIN prm[574]
    DIRECTION OUTPUT ;
    USE SIGNAL ;
    PORT
      LAYER M5 ;
        RECT  41.004 0 41.028 0.192 ;
    END
  END prm[574]
  PIN prm[575]
    DIRECTION OUTPUT ;
    USE SIGNAL ;
    PORT
      LAYER M5 ;
        RECT  41.196 0 41.22 0.192 ;
    END
  END prm[575]
  PIN prm[576]
    DIRECTION OUTPUT ;
    USE SIGNAL ;
    PORT
      LAYER M5 ;
        RECT  41.388 0 41.412 0.192 ;
    END
  END prm[576]
  PIN prm[577]
    DIRECTION OUTPUT ;
    USE SIGNAL ;
    PORT
      LAYER M5 ;
        RECT  41.628 0 41.652 0.192 ;
    END
  END prm[577]
  PIN prm[578]
    DIRECTION OUTPUT ;
    USE SIGNAL ;
    PORT
      LAYER M5 ;
        RECT  41.82 0 41.844 0.192 ;
    END
  END prm[578]
  PIN prm[579]
    DIRECTION OUTPUT ;
    USE SIGNAL ;
    PORT
      LAYER M5 ;
        RECT  42.012 0 42.036 0.192 ;
    END
  END prm[579]
  PIN prm[57]
    DIRECTION OUTPUT ;
    USE SIGNAL ;
    PORT
      LAYER M4 ;
        RECT  86.208 14.22 86.4 14.244 ;
    END
  END prm[57]
  PIN prm[580]
    DIRECTION OUTPUT ;
    USE SIGNAL ;
    PORT
      LAYER M5 ;
        RECT  42.252 0 42.276 0.192 ;
    END
  END prm[580]
  PIN prm[581]
    DIRECTION OUTPUT ;
    USE SIGNAL ;
    PORT
      LAYER M5 ;
        RECT  42.444 0 42.468 0.192 ;
    END
  END prm[581]
  PIN prm[582]
    DIRECTION OUTPUT ;
    USE SIGNAL ;
    PORT
      LAYER M5 ;
        RECT  42.684 0 42.708 0.192 ;
    END
  END prm[582]
  PIN prm[583]
    DIRECTION OUTPUT ;
    USE SIGNAL ;
    PORT
      LAYER M5 ;
        RECT  42.876 0 42.9 0.192 ;
    END
  END prm[583]
  PIN prm[584]
    DIRECTION OUTPUT ;
    USE SIGNAL ;
    PORT
      LAYER M5 ;
        RECT  43.068 0 43.092 0.192 ;
    END
  END prm[584]
  PIN prm[585]
    DIRECTION OUTPUT ;
    USE SIGNAL ;
    PORT
      LAYER M5 ;
        RECT  43.308 0 43.332 0.192 ;
    END
  END prm[585]
  PIN prm[586]
    DIRECTION OUTPUT ;
    USE SIGNAL ;
    PORT
      LAYER M5 ;
        RECT  43.5 0 43.524 0.192 ;
    END
  END prm[586]
  PIN prm[587]
    DIRECTION OUTPUT ;
    USE SIGNAL ;
    PORT
      LAYER M5 ;
        RECT  43.692 0 43.716 0.192 ;
    END
  END prm[587]
  PIN prm[588]
    DIRECTION OUTPUT ;
    USE SIGNAL ;
    PORT
      LAYER M5 ;
        RECT  43.932 0 43.956 0.192 ;
    END
  END prm[588]
  PIN prm[589]
    DIRECTION OUTPUT ;
    USE SIGNAL ;
    PORT
      LAYER M5 ;
        RECT  44.124 0 44.148 0.192 ;
    END
  END prm[589]
  PIN prm[58]
    DIRECTION OUTPUT ;
    USE SIGNAL ;
    PORT
      LAYER M4 ;
        RECT  86.208 14.412 86.4 14.436 ;
    END
  END prm[58]
  PIN prm[590]
    DIRECTION OUTPUT ;
    USE SIGNAL ;
    PORT
      LAYER M5 ;
        RECT  44.364 0 44.388 0.192 ;
    END
  END prm[590]
  PIN prm[591]
    DIRECTION OUTPUT ;
    USE SIGNAL ;
    PORT
      LAYER M5 ;
        RECT  44.556 0 44.58 0.192 ;
    END
  END prm[591]
  PIN prm[592]
    DIRECTION OUTPUT ;
    USE SIGNAL ;
    PORT
      LAYER M5 ;
        RECT  44.748 0 44.772 0.192 ;
    END
  END prm[592]
  PIN prm[593]
    DIRECTION OUTPUT ;
    USE SIGNAL ;
    PORT
      LAYER M5 ;
        RECT  44.988 0 45.012 0.192 ;
    END
  END prm[593]
  PIN prm[594]
    DIRECTION OUTPUT ;
    USE SIGNAL ;
    PORT
      LAYER M5 ;
        RECT  45.18 0 45.204 0.192 ;
    END
  END prm[594]
  PIN prm[595]
    DIRECTION OUTPUT ;
    USE SIGNAL ;
    PORT
      LAYER M5 ;
        RECT  45.372 0 45.396 0.192 ;
    END
  END prm[595]
  PIN prm[596]
    DIRECTION OUTPUT ;
    USE SIGNAL ;
    PORT
      LAYER M5 ;
        RECT  45.612 0 45.636 0.192 ;
    END
  END prm[596]
  PIN prm[597]
    DIRECTION OUTPUT ;
    USE SIGNAL ;
    PORT
      LAYER M5 ;
        RECT  45.804 0 45.828 0.192 ;
    END
  END prm[597]
  PIN prm[598]
    DIRECTION OUTPUT ;
    USE SIGNAL ;
    PORT
      LAYER M5 ;
        RECT  46.044 0 46.068 0.192 ;
    END
  END prm[598]
  PIN prm[599]
    DIRECTION OUTPUT ;
    USE SIGNAL ;
    PORT
      LAYER M5 ;
        RECT  46.236 0 46.26 0.192 ;
    END
  END prm[599]
  PIN prm[59]
    DIRECTION OUTPUT ;
    USE SIGNAL ;
    PORT
      LAYER M4 ;
        RECT  86.208 14.652 86.4 14.676 ;
    END
  END prm[59]
  PIN prm[5]
    DIRECTION OUTPUT ;
    USE SIGNAL ;
    PORT
      LAYER M4 ;
        RECT  86.208 3.228 86.4 3.252 ;
    END
  END prm[5]
  PIN prm[600]
    DIRECTION OUTPUT ;
    USE SIGNAL ;
    PORT
      LAYER M5 ;
        RECT  46.428 0 46.452 0.192 ;
    END
  END prm[600]
  PIN prm[601]
    DIRECTION OUTPUT ;
    USE SIGNAL ;
    PORT
      LAYER M5 ;
        RECT  46.668 0 46.692 0.192 ;
    END
  END prm[601]
  PIN prm[602]
    DIRECTION OUTPUT ;
    USE SIGNAL ;
    PORT
      LAYER M5 ;
        RECT  46.86 0 46.884 0.192 ;
    END
  END prm[602]
  PIN prm[603]
    DIRECTION OUTPUT ;
    USE SIGNAL ;
    PORT
      LAYER M5 ;
        RECT  47.052 0 47.076 0.192 ;
    END
  END prm[603]
  PIN prm[604]
    DIRECTION OUTPUT ;
    USE SIGNAL ;
    PORT
      LAYER M5 ;
        RECT  47.292 0 47.316 0.192 ;
    END
  END prm[604]
  PIN prm[605]
    DIRECTION OUTPUT ;
    USE SIGNAL ;
    PORT
      LAYER M5 ;
        RECT  47.484 0 47.508 0.192 ;
    END
  END prm[605]
  PIN prm[606]
    DIRECTION OUTPUT ;
    USE SIGNAL ;
    PORT
      LAYER M5 ;
        RECT  47.676 0 47.7 0.192 ;
    END
  END prm[606]
  PIN prm[607]
    DIRECTION OUTPUT ;
    USE SIGNAL ;
    PORT
      LAYER M5 ;
        RECT  47.916 0 47.94 0.192 ;
    END
  END prm[607]
  PIN prm[608]
    DIRECTION OUTPUT ;
    USE SIGNAL ;
    PORT
      LAYER M5 ;
        RECT  48.108 0 48.132 0.192 ;
    END
  END prm[608]
  PIN prm[609]
    DIRECTION OUTPUT ;
    USE SIGNAL ;
    PORT
      LAYER M5 ;
        RECT  48.348 0 48.372 0.192 ;
    END
  END prm[609]
  PIN prm[60]
    DIRECTION OUTPUT ;
    USE SIGNAL ;
    PORT
      LAYER M4 ;
        RECT  86.208 14.844 86.4 14.868 ;
    END
  END prm[60]
  PIN prm[610]
    DIRECTION OUTPUT ;
    USE SIGNAL ;
    PORT
      LAYER M5 ;
        RECT  48.54 0 48.564 0.192 ;
    END
  END prm[610]
  PIN prm[611]
    DIRECTION OUTPUT ;
    USE SIGNAL ;
    PORT
      LAYER M5 ;
        RECT  48.732 0 48.756 0.192 ;
    END
  END prm[611]
  PIN prm[612]
    DIRECTION OUTPUT ;
    USE SIGNAL ;
    PORT
      LAYER M5 ;
        RECT  48.972 0 48.996 0.192 ;
    END
  END prm[612]
  PIN prm[613]
    DIRECTION OUTPUT ;
    USE SIGNAL ;
    PORT
      LAYER M5 ;
        RECT  49.164 0 49.188 0.192 ;
    END
  END prm[613]
  PIN prm[614]
    DIRECTION OUTPUT ;
    USE SIGNAL ;
    PORT
      LAYER M5 ;
        RECT  49.356 0 49.38 0.192 ;
    END
  END prm[614]
  PIN prm[615]
    DIRECTION OUTPUT ;
    USE SIGNAL ;
    PORT
      LAYER M5 ;
        RECT  49.596 0 49.62 0.192 ;
    END
  END prm[615]
  PIN prm[616]
    DIRECTION OUTPUT ;
    USE SIGNAL ;
    PORT
      LAYER M5 ;
        RECT  49.788 0 49.812 0.192 ;
    END
  END prm[616]
  PIN prm[617]
    DIRECTION OUTPUT ;
    USE SIGNAL ;
    PORT
      LAYER M5 ;
        RECT  50.028 0 50.052 0.192 ;
    END
  END prm[617]
  PIN prm[618]
    DIRECTION OUTPUT ;
    USE SIGNAL ;
    PORT
      LAYER M5 ;
        RECT  50.22 0 50.244 0.192 ;
    END
  END prm[618]
  PIN prm[619]
    DIRECTION OUTPUT ;
    USE SIGNAL ;
    PORT
      LAYER M5 ;
        RECT  50.412 0 50.436 0.192 ;
    END
  END prm[619]
  PIN prm[61]
    DIRECTION OUTPUT ;
    USE SIGNAL ;
    PORT
      LAYER M4 ;
        RECT  86.208 15.084 86.4 15.108 ;
    END
  END prm[61]
  PIN prm[620]
    DIRECTION OUTPUT ;
    USE SIGNAL ;
    PORT
      LAYER M5 ;
        RECT  50.652 0 50.676 0.192 ;
    END
  END prm[620]
  PIN prm[621]
    DIRECTION OUTPUT ;
    USE SIGNAL ;
    PORT
      LAYER M5 ;
        RECT  50.844 0 50.868 0.192 ;
    END
  END prm[621]
  PIN prm[622]
    DIRECTION OUTPUT ;
    USE SIGNAL ;
    PORT
      LAYER M5 ;
        RECT  51.036 0 51.06 0.192 ;
    END
  END prm[622]
  PIN prm[623]
    DIRECTION OUTPUT ;
    USE SIGNAL ;
    PORT
      LAYER M5 ;
        RECT  51.276 0 51.3 0.192 ;
    END
  END prm[623]
  PIN prm[624]
    DIRECTION OUTPUT ;
    USE SIGNAL ;
    PORT
      LAYER M5 ;
        RECT  51.468 0 51.492 0.192 ;
    END
  END prm[624]
  PIN prm[625]
    DIRECTION OUTPUT ;
    USE SIGNAL ;
    PORT
      LAYER M5 ;
        RECT  51.708 0 51.732 0.192 ;
    END
  END prm[625]
  PIN prm[626]
    DIRECTION OUTPUT ;
    USE SIGNAL ;
    PORT
      LAYER M5 ;
        RECT  51.9 0 51.924 0.192 ;
    END
  END prm[626]
  PIN prm[627]
    DIRECTION OUTPUT ;
    USE SIGNAL ;
    PORT
      LAYER M5 ;
        RECT  52.092 0 52.116 0.192 ;
    END
  END prm[627]
  PIN prm[628]
    DIRECTION OUTPUT ;
    USE SIGNAL ;
    PORT
      LAYER M5 ;
        RECT  52.332 0 52.356 0.192 ;
    END
  END prm[628]
  PIN prm[629]
    DIRECTION OUTPUT ;
    USE SIGNAL ;
    PORT
      LAYER M5 ;
        RECT  52.524 0 52.548 0.192 ;
    END
  END prm[629]
  PIN prm[62]
    DIRECTION OUTPUT ;
    USE SIGNAL ;
    PORT
      LAYER M4 ;
        RECT  86.208 15.276 86.4 15.3 ;
    END
  END prm[62]
  PIN prm[630]
    DIRECTION OUTPUT ;
    USE SIGNAL ;
    PORT
      LAYER M5 ;
        RECT  52.716 0 52.74 0.192 ;
    END
  END prm[630]
  PIN prm[631]
    DIRECTION OUTPUT ;
    USE SIGNAL ;
    PORT
      LAYER M5 ;
        RECT  52.956 0 52.98 0.192 ;
    END
  END prm[631]
  PIN prm[632]
    DIRECTION OUTPUT ;
    USE SIGNAL ;
    PORT
      LAYER M5 ;
        RECT  53.148 0 53.172 0.192 ;
    END
  END prm[632]
  PIN prm[633]
    DIRECTION OUTPUT ;
    USE SIGNAL ;
    PORT
      LAYER M5 ;
        RECT  53.34 0 53.364 0.192 ;
    END
  END prm[633]
  PIN prm[634]
    DIRECTION OUTPUT ;
    USE SIGNAL ;
    PORT
      LAYER M5 ;
        RECT  53.58 0 53.604 0.192 ;
    END
  END prm[634]
  PIN prm[635]
    DIRECTION OUTPUT ;
    USE SIGNAL ;
    PORT
      LAYER M5 ;
        RECT  53.772 0 53.796 0.192 ;
    END
  END prm[635]
  PIN prm[636]
    DIRECTION OUTPUT ;
    USE SIGNAL ;
    PORT
      LAYER M5 ;
        RECT  54.012 0 54.036 0.192 ;
    END
  END prm[636]
  PIN prm[637]
    DIRECTION OUTPUT ;
    USE SIGNAL ;
    PORT
      LAYER M5 ;
        RECT  54.204 0 54.228 0.192 ;
    END
  END prm[637]
  PIN prm[638]
    DIRECTION OUTPUT ;
    USE SIGNAL ;
    PORT
      LAYER M5 ;
        RECT  54.396 0 54.42 0.192 ;
    END
  END prm[638]
  PIN prm[639]
    DIRECTION OUTPUT ;
    USE SIGNAL ;
    PORT
      LAYER M5 ;
        RECT  54.636 0 54.66 0.192 ;
    END
  END prm[639]
  PIN prm[63]
    DIRECTION OUTPUT ;
    USE SIGNAL ;
    PORT
      LAYER M4 ;
        RECT  86.208 15.468 86.4 15.492 ;
    END
  END prm[63]
  PIN prm[640]
    DIRECTION OUTPUT ;
    USE SIGNAL ;
    PORT
      LAYER M5 ;
        RECT  54.828 0 54.852 0.192 ;
    END
  END prm[640]
  PIN prm[641]
    DIRECTION OUTPUT ;
    USE SIGNAL ;
    PORT
      LAYER M5 ;
        RECT  55.02 0 55.044 0.192 ;
    END
  END prm[641]
  PIN prm[642]
    DIRECTION OUTPUT ;
    USE SIGNAL ;
    PORT
      LAYER M5 ;
        RECT  55.26 0 55.284 0.192 ;
    END
  END prm[642]
  PIN prm[643]
    DIRECTION OUTPUT ;
    USE SIGNAL ;
    PORT
      LAYER M5 ;
        RECT  55.452 0 55.476 0.192 ;
    END
  END prm[643]
  PIN prm[644]
    DIRECTION OUTPUT ;
    USE SIGNAL ;
    PORT
      LAYER M5 ;
        RECT  55.692 0 55.716 0.192 ;
    END
  END prm[644]
  PIN prm[645]
    DIRECTION OUTPUT ;
    USE SIGNAL ;
    PORT
      LAYER M5 ;
        RECT  55.884 0 55.908 0.192 ;
    END
  END prm[645]
  PIN prm[646]
    DIRECTION OUTPUT ;
    USE SIGNAL ;
    PORT
      LAYER M5 ;
        RECT  56.076 0 56.1 0.192 ;
    END
  END prm[646]
  PIN prm[647]
    DIRECTION OUTPUT ;
    USE SIGNAL ;
    PORT
      LAYER M5 ;
        RECT  56.316 0 56.34 0.192 ;
    END
  END prm[647]
  PIN prm[648]
    DIRECTION OUTPUT ;
    USE SIGNAL ;
    PORT
      LAYER M5 ;
        RECT  56.508 0 56.532 0.192 ;
    END
  END prm[648]
  PIN prm[649]
    DIRECTION OUTPUT ;
    USE SIGNAL ;
    PORT
      LAYER M5 ;
        RECT  56.7 0 56.724 0.192 ;
    END
  END prm[649]
  PIN prm[64]
    DIRECTION OUTPUT ;
    USE SIGNAL ;
    PORT
      LAYER M4 ;
        RECT  86.208 15.708 86.4 15.732 ;
    END
  END prm[64]
  PIN prm[650]
    DIRECTION OUTPUT ;
    USE SIGNAL ;
    PORT
      LAYER M5 ;
        RECT  56.94 0 56.964 0.192 ;
    END
  END prm[650]
  PIN prm[651]
    DIRECTION OUTPUT ;
    USE SIGNAL ;
    PORT
      LAYER M5 ;
        RECT  57.132 0 57.156 0.192 ;
    END
  END prm[651]
  PIN prm[652]
    DIRECTION OUTPUT ;
    USE SIGNAL ;
    PORT
      LAYER M5 ;
        RECT  57.372 0 57.396 0.192 ;
    END
  END prm[652]
  PIN prm[653]
    DIRECTION OUTPUT ;
    USE SIGNAL ;
    PORT
      LAYER M5 ;
        RECT  57.564 0 57.588 0.192 ;
    END
  END prm[653]
  PIN prm[654]
    DIRECTION OUTPUT ;
    USE SIGNAL ;
    PORT
      LAYER M5 ;
        RECT  57.756 0 57.78 0.192 ;
    END
  END prm[654]
  PIN prm[655]
    DIRECTION OUTPUT ;
    USE SIGNAL ;
    PORT
      LAYER M5 ;
        RECT  57.996 0 58.02 0.192 ;
    END
  END prm[655]
  PIN prm[656]
    DIRECTION OUTPUT ;
    USE SIGNAL ;
    PORT
      LAYER M5 ;
        RECT  58.188 0 58.212 0.192 ;
    END
  END prm[656]
  PIN prm[657]
    DIRECTION OUTPUT ;
    USE SIGNAL ;
    PORT
      LAYER M5 ;
        RECT  58.38 0 58.404 0.192 ;
    END
  END prm[657]
  PIN prm[658]
    DIRECTION OUTPUT ;
    USE SIGNAL ;
    PORT
      LAYER M5 ;
        RECT  58.62 0 58.644 0.192 ;
    END
  END prm[658]
  PIN prm[659]
    DIRECTION OUTPUT ;
    USE SIGNAL ;
    PORT
      LAYER M5 ;
        RECT  58.812 0 58.836 0.192 ;
    END
  END prm[659]
  PIN prm[65]
    DIRECTION OUTPUT ;
    USE SIGNAL ;
    PORT
      LAYER M4 ;
        RECT  86.208 15.9 86.4 15.924 ;
    END
  END prm[65]
  PIN prm[660]
    DIRECTION OUTPUT ;
    USE SIGNAL ;
    PORT
      LAYER M5 ;
        RECT  59.004 0 59.028 0.192 ;
    END
  END prm[660]
  PIN prm[661]
    DIRECTION OUTPUT ;
    USE SIGNAL ;
    PORT
      LAYER M5 ;
        RECT  59.244 0 59.268 0.192 ;
    END
  END prm[661]
  PIN prm[662]
    DIRECTION OUTPUT ;
    USE SIGNAL ;
    PORT
      LAYER M5 ;
        RECT  59.436 0 59.46 0.192 ;
    END
  END prm[662]
  PIN prm[663]
    DIRECTION OUTPUT ;
    USE SIGNAL ;
    PORT
      LAYER M5 ;
        RECT  59.676 0 59.7 0.192 ;
    END
  END prm[663]
  PIN prm[664]
    DIRECTION OUTPUT ;
    USE SIGNAL ;
    PORT
      LAYER M5 ;
        RECT  59.868 0 59.892 0.192 ;
    END
  END prm[664]
  PIN prm[665]
    DIRECTION OUTPUT ;
    USE SIGNAL ;
    PORT
      LAYER M5 ;
        RECT  60.06 0 60.084 0.192 ;
    END
  END prm[665]
  PIN prm[666]
    DIRECTION OUTPUT ;
    USE SIGNAL ;
    PORT
      LAYER M5 ;
        RECT  60.3 0 60.324 0.192 ;
    END
  END prm[666]
  PIN prm[667]
    DIRECTION OUTPUT ;
    USE SIGNAL ;
    PORT
      LAYER M5 ;
        RECT  60.492 0 60.516 0.192 ;
    END
  END prm[667]
  PIN prm[668]
    DIRECTION OUTPUT ;
    USE SIGNAL ;
    PORT
      LAYER M5 ;
        RECT  60.684 0 60.708 0.192 ;
    END
  END prm[668]
  PIN prm[669]
    DIRECTION OUTPUT ;
    USE SIGNAL ;
    PORT
      LAYER M5 ;
        RECT  60.924 0 60.948 0.192 ;
    END
  END prm[669]
  PIN prm[66]
    DIRECTION OUTPUT ;
    USE SIGNAL ;
    PORT
      LAYER M4 ;
        RECT  86.208 16.14 86.4 16.164 ;
    END
  END prm[66]
  PIN prm[670]
    DIRECTION OUTPUT ;
    USE SIGNAL ;
    PORT
      LAYER M5 ;
        RECT  61.116 0 61.14 0.192 ;
    END
  END prm[670]
  PIN prm[671]
    DIRECTION OUTPUT ;
    USE SIGNAL ;
    PORT
      LAYER M5 ;
        RECT  61.356 0 61.38 0.192 ;
    END
  END prm[671]
  PIN prm[672]
    DIRECTION OUTPUT ;
    USE SIGNAL ;
    PORT
      LAYER M5 ;
        RECT  61.548 0 61.572 0.192 ;
    END
  END prm[672]
  PIN prm[673]
    DIRECTION OUTPUT ;
    USE SIGNAL ;
    PORT
      LAYER M5 ;
        RECT  64.14 86.208 64.164 86.4 ;
    END
  END prm[673]
  PIN prm[674]
    DIRECTION OUTPUT ;
    USE SIGNAL ;
    PORT
      LAYER M5 ;
        RECT  64.332 86.208 64.356 86.4 ;
    END
  END prm[674]
  PIN prm[675]
    DIRECTION OUTPUT ;
    USE SIGNAL ;
    PORT
      LAYER M5 ;
        RECT  64.524 86.208 64.548 86.4 ;
    END
  END prm[675]
  PIN prm[676]
    DIRECTION OUTPUT ;
    USE SIGNAL ;
    PORT
      LAYER M5 ;
        RECT  64.764 86.208 64.788 86.4 ;
    END
  END prm[676]
  PIN prm[677]
    DIRECTION OUTPUT ;
    USE SIGNAL ;
    PORT
      LAYER M5 ;
        RECT  64.956 86.208 64.98 86.4 ;
    END
  END prm[677]
  PIN prm[678]
    DIRECTION OUTPUT ;
    USE SIGNAL ;
    PORT
      LAYER M5 ;
        RECT  65.196 86.208 65.22 86.4 ;
    END
  END prm[678]
  PIN prm[679]
    DIRECTION OUTPUT ;
    USE SIGNAL ;
    PORT
      LAYER M5 ;
        RECT  65.388 86.208 65.412 86.4 ;
    END
  END prm[679]
  PIN prm[67]
    DIRECTION OUTPUT ;
    USE SIGNAL ;
    PORT
      LAYER M4 ;
        RECT  86.208 16.332 86.4 16.356 ;
    END
  END prm[67]
  PIN prm[680]
    DIRECTION OUTPUT ;
    USE SIGNAL ;
    PORT
      LAYER M5 ;
        RECT  65.58 86.208 65.604 86.4 ;
    END
  END prm[680]
  PIN prm[681]
    DIRECTION OUTPUT ;
    USE SIGNAL ;
    PORT
      LAYER M5 ;
        RECT  65.82 86.208 65.844 86.4 ;
    END
  END prm[681]
  PIN prm[682]
    DIRECTION OUTPUT ;
    USE SIGNAL ;
    PORT
      LAYER M5 ;
        RECT  66.012 86.208 66.036 86.4 ;
    END
  END prm[682]
  PIN prm[683]
    DIRECTION OUTPUT ;
    USE SIGNAL ;
    PORT
      LAYER M5 ;
        RECT  66.252 86.208 66.276 86.4 ;
    END
  END prm[683]
  PIN prm[684]
    DIRECTION OUTPUT ;
    USE SIGNAL ;
    PORT
      LAYER M5 ;
        RECT  66.444 86.208 66.468 86.4 ;
    END
  END prm[684]
  PIN prm[685]
    DIRECTION OUTPUT ;
    USE SIGNAL ;
    PORT
      LAYER M5 ;
        RECT  66.636 86.208 66.66 86.4 ;
    END
  END prm[685]
  PIN prm[686]
    DIRECTION OUTPUT ;
    USE SIGNAL ;
    PORT
      LAYER M5 ;
        RECT  66.876 86.208 66.9 86.4 ;
    END
  END prm[686]
  PIN prm[687]
    DIRECTION OUTPUT ;
    USE SIGNAL ;
    PORT
      LAYER M5 ;
        RECT  67.068 86.208 67.092 86.4 ;
    END
  END prm[687]
  PIN prm[688]
    DIRECTION OUTPUT ;
    USE SIGNAL ;
    PORT
      LAYER M5 ;
        RECT  67.308 86.208 67.332 86.4 ;
    END
  END prm[688]
  PIN prm[689]
    DIRECTION OUTPUT ;
    USE SIGNAL ;
    PORT
      LAYER M5 ;
        RECT  67.5 86.208 67.524 86.4 ;
    END
  END prm[689]
  PIN prm[68]
    DIRECTION OUTPUT ;
    USE SIGNAL ;
    PORT
      LAYER M4 ;
        RECT  86.208 16.572 86.4 16.596 ;
    END
  END prm[68]
  PIN prm[690]
    DIRECTION OUTPUT ;
    USE SIGNAL ;
    PORT
      LAYER M5 ;
        RECT  67.692 86.208 67.716 86.4 ;
    END
  END prm[690]
  PIN prm[691]
    DIRECTION OUTPUT ;
    USE SIGNAL ;
    PORT
      LAYER M5 ;
        RECT  67.932 86.208 67.956 86.4 ;
    END
  END prm[691]
  PIN prm[692]
    DIRECTION OUTPUT ;
    USE SIGNAL ;
    PORT
      LAYER M5 ;
        RECT  68.124 86.208 68.148 86.4 ;
    END
  END prm[692]
  PIN prm[693]
    DIRECTION OUTPUT ;
    USE SIGNAL ;
    PORT
      LAYER M5 ;
        RECT  68.364 86.208 68.388 86.4 ;
    END
  END prm[693]
  PIN prm[694]
    DIRECTION OUTPUT ;
    USE SIGNAL ;
    PORT
      LAYER M5 ;
        RECT  68.556 86.208 68.58 86.4 ;
    END
  END prm[694]
  PIN prm[695]
    DIRECTION OUTPUT ;
    USE SIGNAL ;
    PORT
      LAYER M5 ;
        RECT  68.748 86.208 68.772 86.4 ;
    END
  END prm[695]
  PIN prm[696]
    DIRECTION OUTPUT ;
    USE SIGNAL ;
    PORT
      LAYER M5 ;
        RECT  68.988 86.208 69.012 86.4 ;
    END
  END prm[696]
  PIN prm[697]
    DIRECTION OUTPUT ;
    USE SIGNAL ;
    PORT
      LAYER M5 ;
        RECT  69.18 86.208 69.204 86.4 ;
    END
  END prm[697]
  PIN prm[698]
    DIRECTION OUTPUT ;
    USE SIGNAL ;
    PORT
      LAYER M5 ;
        RECT  69.42 86.208 69.444 86.4 ;
    END
  END prm[698]
  PIN prm[699]
    DIRECTION OUTPUT ;
    USE SIGNAL ;
    PORT
      LAYER M5 ;
        RECT  69.612 86.208 69.636 86.4 ;
    END
  END prm[699]
  PIN prm[69]
    DIRECTION OUTPUT ;
    USE SIGNAL ;
    PORT
      LAYER M4 ;
        RECT  86.208 16.764 86.4 16.788 ;
    END
  END prm[69]
  PIN prm[6]
    DIRECTION OUTPUT ;
    USE SIGNAL ;
    PORT
      LAYER M4 ;
        RECT  86.208 3.42 86.4 3.444 ;
    END
  END prm[6]
  PIN prm[700]
    DIRECTION OUTPUT ;
    USE SIGNAL ;
    PORT
      LAYER M5 ;
        RECT  69.804 86.208 69.828 86.4 ;
    END
  END prm[700]
  PIN prm[701]
    DIRECTION OUTPUT ;
    USE SIGNAL ;
    PORT
      LAYER M5 ;
        RECT  70.044 86.208 70.068 86.4 ;
    END
  END prm[701]
  PIN prm[702]
    DIRECTION OUTPUT ;
    USE SIGNAL ;
    PORT
      LAYER M5 ;
        RECT  70.236 86.208 70.26 86.4 ;
    END
  END prm[702]
  PIN prm[703]
    DIRECTION OUTPUT ;
    USE SIGNAL ;
    PORT
      LAYER M5 ;
        RECT  70.476 86.208 70.5 86.4 ;
    END
  END prm[703]
  PIN prm[704]
    DIRECTION OUTPUT ;
    USE SIGNAL ;
    PORT
      LAYER M5 ;
        RECT  70.668 86.208 70.692 86.4 ;
    END
  END prm[704]
  PIN prm[705]
    DIRECTION OUTPUT ;
    USE SIGNAL ;
    PORT
      LAYER M5 ;
        RECT  70.908 86.208 70.932 86.4 ;
    END
  END prm[705]
  PIN prm[706]
    DIRECTION OUTPUT ;
    USE SIGNAL ;
    PORT
      LAYER M5 ;
        RECT  71.1 86.208 71.124 86.4 ;
    END
  END prm[706]
  PIN prm[707]
    DIRECTION OUTPUT ;
    USE SIGNAL ;
    PORT
      LAYER M5 ;
        RECT  71.292 86.208 71.316 86.4 ;
    END
  END prm[707]
  PIN prm[708]
    DIRECTION OUTPUT ;
    USE SIGNAL ;
    PORT
      LAYER M5 ;
        RECT  71.532 86.208 71.556 86.4 ;
    END
  END prm[708]
  PIN prm[709]
    DIRECTION OUTPUT ;
    USE SIGNAL ;
    PORT
      LAYER M5 ;
        RECT  71.724 86.208 71.748 86.4 ;
    END
  END prm[709]
  PIN prm[70]
    DIRECTION OUTPUT ;
    USE SIGNAL ;
    PORT
      LAYER M4 ;
        RECT  86.208 16.956 86.4 16.98 ;
    END
  END prm[70]
  PIN prm[710]
    DIRECTION OUTPUT ;
    USE SIGNAL ;
    PORT
      LAYER M5 ;
        RECT  71.964 86.208 71.988 86.4 ;
    END
  END prm[710]
  PIN prm[711]
    DIRECTION OUTPUT ;
    USE SIGNAL ;
    PORT
      LAYER M5 ;
        RECT  72.156 86.208 72.18 86.4 ;
    END
  END prm[711]
  PIN prm[712]
    DIRECTION OUTPUT ;
    USE SIGNAL ;
    PORT
      LAYER M5 ;
        RECT  72.348 86.208 72.372 86.4 ;
    END
  END prm[712]
  PIN prm[713]
    DIRECTION OUTPUT ;
    USE SIGNAL ;
    PORT
      LAYER M5 ;
        RECT  72.588 86.208 72.612 86.4 ;
    END
  END prm[713]
  PIN prm[714]
    DIRECTION OUTPUT ;
    USE SIGNAL ;
    PORT
      LAYER M5 ;
        RECT  72.78 86.208 72.804 86.4 ;
    END
  END prm[714]
  PIN prm[715]
    DIRECTION OUTPUT ;
    USE SIGNAL ;
    PORT
      LAYER M5 ;
        RECT  73.02 86.208 73.044 86.4 ;
    END
  END prm[715]
  PIN prm[716]
    DIRECTION OUTPUT ;
    USE SIGNAL ;
    PORT
      LAYER M5 ;
        RECT  73.212 86.208 73.236 86.4 ;
    END
  END prm[716]
  PIN prm[717]
    DIRECTION OUTPUT ;
    USE SIGNAL ;
    PORT
      LAYER M5 ;
        RECT  73.404 86.208 73.428 86.4 ;
    END
  END prm[717]
  PIN prm[718]
    DIRECTION OUTPUT ;
    USE SIGNAL ;
    PORT
      LAYER M5 ;
        RECT  73.644 86.208 73.668 86.4 ;
    END
  END prm[718]
  PIN prm[719]
    DIRECTION OUTPUT ;
    USE SIGNAL ;
    PORT
      LAYER M5 ;
        RECT  73.836 86.208 73.86 86.4 ;
    END
  END prm[719]
  PIN prm[71]
    DIRECTION OUTPUT ;
    USE SIGNAL ;
    PORT
      LAYER M4 ;
        RECT  86.208 17.196 86.4 17.22 ;
    END
  END prm[71]
  PIN prm[720]
    DIRECTION OUTPUT ;
    USE SIGNAL ;
    PORT
      LAYER M5 ;
        RECT  74.076 86.208 74.1 86.4 ;
    END
  END prm[720]
  PIN prm[721]
    DIRECTION OUTPUT ;
    USE SIGNAL ;
    PORT
      LAYER M5 ;
        RECT  74.268 86.208 74.292 86.4 ;
    END
  END prm[721]
  PIN prm[722]
    DIRECTION OUTPUT ;
    USE SIGNAL ;
    PORT
      LAYER M5 ;
        RECT  74.46 86.208 74.484 86.4 ;
    END
  END prm[722]
  PIN prm[723]
    DIRECTION OUTPUT ;
    USE SIGNAL ;
    PORT
      LAYER M5 ;
        RECT  74.7 86.208 74.724 86.4 ;
    END
  END prm[723]
  PIN prm[724]
    DIRECTION OUTPUT ;
    USE SIGNAL ;
    PORT
      LAYER M5 ;
        RECT  74.892 86.208 74.916 86.4 ;
    END
  END prm[724]
  PIN prm[725]
    DIRECTION OUTPUT ;
    USE SIGNAL ;
    PORT
      LAYER M5 ;
        RECT  75.132 86.208 75.156 86.4 ;
    END
  END prm[725]
  PIN prm[726]
    DIRECTION OUTPUT ;
    USE SIGNAL ;
    PORT
      LAYER M5 ;
        RECT  75.324 86.208 75.348 86.4 ;
    END
  END prm[726]
  PIN prm[727]
    DIRECTION OUTPUT ;
    USE SIGNAL ;
    PORT
      LAYER M5 ;
        RECT  75.516 86.208 75.54 86.4 ;
    END
  END prm[727]
  PIN prm[728]
    DIRECTION OUTPUT ;
    USE SIGNAL ;
    PORT
      LAYER M5 ;
        RECT  75.756 86.208 75.78 86.4 ;
    END
  END prm[728]
  PIN prm[729]
    DIRECTION OUTPUT ;
    USE SIGNAL ;
    PORT
      LAYER M5 ;
        RECT  75.948 86.208 75.972 86.4 ;
    END
  END prm[729]
  PIN prm[72]
    DIRECTION OUTPUT ;
    USE SIGNAL ;
    PORT
      LAYER M4 ;
        RECT  86.208 17.388 86.4 17.412 ;
    END
  END prm[72]
  PIN prm[730]
    DIRECTION OUTPUT ;
    USE SIGNAL ;
    PORT
      LAYER M5 ;
        RECT  76.188 86.208 76.212 86.4 ;
    END
  END prm[730]
  PIN prm[731]
    DIRECTION OUTPUT ;
    USE SIGNAL ;
    PORT
      LAYER M5 ;
        RECT  76.38 86.208 76.404 86.4 ;
    END
  END prm[731]
  PIN prm[732]
    DIRECTION OUTPUT ;
    USE SIGNAL ;
    PORT
      LAYER M5 ;
        RECT  76.572 86.208 76.596 86.4 ;
    END
  END prm[732]
  PIN prm[733]
    DIRECTION OUTPUT ;
    USE SIGNAL ;
    PORT
      LAYER M5 ;
        RECT  76.812 86.208 76.836 86.4 ;
    END
  END prm[733]
  PIN prm[734]
    DIRECTION OUTPUT ;
    USE SIGNAL ;
    PORT
      LAYER M5 ;
        RECT  77.004 86.208 77.028 86.4 ;
    END
  END prm[734]
  PIN prm[735]
    DIRECTION OUTPUT ;
    USE SIGNAL ;
    PORT
      LAYER M5 ;
        RECT  77.244 86.208 77.268 86.4 ;
    END
  END prm[735]
  PIN prm[736]
    DIRECTION OUTPUT ;
    USE SIGNAL ;
    PORT
      LAYER M5 ;
        RECT  77.436 86.208 77.46 86.4 ;
    END
  END prm[736]
  PIN prm[737]
    DIRECTION OUTPUT ;
    USE SIGNAL ;
    PORT
      LAYER M5 ;
        RECT  77.628 86.208 77.652 86.4 ;
    END
  END prm[737]
  PIN prm[738]
    DIRECTION OUTPUT ;
    USE SIGNAL ;
    PORT
      LAYER M5 ;
        RECT  77.868 86.208 77.892 86.4 ;
    END
  END prm[738]
  PIN prm[739]
    DIRECTION OUTPUT ;
    USE SIGNAL ;
    PORT
      LAYER M5 ;
        RECT  78.06 86.208 78.084 86.4 ;
    END
  END prm[739]
  PIN prm[73]
    DIRECTION OUTPUT ;
    USE SIGNAL ;
    PORT
      LAYER M4 ;
        RECT  86.208 17.628 86.4 17.652 ;
    END
  END prm[73]
  PIN prm[740]
    DIRECTION OUTPUT ;
    USE SIGNAL ;
    PORT
      LAYER M5 ;
        RECT  78.3 86.208 78.324 86.4 ;
    END
  END prm[740]
  PIN prm[741]
    DIRECTION OUTPUT ;
    USE SIGNAL ;
    PORT
      LAYER M5 ;
        RECT  78.492 86.208 78.516 86.4 ;
    END
  END prm[741]
  PIN prm[742]
    DIRECTION OUTPUT ;
    USE SIGNAL ;
    PORT
      LAYER M5 ;
        RECT  78.684 86.208 78.708 86.4 ;
    END
  END prm[742]
  PIN prm[743]
    DIRECTION OUTPUT ;
    USE SIGNAL ;
    PORT
      LAYER M5 ;
        RECT  78.924 86.208 78.948 86.4 ;
    END
  END prm[743]
  PIN prm[744]
    DIRECTION OUTPUT ;
    USE SIGNAL ;
    PORT
      LAYER M5 ;
        RECT  79.116 86.208 79.14 86.4 ;
    END
  END prm[744]
  PIN prm[745]
    DIRECTION OUTPUT ;
    USE SIGNAL ;
    PORT
      LAYER M5 ;
        RECT  79.356 86.208 79.38 86.4 ;
    END
  END prm[745]
  PIN prm[746]
    DIRECTION OUTPUT ;
    USE SIGNAL ;
    PORT
      LAYER M5 ;
        RECT  79.548 86.208 79.572 86.4 ;
    END
  END prm[746]
  PIN prm[747]
    DIRECTION OUTPUT ;
    USE SIGNAL ;
    PORT
      LAYER M5 ;
        RECT  79.788 86.208 79.812 86.4 ;
    END
  END prm[747]
  PIN prm[748]
    DIRECTION OUTPUT ;
    USE SIGNAL ;
    PORT
      LAYER M5 ;
        RECT  79.98 86.208 80.004 86.4 ;
    END
  END prm[748]
  PIN prm[749]
    DIRECTION OUTPUT ;
    USE SIGNAL ;
    PORT
      LAYER M5 ;
        RECT  80.172 86.208 80.196 86.4 ;
    END
  END prm[749]
  PIN prm[74]
    DIRECTION OUTPUT ;
    USE SIGNAL ;
    PORT
      LAYER M4 ;
        RECT  86.208 17.82 86.4 17.844 ;
    END
  END prm[74]
  PIN prm[750]
    DIRECTION OUTPUT ;
    USE SIGNAL ;
    PORT
      LAYER M5 ;
        RECT  80.412 86.208 80.436 86.4 ;
    END
  END prm[750]
  PIN prm[751]
    DIRECTION OUTPUT ;
    USE SIGNAL ;
    PORT
      LAYER M5 ;
        RECT  80.604 86.208 80.628 86.4 ;
    END
  END prm[751]
  PIN prm[752]
    DIRECTION OUTPUT ;
    USE SIGNAL ;
    PORT
      LAYER M5 ;
        RECT  80.844 86.208 80.868 86.4 ;
    END
  END prm[752]
  PIN prm[753]
    DIRECTION OUTPUT ;
    USE SIGNAL ;
    PORT
      LAYER M5 ;
        RECT  81.036 86.208 81.06 86.4 ;
    END
  END prm[753]
  PIN prm[754]
    DIRECTION OUTPUT ;
    USE SIGNAL ;
    PORT
      LAYER M5 ;
        RECT  81.228 86.208 81.252 86.4 ;
    END
  END prm[754]
  PIN prm[755]
    DIRECTION OUTPUT ;
    USE SIGNAL ;
    PORT
      LAYER M5 ;
        RECT  81.468 86.208 81.492 86.4 ;
    END
  END prm[755]
  PIN prm[756]
    DIRECTION OUTPUT ;
    USE SIGNAL ;
    PORT
      LAYER M5 ;
        RECT  81.66 86.208 81.684 86.4 ;
    END
  END prm[756]
  PIN prm[757]
    DIRECTION OUTPUT ;
    USE SIGNAL ;
    PORT
      LAYER M5 ;
        RECT  81.9 86.208 81.924 86.4 ;
    END
  END prm[757]
  PIN prm[758]
    DIRECTION OUTPUT ;
    USE SIGNAL ;
    PORT
      LAYER M5 ;
        RECT  82.092 86.208 82.116 86.4 ;
    END
  END prm[758]
  PIN prm[759]
    DIRECTION OUTPUT ;
    USE SIGNAL ;
    PORT
      LAYER M5 ;
        RECT  82.284 86.208 82.308 86.4 ;
    END
  END prm[759]
  PIN prm[75]
    DIRECTION OUTPUT ;
    USE SIGNAL ;
    PORT
      LAYER M4 ;
        RECT  86.208 18.012 86.4 18.036 ;
    END
  END prm[75]
  PIN prm[760]
    DIRECTION OUTPUT ;
    USE SIGNAL ;
    PORT
      LAYER M5 ;
        RECT  82.524 86.208 82.548 86.4 ;
    END
  END prm[760]
  PIN prm[761]
    DIRECTION OUTPUT ;
    USE SIGNAL ;
    PORT
      LAYER M5 ;
        RECT  82.716 86.208 82.74 86.4 ;
    END
  END prm[761]
  PIN prm[762]
    DIRECTION OUTPUT ;
    USE SIGNAL ;
    PORT
      LAYER M5 ;
        RECT  82.956 86.208 82.98 86.4 ;
    END
  END prm[762]
  PIN prm[763]
    DIRECTION OUTPUT ;
    USE SIGNAL ;
    PORT
      LAYER M5 ;
        RECT  83.148 86.208 83.172 86.4 ;
    END
  END prm[763]
  PIN prm[764]
    DIRECTION OUTPUT ;
    USE SIGNAL ;
    PORT
      LAYER M5 ;
        RECT  83.34 86.208 83.364 86.4 ;
    END
  END prm[764]
  PIN prm[765]
    DIRECTION OUTPUT ;
    USE SIGNAL ;
    PORT
      LAYER M5 ;
        RECT  83.58 86.208 83.604 86.4 ;
    END
  END prm[765]
  PIN prm[766]
    DIRECTION OUTPUT ;
    USE SIGNAL ;
    PORT
      LAYER M5 ;
        RECT  83.772 86.208 83.796 86.4 ;
    END
  END prm[766]
  PIN prm[767]
    DIRECTION OUTPUT ;
    USE SIGNAL ;
    PORT
      LAYER M5 ;
        RECT  84.012 86.208 84.036 86.4 ;
    END
  END prm[767]
  PIN prm[768]
    DIRECTION OUTPUT ;
    USE SIGNAL ;
    PORT
      LAYER M5 ;
        RECT  84.204 86.208 84.228 86.4 ;
    END
  END prm[768]
  PIN prm[76]
    DIRECTION OUTPUT ;
    USE SIGNAL ;
    PORT
      LAYER M4 ;
        RECT  86.208 18.252 86.4 18.276 ;
    END
  END prm[76]
  PIN prm[77]
    DIRECTION OUTPUT ;
    USE SIGNAL ;
    PORT
      LAYER M4 ;
        RECT  86.208 18.444 86.4 18.468 ;
    END
  END prm[77]
  PIN prm[78]
    DIRECTION OUTPUT ;
    USE SIGNAL ;
    PORT
      LAYER M4 ;
        RECT  86.208 18.684 86.4 18.708 ;
    END
  END prm[78]
  PIN prm[79]
    DIRECTION OUTPUT ;
    USE SIGNAL ;
    PORT
      LAYER M4 ;
        RECT  86.208 18.876 86.4 18.9 ;
    END
  END prm[79]
  PIN prm[7]
    DIRECTION OUTPUT ;
    USE SIGNAL ;
    PORT
      LAYER M4 ;
        RECT  86.208 3.66 86.4 3.684 ;
    END
  END prm[7]
  PIN prm[80]
    DIRECTION OUTPUT ;
    USE SIGNAL ;
    PORT
      LAYER M4 ;
        RECT  86.208 19.068 86.4 19.092 ;
    END
  END prm[80]
  PIN prm[81]
    DIRECTION OUTPUT ;
    USE SIGNAL ;
    PORT
      LAYER M4 ;
        RECT  86.208 19.308 86.4 19.332 ;
    END
  END prm[81]
  PIN prm[82]
    DIRECTION OUTPUT ;
    USE SIGNAL ;
    PORT
      LAYER M4 ;
        RECT  86.208 19.5 86.4 19.524 ;
    END
  END prm[82]
  PIN prm[83]
    DIRECTION OUTPUT ;
    USE SIGNAL ;
    PORT
      LAYER M4 ;
        RECT  86.208 19.74 86.4 19.764 ;
    END
  END prm[83]
  PIN prm[84]
    DIRECTION OUTPUT ;
    USE SIGNAL ;
    PORT
      LAYER M4 ;
        RECT  86.208 19.932 86.4 19.956 ;
    END
  END prm[84]
  PIN prm[85]
    DIRECTION OUTPUT ;
    USE SIGNAL ;
    PORT
      LAYER M4 ;
        RECT  86.208 20.124 86.4 20.148 ;
    END
  END prm[85]
  PIN prm[86]
    DIRECTION OUTPUT ;
    USE SIGNAL ;
    PORT
      LAYER M4 ;
        RECT  86.208 20.364 86.4 20.388 ;
    END
  END prm[86]
  PIN prm[87]
    DIRECTION OUTPUT ;
    USE SIGNAL ;
    PORT
      LAYER M4 ;
        RECT  86.208 20.556 86.4 20.58 ;
    END
  END prm[87]
  PIN prm[88]
    DIRECTION OUTPUT ;
    USE SIGNAL ;
    PORT
      LAYER M4 ;
        RECT  86.208 20.796 86.4 20.82 ;
    END
  END prm[88]
  PIN prm[89]
    DIRECTION OUTPUT ;
    USE SIGNAL ;
    PORT
      LAYER M4 ;
        RECT  86.208 20.988 86.4 21.012 ;
    END
  END prm[89]
  PIN prm[8]
    DIRECTION OUTPUT ;
    USE SIGNAL ;
    PORT
      LAYER M4 ;
        RECT  86.208 3.852 86.4 3.876 ;
    END
  END prm[8]
  PIN prm[90]
    DIRECTION OUTPUT ;
    USE SIGNAL ;
    PORT
      LAYER M4 ;
        RECT  86.208 21.18 86.4 21.204 ;
    END
  END prm[90]
  PIN prm[91]
    DIRECTION OUTPUT ;
    USE SIGNAL ;
    PORT
      LAYER M4 ;
        RECT  86.208 21.42 86.4 21.444 ;
    END
  END prm[91]
  PIN prm[92]
    DIRECTION OUTPUT ;
    USE SIGNAL ;
    PORT
      LAYER M4 ;
        RECT  86.208 21.612 86.4 21.636 ;
    END
  END prm[92]
  PIN prm[93]
    DIRECTION OUTPUT ;
    USE SIGNAL ;
    PORT
      LAYER M4 ;
        RECT  86.208 21.852 86.4 21.876 ;
    END
  END prm[93]
  PIN prm[94]
    DIRECTION OUTPUT ;
    USE SIGNAL ;
    PORT
      LAYER M4 ;
        RECT  86.208 22.044 86.4 22.068 ;
    END
  END prm[94]
  PIN prm[95]
    DIRECTION OUTPUT ;
    USE SIGNAL ;
    PORT
      LAYER M4 ;
        RECT  86.208 22.236 86.4 22.26 ;
    END
  END prm[95]
  PIN prm[96]
    DIRECTION OUTPUT ;
    USE SIGNAL ;
    PORT
      LAYER M4 ;
        RECT  86.208 22.476 86.4 22.5 ;
    END
  END prm[96]
  PIN prm[97]
    DIRECTION OUTPUT ;
    USE SIGNAL ;
    PORT
      LAYER M4 ;
        RECT  86.208 22.668 86.4 22.692 ;
    END
  END prm[97]
  PIN prm[98]
    DIRECTION OUTPUT ;
    USE SIGNAL ;
    PORT
      LAYER M4 ;
        RECT  86.208 22.908 86.4 22.932 ;
    END
  END prm[98]
  PIN prm[99]
    DIRECTION OUTPUT ;
    USE SIGNAL ;
    PORT
      LAYER M4 ;
        RECT  86.208 23.1 86.4 23.124 ;
    END
  END prm[99]
  PIN prm[9]
    DIRECTION OUTPUT ;
    USE SIGNAL ;
    PORT
      LAYER M4 ;
        RECT  86.208 4.092 86.4 4.116 ;
    END
  END prm[9]
  PIN pw_addr[0]
    DIRECTION OUTPUT ;
    USE SIGNAL ;
    PORT
      LAYER M5 ;
        RECT  62.412 86.208 62.436 86.4 ;
    END
  END pw_addr[0]
  PIN pw_addr[1]
    DIRECTION OUTPUT ;
    USE SIGNAL ;
    PORT
      LAYER M5 ;
        RECT  62.652 86.208 62.676 86.4 ;
    END
  END pw_addr[1]
  PIN pw_addr[2]
    DIRECTION OUTPUT ;
    USE SIGNAL ;
    PORT
      LAYER M5 ;
        RECT  62.844 86.208 62.868 86.4 ;
    END
  END pw_addr[2]
  PIN pw_addr[3]
    DIRECTION OUTPUT ;
    USE SIGNAL ;
    PORT
      LAYER M5 ;
        RECT  63.084 86.208 63.108 86.4 ;
    END
  END pw_addr[3]
  PIN pw_addr[4]
    DIRECTION OUTPUT ;
    USE SIGNAL ;
    PORT
      LAYER M5 ;
        RECT  63.276 86.208 63.3 86.4 ;
    END
  END pw_addr[4]
  PIN pw_addr[5]
    DIRECTION OUTPUT ;
    USE SIGNAL ;
    PORT
      LAYER M5 ;
        RECT  63.468 86.208 63.492 86.4 ;
    END
  END pw_addr[5]
  PIN pw_addr[6]
    DIRECTION OUTPUT ;
    USE SIGNAL ;
    PORT
      LAYER M5 ;
        RECT  63.708 86.208 63.732 86.4 ;
    END
  END pw_addr[6]
  PIN pw_addr[7]
    DIRECTION OUTPUT ;
    USE SIGNAL ;
    PORT
      LAYER M5 ;
        RECT  63.9 86.208 63.924 86.4 ;
    END
  END pw_addr[7]
  PIN pw_data[0]
    DIRECTION OUTPUT ;
    USE SIGNAL ;
    PORT
      LAYER M4 ;
        RECT  0 53.148 0.192 53.172 ;
    END
  END pw_data[0]
  PIN pw_data[100]
    DIRECTION OUTPUT ;
    USE SIGNAL ;
    PORT
      LAYER M4 ;
        RECT  0 74.268 0.192 74.292 ;
    END
  END pw_data[100]
  PIN pw_data[101]
    DIRECTION OUTPUT ;
    USE SIGNAL ;
    PORT
      LAYER M4 ;
        RECT  0 74.46 0.192 74.484 ;
    END
  END pw_data[101]
  PIN pw_data[102]
    DIRECTION OUTPUT ;
    USE SIGNAL ;
    PORT
      LAYER M4 ;
        RECT  0 74.7 0.192 74.724 ;
    END
  END pw_data[102]
  PIN pw_data[103]
    DIRECTION OUTPUT ;
    USE SIGNAL ;
    PORT
      LAYER M4 ;
        RECT  0 74.892 0.192 74.916 ;
    END
  END pw_data[103]
  PIN pw_data[104]
    DIRECTION OUTPUT ;
    USE SIGNAL ;
    PORT
      LAYER M4 ;
        RECT  0 75.132 0.192 75.156 ;
    END
  END pw_data[104]
  PIN pw_data[105]
    DIRECTION OUTPUT ;
    USE SIGNAL ;
    PORT
      LAYER M4 ;
        RECT  0 75.324 0.192 75.348 ;
    END
  END pw_data[105]
  PIN pw_data[106]
    DIRECTION OUTPUT ;
    USE SIGNAL ;
    PORT
      LAYER M4 ;
        RECT  0 75.516 0.192 75.54 ;
    END
  END pw_data[106]
  PIN pw_data[107]
    DIRECTION OUTPUT ;
    USE SIGNAL ;
    PORT
      LAYER M4 ;
        RECT  0 75.756 0.192 75.78 ;
    END
  END pw_data[107]
  PIN pw_data[108]
    DIRECTION OUTPUT ;
    USE SIGNAL ;
    PORT
      LAYER M4 ;
        RECT  0 75.948 0.192 75.972 ;
    END
  END pw_data[108]
  PIN pw_data[109]
    DIRECTION OUTPUT ;
    USE SIGNAL ;
    PORT
      LAYER M4 ;
        RECT  0 76.188 0.192 76.212 ;
    END
  END pw_data[109]
  PIN pw_data[10]
    DIRECTION OUTPUT ;
    USE SIGNAL ;
    PORT
      LAYER M4 ;
        RECT  0 55.26 0.192 55.284 ;
    END
  END pw_data[10]
  PIN pw_data[110]
    DIRECTION OUTPUT ;
    USE SIGNAL ;
    PORT
      LAYER M4 ;
        RECT  0 76.38 0.192 76.404 ;
    END
  END pw_data[110]
  PIN pw_data[111]
    DIRECTION OUTPUT ;
    USE SIGNAL ;
    PORT
      LAYER M4 ;
        RECT  0 76.572 0.192 76.596 ;
    END
  END pw_data[111]
  PIN pw_data[112]
    DIRECTION OUTPUT ;
    USE SIGNAL ;
    PORT
      LAYER M4 ;
        RECT  0 76.812 0.192 76.836 ;
    END
  END pw_data[112]
  PIN pw_data[113]
    DIRECTION OUTPUT ;
    USE SIGNAL ;
    PORT
      LAYER M4 ;
        RECT  0 77.004 0.192 77.028 ;
    END
  END pw_data[113]
  PIN pw_data[114]
    DIRECTION OUTPUT ;
    USE SIGNAL ;
    PORT
      LAYER M4 ;
        RECT  0 77.244 0.192 77.268 ;
    END
  END pw_data[114]
  PIN pw_data[115]
    DIRECTION OUTPUT ;
    USE SIGNAL ;
    PORT
      LAYER M4 ;
        RECT  0 77.436 0.192 77.46 ;
    END
  END pw_data[115]
  PIN pw_data[116]
    DIRECTION OUTPUT ;
    USE SIGNAL ;
    PORT
      LAYER M4 ;
        RECT  0 77.628 0.192 77.652 ;
    END
  END pw_data[116]
  PIN pw_data[117]
    DIRECTION OUTPUT ;
    USE SIGNAL ;
    PORT
      LAYER M4 ;
        RECT  0 77.868 0.192 77.892 ;
    END
  END pw_data[117]
  PIN pw_data[118]
    DIRECTION OUTPUT ;
    USE SIGNAL ;
    PORT
      LAYER M4 ;
        RECT  0 78.06 0.192 78.084 ;
    END
  END pw_data[118]
  PIN pw_data[119]
    DIRECTION OUTPUT ;
    USE SIGNAL ;
    PORT
      LAYER M4 ;
        RECT  0 78.3 0.192 78.324 ;
    END
  END pw_data[119]
  PIN pw_data[11]
    DIRECTION OUTPUT ;
    USE SIGNAL ;
    PORT
      LAYER M4 ;
        RECT  0 55.452 0.192 55.476 ;
    END
  END pw_data[11]
  PIN pw_data[120]
    DIRECTION OUTPUT ;
    USE SIGNAL ;
    PORT
      LAYER M4 ;
        RECT  0 78.492 0.192 78.516 ;
    END
  END pw_data[120]
  PIN pw_data[121]
    DIRECTION OUTPUT ;
    USE SIGNAL ;
    PORT
      LAYER M4 ;
        RECT  0 78.684 0.192 78.708 ;
    END
  END pw_data[121]
  PIN pw_data[122]
    DIRECTION OUTPUT ;
    USE SIGNAL ;
    PORT
      LAYER M4 ;
        RECT  0 78.924 0.192 78.948 ;
    END
  END pw_data[122]
  PIN pw_data[123]
    DIRECTION OUTPUT ;
    USE SIGNAL ;
    PORT
      LAYER M4 ;
        RECT  0 79.116 0.192 79.14 ;
    END
  END pw_data[123]
  PIN pw_data[124]
    DIRECTION OUTPUT ;
    USE SIGNAL ;
    PORT
      LAYER M4 ;
        RECT  0 79.356 0.192 79.38 ;
    END
  END pw_data[124]
  PIN pw_data[125]
    DIRECTION OUTPUT ;
    USE SIGNAL ;
    PORT
      LAYER M4 ;
        RECT  0 79.548 0.192 79.572 ;
    END
  END pw_data[125]
  PIN pw_data[126]
    DIRECTION OUTPUT ;
    USE SIGNAL ;
    PORT
      LAYER M4 ;
        RECT  0 79.788 0.192 79.812 ;
    END
  END pw_data[126]
  PIN pw_data[127]
    DIRECTION OUTPUT ;
    USE SIGNAL ;
    PORT
      LAYER M4 ;
        RECT  0 79.98 0.192 80.004 ;
    END
  END pw_data[127]
  PIN pw_data[128]
    DIRECTION OUTPUT ;
    USE SIGNAL ;
    PORT
      LAYER M4 ;
        RECT  0 80.172 0.192 80.196 ;
    END
  END pw_data[128]
  PIN pw_data[129]
    DIRECTION OUTPUT ;
    USE SIGNAL ;
    PORT
      LAYER M4 ;
        RECT  0 80.412 0.192 80.436 ;
    END
  END pw_data[129]
  PIN pw_data[12]
    DIRECTION OUTPUT ;
    USE SIGNAL ;
    PORT
      LAYER M4 ;
        RECT  0 55.644 0.192 55.668 ;
    END
  END pw_data[12]
  PIN pw_data[130]
    DIRECTION OUTPUT ;
    USE SIGNAL ;
    PORT
      LAYER M4 ;
        RECT  0 80.604 0.192 80.628 ;
    END
  END pw_data[130]
  PIN pw_data[131]
    DIRECTION OUTPUT ;
    USE SIGNAL ;
    PORT
      LAYER M4 ;
        RECT  0 80.844 0.192 80.868 ;
    END
  END pw_data[131]
  PIN pw_data[132]
    DIRECTION OUTPUT ;
    USE SIGNAL ;
    PORT
      LAYER M4 ;
        RECT  0 81.036 0.192 81.06 ;
    END
  END pw_data[132]
  PIN pw_data[133]
    DIRECTION OUTPUT ;
    USE SIGNAL ;
    PORT
      LAYER M4 ;
        RECT  0 81.228 0.192 81.252 ;
    END
  END pw_data[133]
  PIN pw_data[134]
    DIRECTION OUTPUT ;
    USE SIGNAL ;
    PORT
      LAYER M4 ;
        RECT  0 81.468 0.192 81.492 ;
    END
  END pw_data[134]
  PIN pw_data[135]
    DIRECTION OUTPUT ;
    USE SIGNAL ;
    PORT
      LAYER M4 ;
        RECT  0 81.66 0.192 81.684 ;
    END
  END pw_data[135]
  PIN pw_data[136]
    DIRECTION OUTPUT ;
    USE SIGNAL ;
    PORT
      LAYER M4 ;
        RECT  0 81.9 0.192 81.924 ;
    END
  END pw_data[136]
  PIN pw_data[137]
    DIRECTION OUTPUT ;
    USE SIGNAL ;
    PORT
      LAYER M4 ;
        RECT  0 82.092 0.192 82.116 ;
    END
  END pw_data[137]
  PIN pw_data[138]
    DIRECTION OUTPUT ;
    USE SIGNAL ;
    PORT
      LAYER M4 ;
        RECT  0 82.284 0.192 82.308 ;
    END
  END pw_data[138]
  PIN pw_data[139]
    DIRECTION OUTPUT ;
    USE SIGNAL ;
    PORT
      LAYER M4 ;
        RECT  0 82.524 0.192 82.548 ;
    END
  END pw_data[139]
  PIN pw_data[13]
    DIRECTION OUTPUT ;
    USE SIGNAL ;
    PORT
      LAYER M4 ;
        RECT  0 55.884 0.192 55.908 ;
    END
  END pw_data[13]
  PIN pw_data[140]
    DIRECTION OUTPUT ;
    USE SIGNAL ;
    PORT
      LAYER M4 ;
        RECT  0 82.716 0.192 82.74 ;
    END
  END pw_data[140]
  PIN pw_data[141]
    DIRECTION OUTPUT ;
    USE SIGNAL ;
    PORT
      LAYER M4 ;
        RECT  0 82.956 0.192 82.98 ;
    END
  END pw_data[141]
  PIN pw_data[142]
    DIRECTION OUTPUT ;
    USE SIGNAL ;
    PORT
      LAYER M4 ;
        RECT  0 83.148 0.192 83.172 ;
    END
  END pw_data[142]
  PIN pw_data[143]
    DIRECTION OUTPUT ;
    USE SIGNAL ;
    PORT
      LAYER M4 ;
        RECT  0 83.34 0.192 83.364 ;
    END
  END pw_data[143]
  PIN pw_data[144]
    DIRECTION OUTPUT ;
    USE SIGNAL ;
    PORT
      LAYER M4 ;
        RECT  0 83.58 0.192 83.604 ;
    END
  END pw_data[144]
  PIN pw_data[145]
    DIRECTION OUTPUT ;
    USE SIGNAL ;
    PORT
      LAYER M4 ;
        RECT  0 83.772 0.192 83.796 ;
    END
  END pw_data[145]
  PIN pw_data[146]
    DIRECTION OUTPUT ;
    USE SIGNAL ;
    PORT
      LAYER M4 ;
        RECT  0 84.012 0.192 84.036 ;
    END
  END pw_data[146]
  PIN pw_data[147]
    DIRECTION OUTPUT ;
    USE SIGNAL ;
    PORT
      LAYER M4 ;
        RECT  0 84.204 0.192 84.228 ;
    END
  END pw_data[147]
  PIN pw_data[148]
    DIRECTION OUTPUT ;
    USE SIGNAL ;
    PORT
      LAYER M5 ;
        RECT  61.74 0 61.764 0.192 ;
    END
  END pw_data[148]
  PIN pw_data[149]
    DIRECTION OUTPUT ;
    USE SIGNAL ;
    PORT
      LAYER M5 ;
        RECT  61.98 0 62.004 0.192 ;
    END
  END pw_data[149]
  PIN pw_data[14]
    DIRECTION OUTPUT ;
    USE SIGNAL ;
    PORT
      LAYER M4 ;
        RECT  0 56.076 0.192 56.1 ;
    END
  END pw_data[14]
  PIN pw_data[150]
    DIRECTION OUTPUT ;
    USE SIGNAL ;
    PORT
      LAYER M5 ;
        RECT  62.172 0 62.196 0.192 ;
    END
  END pw_data[150]
  PIN pw_data[151]
    DIRECTION OUTPUT ;
    USE SIGNAL ;
    PORT
      LAYER M5 ;
        RECT  62.364 0 62.388 0.192 ;
    END
  END pw_data[151]
  PIN pw_data[152]
    DIRECTION OUTPUT ;
    USE SIGNAL ;
    PORT
      LAYER M5 ;
        RECT  62.604 0 62.628 0.192 ;
    END
  END pw_data[152]
  PIN pw_data[153]
    DIRECTION OUTPUT ;
    USE SIGNAL ;
    PORT
      LAYER M5 ;
        RECT  62.796 0 62.82 0.192 ;
    END
  END pw_data[153]
  PIN pw_data[154]
    DIRECTION OUTPUT ;
    USE SIGNAL ;
    PORT
      LAYER M5 ;
        RECT  63.036 0 63.06 0.192 ;
    END
  END pw_data[154]
  PIN pw_data[155]
    DIRECTION OUTPUT ;
    USE SIGNAL ;
    PORT
      LAYER M5 ;
        RECT  63.228 0 63.252 0.192 ;
    END
  END pw_data[155]
  PIN pw_data[156]
    DIRECTION OUTPUT ;
    USE SIGNAL ;
    PORT
      LAYER M5 ;
        RECT  63.42 0 63.444 0.192 ;
    END
  END pw_data[156]
  PIN pw_data[157]
    DIRECTION OUTPUT ;
    USE SIGNAL ;
    PORT
      LAYER M5 ;
        RECT  63.66 0 63.684 0.192 ;
    END
  END pw_data[157]
  PIN pw_data[158]
    DIRECTION OUTPUT ;
    USE SIGNAL ;
    PORT
      LAYER M5 ;
        RECT  63.852 0 63.876 0.192 ;
    END
  END pw_data[158]
  PIN pw_data[159]
    DIRECTION OUTPUT ;
    USE SIGNAL ;
    PORT
      LAYER M5 ;
        RECT  64.044 0 64.068 0.192 ;
    END
  END pw_data[159]
  PIN pw_data[15]
    DIRECTION OUTPUT ;
    USE SIGNAL ;
    PORT
      LAYER M4 ;
        RECT  0 56.316 0.192 56.34 ;
    END
  END pw_data[15]
  PIN pw_data[160]
    DIRECTION OUTPUT ;
    USE SIGNAL ;
    PORT
      LAYER M5 ;
        RECT  64.284 0 64.308 0.192 ;
    END
  END pw_data[160]
  PIN pw_data[161]
    DIRECTION OUTPUT ;
    USE SIGNAL ;
    PORT
      LAYER M5 ;
        RECT  64.476 0 64.5 0.192 ;
    END
  END pw_data[161]
  PIN pw_data[162]
    DIRECTION OUTPUT ;
    USE SIGNAL ;
    PORT
      LAYER M5 ;
        RECT  64.716 0 64.74 0.192 ;
    END
  END pw_data[162]
  PIN pw_data[163]
    DIRECTION OUTPUT ;
    USE SIGNAL ;
    PORT
      LAYER M5 ;
        RECT  64.908 0 64.932 0.192 ;
    END
  END pw_data[163]
  PIN pw_data[164]
    DIRECTION OUTPUT ;
    USE SIGNAL ;
    PORT
      LAYER M5 ;
        RECT  65.1 0 65.124 0.192 ;
    END
  END pw_data[164]
  PIN pw_data[165]
    DIRECTION OUTPUT ;
    USE SIGNAL ;
    PORT
      LAYER M5 ;
        RECT  65.34 0 65.364 0.192 ;
    END
  END pw_data[165]
  PIN pw_data[166]
    DIRECTION OUTPUT ;
    USE SIGNAL ;
    PORT
      LAYER M5 ;
        RECT  65.532 0 65.556 0.192 ;
    END
  END pw_data[166]
  PIN pw_data[167]
    DIRECTION OUTPUT ;
    USE SIGNAL ;
    PORT
      LAYER M5 ;
        RECT  65.724 0 65.748 0.192 ;
    END
  END pw_data[167]
  PIN pw_data[168]
    DIRECTION OUTPUT ;
    USE SIGNAL ;
    PORT
      LAYER M5 ;
        RECT  65.964 0 65.988 0.192 ;
    END
  END pw_data[168]
  PIN pw_data[169]
    DIRECTION OUTPUT ;
    USE SIGNAL ;
    PORT
      LAYER M5 ;
        RECT  66.156 0 66.18 0.192 ;
    END
  END pw_data[169]
  PIN pw_data[16]
    DIRECTION OUTPUT ;
    USE SIGNAL ;
    PORT
      LAYER M4 ;
        RECT  0 56.508 0.192 56.532 ;
    END
  END pw_data[16]
  PIN pw_data[170]
    DIRECTION OUTPUT ;
    USE SIGNAL ;
    PORT
      LAYER M5 ;
        RECT  66.348 0 66.372 0.192 ;
    END
  END pw_data[170]
  PIN pw_data[171]
    DIRECTION OUTPUT ;
    USE SIGNAL ;
    PORT
      LAYER M5 ;
        RECT  66.588 0 66.612 0.192 ;
    END
  END pw_data[171]
  PIN pw_data[172]
    DIRECTION OUTPUT ;
    USE SIGNAL ;
    PORT
      LAYER M5 ;
        RECT  66.78 0 66.804 0.192 ;
    END
  END pw_data[172]
  PIN pw_data[173]
    DIRECTION OUTPUT ;
    USE SIGNAL ;
    PORT
      LAYER M5 ;
        RECT  67.02 0 67.044 0.192 ;
    END
  END pw_data[173]
  PIN pw_data[174]
    DIRECTION OUTPUT ;
    USE SIGNAL ;
    PORT
      LAYER M5 ;
        RECT  67.212 0 67.236 0.192 ;
    END
  END pw_data[174]
  PIN pw_data[175]
    DIRECTION OUTPUT ;
    USE SIGNAL ;
    PORT
      LAYER M5 ;
        RECT  67.404 0 67.428 0.192 ;
    END
  END pw_data[175]
  PIN pw_data[176]
    DIRECTION OUTPUT ;
    USE SIGNAL ;
    PORT
      LAYER M5 ;
        RECT  67.644 0 67.668 0.192 ;
    END
  END pw_data[176]
  PIN pw_data[177]
    DIRECTION OUTPUT ;
    USE SIGNAL ;
    PORT
      LAYER M5 ;
        RECT  67.836 0 67.86 0.192 ;
    END
  END pw_data[177]
  PIN pw_data[178]
    DIRECTION OUTPUT ;
    USE SIGNAL ;
    PORT
      LAYER M5 ;
        RECT  68.028 0 68.052 0.192 ;
    END
  END pw_data[178]
  PIN pw_data[179]
    DIRECTION OUTPUT ;
    USE SIGNAL ;
    PORT
      LAYER M5 ;
        RECT  68.268 0 68.292 0.192 ;
    END
  END pw_data[179]
  PIN pw_data[17]
    DIRECTION OUTPUT ;
    USE SIGNAL ;
    PORT
      LAYER M4 ;
        RECT  0 56.7 0.192 56.724 ;
    END
  END pw_data[17]
  PIN pw_data[180]
    DIRECTION OUTPUT ;
    USE SIGNAL ;
    PORT
      LAYER M5 ;
        RECT  68.46 0 68.484 0.192 ;
    END
  END pw_data[180]
  PIN pw_data[181]
    DIRECTION OUTPUT ;
    USE SIGNAL ;
    PORT
      LAYER M5 ;
        RECT  68.7 0 68.724 0.192 ;
    END
  END pw_data[181]
  PIN pw_data[182]
    DIRECTION OUTPUT ;
    USE SIGNAL ;
    PORT
      LAYER M5 ;
        RECT  68.892 0 68.916 0.192 ;
    END
  END pw_data[182]
  PIN pw_data[183]
    DIRECTION OUTPUT ;
    USE SIGNAL ;
    PORT
      LAYER M5 ;
        RECT  69.084 0 69.108 0.192 ;
    END
  END pw_data[183]
  PIN pw_data[184]
    DIRECTION OUTPUT ;
    USE SIGNAL ;
    PORT
      LAYER M5 ;
        RECT  69.324 0 69.348 0.192 ;
    END
  END pw_data[184]
  PIN pw_data[185]
    DIRECTION OUTPUT ;
    USE SIGNAL ;
    PORT
      LAYER M5 ;
        RECT  69.516 0 69.54 0.192 ;
    END
  END pw_data[185]
  PIN pw_data[186]
    DIRECTION OUTPUT ;
    USE SIGNAL ;
    PORT
      LAYER M5 ;
        RECT  69.708 0 69.732 0.192 ;
    END
  END pw_data[186]
  PIN pw_data[187]
    DIRECTION OUTPUT ;
    USE SIGNAL ;
    PORT
      LAYER M5 ;
        RECT  69.948 0 69.972 0.192 ;
    END
  END pw_data[187]
  PIN pw_data[188]
    DIRECTION OUTPUT ;
    USE SIGNAL ;
    PORT
      LAYER M5 ;
        RECT  70.14 0 70.164 0.192 ;
    END
  END pw_data[188]
  PIN pw_data[189]
    DIRECTION OUTPUT ;
    USE SIGNAL ;
    PORT
      LAYER M5 ;
        RECT  70.38 0 70.404 0.192 ;
    END
  END pw_data[189]
  PIN pw_data[18]
    DIRECTION OUTPUT ;
    USE SIGNAL ;
    PORT
      LAYER M4 ;
        RECT  0 56.94 0.192 56.964 ;
    END
  END pw_data[18]
  PIN pw_data[190]
    DIRECTION OUTPUT ;
    USE SIGNAL ;
    PORT
      LAYER M5 ;
        RECT  70.572 0 70.596 0.192 ;
    END
  END pw_data[190]
  PIN pw_data[191]
    DIRECTION OUTPUT ;
    USE SIGNAL ;
    PORT
      LAYER M5 ;
        RECT  70.764 0 70.788 0.192 ;
    END
  END pw_data[191]
  PIN pw_data[192]
    DIRECTION OUTPUT ;
    USE SIGNAL ;
    PORT
      LAYER M5 ;
        RECT  71.004 0 71.028 0.192 ;
    END
  END pw_data[192]
  PIN pw_data[193]
    DIRECTION OUTPUT ;
    USE SIGNAL ;
    PORT
      LAYER M5 ;
        RECT  71.196 0 71.22 0.192 ;
    END
  END pw_data[193]
  PIN pw_data[194]
    DIRECTION OUTPUT ;
    USE SIGNAL ;
    PORT
      LAYER M5 ;
        RECT  71.388 0 71.412 0.192 ;
    END
  END pw_data[194]
  PIN pw_data[195]
    DIRECTION OUTPUT ;
    USE SIGNAL ;
    PORT
      LAYER M5 ;
        RECT  71.628 0 71.652 0.192 ;
    END
  END pw_data[195]
  PIN pw_data[196]
    DIRECTION OUTPUT ;
    USE SIGNAL ;
    PORT
      LAYER M5 ;
        RECT  71.82 0 71.844 0.192 ;
    END
  END pw_data[196]
  PIN pw_data[197]
    DIRECTION OUTPUT ;
    USE SIGNAL ;
    PORT
      LAYER M5 ;
        RECT  72.012 0 72.036 0.192 ;
    END
  END pw_data[197]
  PIN pw_data[198]
    DIRECTION OUTPUT ;
    USE SIGNAL ;
    PORT
      LAYER M5 ;
        RECT  72.252 0 72.276 0.192 ;
    END
  END pw_data[198]
  PIN pw_data[199]
    DIRECTION OUTPUT ;
    USE SIGNAL ;
    PORT
      LAYER M5 ;
        RECT  72.444 0 72.468 0.192 ;
    END
  END pw_data[199]
  PIN pw_data[19]
    DIRECTION OUTPUT ;
    USE SIGNAL ;
    PORT
      LAYER M4 ;
        RECT  0 57.132 0.192 57.156 ;
    END
  END pw_data[19]
  PIN pw_data[1]
    DIRECTION OUTPUT ;
    USE SIGNAL ;
    PORT
      LAYER M4 ;
        RECT  0 53.34 0.192 53.364 ;
    END
  END pw_data[1]
  PIN pw_data[200]
    DIRECTION OUTPUT ;
    USE SIGNAL ;
    PORT
      LAYER M5 ;
        RECT  72.684 0 72.708 0.192 ;
    END
  END pw_data[200]
  PIN pw_data[201]
    DIRECTION OUTPUT ;
    USE SIGNAL ;
    PORT
      LAYER M5 ;
        RECT  72.876 0 72.9 0.192 ;
    END
  END pw_data[201]
  PIN pw_data[202]
    DIRECTION OUTPUT ;
    USE SIGNAL ;
    PORT
      LAYER M5 ;
        RECT  73.068 0 73.092 0.192 ;
    END
  END pw_data[202]
  PIN pw_data[203]
    DIRECTION OUTPUT ;
    USE SIGNAL ;
    PORT
      LAYER M5 ;
        RECT  73.308 0 73.332 0.192 ;
    END
  END pw_data[203]
  PIN pw_data[204]
    DIRECTION OUTPUT ;
    USE SIGNAL ;
    PORT
      LAYER M5 ;
        RECT  73.5 0 73.524 0.192 ;
    END
  END pw_data[204]
  PIN pw_data[205]
    DIRECTION OUTPUT ;
    USE SIGNAL ;
    PORT
      LAYER M5 ;
        RECT  73.692 0 73.716 0.192 ;
    END
  END pw_data[205]
  PIN pw_data[206]
    DIRECTION OUTPUT ;
    USE SIGNAL ;
    PORT
      LAYER M5 ;
        RECT  73.932 0 73.956 0.192 ;
    END
  END pw_data[206]
  PIN pw_data[207]
    DIRECTION OUTPUT ;
    USE SIGNAL ;
    PORT
      LAYER M5 ;
        RECT  74.124 0 74.148 0.192 ;
    END
  END pw_data[207]
  PIN pw_data[208]
    DIRECTION OUTPUT ;
    USE SIGNAL ;
    PORT
      LAYER M5 ;
        RECT  74.364 0 74.388 0.192 ;
    END
  END pw_data[208]
  PIN pw_data[209]
    DIRECTION OUTPUT ;
    USE SIGNAL ;
    PORT
      LAYER M5 ;
        RECT  74.556 0 74.58 0.192 ;
    END
  END pw_data[209]
  PIN pw_data[20]
    DIRECTION OUTPUT ;
    USE SIGNAL ;
    PORT
      LAYER M4 ;
        RECT  0 57.372 0.192 57.396 ;
    END
  END pw_data[20]
  PIN pw_data[210]
    DIRECTION OUTPUT ;
    USE SIGNAL ;
    PORT
      LAYER M5 ;
        RECT  74.748 0 74.772 0.192 ;
    END
  END pw_data[210]
  PIN pw_data[211]
    DIRECTION OUTPUT ;
    USE SIGNAL ;
    PORT
      LAYER M5 ;
        RECT  74.988 0 75.012 0.192 ;
    END
  END pw_data[211]
  PIN pw_data[212]
    DIRECTION OUTPUT ;
    USE SIGNAL ;
    PORT
      LAYER M5 ;
        RECT  75.18 0 75.204 0.192 ;
    END
  END pw_data[212]
  PIN pw_data[213]
    DIRECTION OUTPUT ;
    USE SIGNAL ;
    PORT
      LAYER M5 ;
        RECT  75.372 0 75.396 0.192 ;
    END
  END pw_data[213]
  PIN pw_data[214]
    DIRECTION OUTPUT ;
    USE SIGNAL ;
    PORT
      LAYER M5 ;
        RECT  75.612 0 75.636 0.192 ;
    END
  END pw_data[214]
  PIN pw_data[215]
    DIRECTION OUTPUT ;
    USE SIGNAL ;
    PORT
      LAYER M5 ;
        RECT  75.804 0 75.828 0.192 ;
    END
  END pw_data[215]
  PIN pw_data[216]
    DIRECTION OUTPUT ;
    USE SIGNAL ;
    PORT
      LAYER M5 ;
        RECT  76.044 0 76.068 0.192 ;
    END
  END pw_data[216]
  PIN pw_data[217]
    DIRECTION OUTPUT ;
    USE SIGNAL ;
    PORT
      LAYER M5 ;
        RECT  76.236 0 76.26 0.192 ;
    END
  END pw_data[217]
  PIN pw_data[218]
    DIRECTION OUTPUT ;
    USE SIGNAL ;
    PORT
      LAYER M5 ;
        RECT  76.428 0 76.452 0.192 ;
    END
  END pw_data[218]
  PIN pw_data[219]
    DIRECTION OUTPUT ;
    USE SIGNAL ;
    PORT
      LAYER M5 ;
        RECT  76.668 0 76.692 0.192 ;
    END
  END pw_data[219]
  PIN pw_data[21]
    DIRECTION OUTPUT ;
    USE SIGNAL ;
    PORT
      LAYER M4 ;
        RECT  0 57.564 0.192 57.588 ;
    END
  END pw_data[21]
  PIN pw_data[220]
    DIRECTION OUTPUT ;
    USE SIGNAL ;
    PORT
      LAYER M5 ;
        RECT  76.86 0 76.884 0.192 ;
    END
  END pw_data[220]
  PIN pw_data[221]
    DIRECTION OUTPUT ;
    USE SIGNAL ;
    PORT
      LAYER M5 ;
        RECT  77.052 0 77.076 0.192 ;
    END
  END pw_data[221]
  PIN pw_data[222]
    DIRECTION OUTPUT ;
    USE SIGNAL ;
    PORT
      LAYER M5 ;
        RECT  77.292 0 77.316 0.192 ;
    END
  END pw_data[222]
  PIN pw_data[223]
    DIRECTION OUTPUT ;
    USE SIGNAL ;
    PORT
      LAYER M5 ;
        RECT  77.484 0 77.508 0.192 ;
    END
  END pw_data[223]
  PIN pw_data[224]
    DIRECTION OUTPUT ;
    USE SIGNAL ;
    PORT
      LAYER M5 ;
        RECT  77.724 0 77.748 0.192 ;
    END
  END pw_data[224]
  PIN pw_data[225]
    DIRECTION OUTPUT ;
    USE SIGNAL ;
    PORT
      LAYER M5 ;
        RECT  77.916 0 77.94 0.192 ;
    END
  END pw_data[225]
  PIN pw_data[226]
    DIRECTION OUTPUT ;
    USE SIGNAL ;
    PORT
      LAYER M5 ;
        RECT  78.108 0 78.132 0.192 ;
    END
  END pw_data[226]
  PIN pw_data[227]
    DIRECTION OUTPUT ;
    USE SIGNAL ;
    PORT
      LAYER M5 ;
        RECT  78.348 0 78.372 0.192 ;
    END
  END pw_data[227]
  PIN pw_data[228]
    DIRECTION OUTPUT ;
    USE SIGNAL ;
    PORT
      LAYER M5 ;
        RECT  78.54 0 78.564 0.192 ;
    END
  END pw_data[228]
  PIN pw_data[229]
    DIRECTION OUTPUT ;
    USE SIGNAL ;
    PORT
      LAYER M5 ;
        RECT  78.732 0 78.756 0.192 ;
    END
  END pw_data[229]
  PIN pw_data[22]
    DIRECTION OUTPUT ;
    USE SIGNAL ;
    PORT
      LAYER M4 ;
        RECT  0 57.756 0.192 57.78 ;
    END
  END pw_data[22]
  PIN pw_data[230]
    DIRECTION OUTPUT ;
    USE SIGNAL ;
    PORT
      LAYER M5 ;
        RECT  78.972 0 78.996 0.192 ;
    END
  END pw_data[230]
  PIN pw_data[231]
    DIRECTION OUTPUT ;
    USE SIGNAL ;
    PORT
      LAYER M5 ;
        RECT  79.164 0 79.188 0.192 ;
    END
  END pw_data[231]
  PIN pw_data[232]
    DIRECTION OUTPUT ;
    USE SIGNAL ;
    PORT
      LAYER M5 ;
        RECT  79.356 0 79.38 0.192 ;
    END
  END pw_data[232]
  PIN pw_data[233]
    DIRECTION OUTPUT ;
    USE SIGNAL ;
    PORT
      LAYER M5 ;
        RECT  79.596 0 79.62 0.192 ;
    END
  END pw_data[233]
  PIN pw_data[234]
    DIRECTION OUTPUT ;
    USE SIGNAL ;
    PORT
      LAYER M5 ;
        RECT  79.788 0 79.812 0.192 ;
    END
  END pw_data[234]
  PIN pw_data[235]
    DIRECTION OUTPUT ;
    USE SIGNAL ;
    PORT
      LAYER M5 ;
        RECT  80.028 0 80.052 0.192 ;
    END
  END pw_data[235]
  PIN pw_data[236]
    DIRECTION OUTPUT ;
    USE SIGNAL ;
    PORT
      LAYER M5 ;
        RECT  80.22 0 80.244 0.192 ;
    END
  END pw_data[236]
  PIN pw_data[237]
    DIRECTION OUTPUT ;
    USE SIGNAL ;
    PORT
      LAYER M5 ;
        RECT  80.412 0 80.436 0.192 ;
    END
  END pw_data[237]
  PIN pw_data[238]
    DIRECTION OUTPUT ;
    USE SIGNAL ;
    PORT
      LAYER M5 ;
        RECT  80.652 0 80.676 0.192 ;
    END
  END pw_data[238]
  PIN pw_data[239]
    DIRECTION OUTPUT ;
    USE SIGNAL ;
    PORT
      LAYER M5 ;
        RECT  80.844 0 80.868 0.192 ;
    END
  END pw_data[239]
  PIN pw_data[23]
    DIRECTION OUTPUT ;
    USE SIGNAL ;
    PORT
      LAYER M4 ;
        RECT  0 57.996 0.192 58.02 ;
    END
  END pw_data[23]
  PIN pw_data[240]
    DIRECTION OUTPUT ;
    USE SIGNAL ;
    PORT
      LAYER M5 ;
        RECT  81.036 0 81.06 0.192 ;
    END
  END pw_data[240]
  PIN pw_data[241]
    DIRECTION OUTPUT ;
    USE SIGNAL ;
    PORT
      LAYER M5 ;
        RECT  81.276 0 81.3 0.192 ;
    END
  END pw_data[241]
  PIN pw_data[242]
    DIRECTION OUTPUT ;
    USE SIGNAL ;
    PORT
      LAYER M5 ;
        RECT  81.468 0 81.492 0.192 ;
    END
  END pw_data[242]
  PIN pw_data[243]
    DIRECTION OUTPUT ;
    USE SIGNAL ;
    PORT
      LAYER M5 ;
        RECT  81.708 0 81.732 0.192 ;
    END
  END pw_data[243]
  PIN pw_data[244]
    DIRECTION OUTPUT ;
    USE SIGNAL ;
    PORT
      LAYER M5 ;
        RECT  81.9 0 81.924 0.192 ;
    END
  END pw_data[244]
  PIN pw_data[245]
    DIRECTION OUTPUT ;
    USE SIGNAL ;
    PORT
      LAYER M5 ;
        RECT  82.092 0 82.116 0.192 ;
    END
  END pw_data[245]
  PIN pw_data[246]
    DIRECTION OUTPUT ;
    USE SIGNAL ;
    PORT
      LAYER M5 ;
        RECT  82.332 0 82.356 0.192 ;
    END
  END pw_data[246]
  PIN pw_data[247]
    DIRECTION OUTPUT ;
    USE SIGNAL ;
    PORT
      LAYER M5 ;
        RECT  82.524 0 82.548 0.192 ;
    END
  END pw_data[247]
  PIN pw_data[248]
    DIRECTION OUTPUT ;
    USE SIGNAL ;
    PORT
      LAYER M5 ;
        RECT  82.716 0 82.74 0.192 ;
    END
  END pw_data[248]
  PIN pw_data[249]
    DIRECTION OUTPUT ;
    USE SIGNAL ;
    PORT
      LAYER M5 ;
        RECT  82.956 0 82.98 0.192 ;
    END
  END pw_data[249]
  PIN pw_data[24]
    DIRECTION OUTPUT ;
    USE SIGNAL ;
    PORT
      LAYER M4 ;
        RECT  0 58.188 0.192 58.212 ;
    END
  END pw_data[24]
  PIN pw_data[250]
    DIRECTION OUTPUT ;
    USE SIGNAL ;
    PORT
      LAYER M5 ;
        RECT  83.148 0 83.172 0.192 ;
    END
  END pw_data[250]
  PIN pw_data[251]
    DIRECTION OUTPUT ;
    USE SIGNAL ;
    PORT
      LAYER M5 ;
        RECT  83.388 0 83.412 0.192 ;
    END
  END pw_data[251]
  PIN pw_data[252]
    DIRECTION OUTPUT ;
    USE SIGNAL ;
    PORT
      LAYER M5 ;
        RECT  83.58 0 83.604 0.192 ;
    END
  END pw_data[252]
  PIN pw_data[253]
    DIRECTION OUTPUT ;
    USE SIGNAL ;
    PORT
      LAYER M5 ;
        RECT  83.772 0 83.796 0.192 ;
    END
  END pw_data[253]
  PIN pw_data[254]
    DIRECTION OUTPUT ;
    USE SIGNAL ;
    PORT
      LAYER M5 ;
        RECT  84.012 0 84.036 0.192 ;
    END
  END pw_data[254]
  PIN pw_data[255]
    DIRECTION OUTPUT ;
    USE SIGNAL ;
    PORT
      LAYER M5 ;
        RECT  84.204 0 84.228 0.192 ;
    END
  END pw_data[255]
  PIN pw_data[25]
    DIRECTION OUTPUT ;
    USE SIGNAL ;
    PORT
      LAYER M4 ;
        RECT  0 58.428 0.192 58.452 ;
    END
  END pw_data[25]
  PIN pw_data[26]
    DIRECTION OUTPUT ;
    USE SIGNAL ;
    PORT
      LAYER M4 ;
        RECT  0 58.62 0.192 58.644 ;
    END
  END pw_data[26]
  PIN pw_data[27]
    DIRECTION OUTPUT ;
    USE SIGNAL ;
    PORT
      LAYER M4 ;
        RECT  0 58.812 0.192 58.836 ;
    END
  END pw_data[27]
  PIN pw_data[28]
    DIRECTION OUTPUT ;
    USE SIGNAL ;
    PORT
      LAYER M4 ;
        RECT  0 59.052 0.192 59.076 ;
    END
  END pw_data[28]
  PIN pw_data[29]
    DIRECTION OUTPUT ;
    USE SIGNAL ;
    PORT
      LAYER M4 ;
        RECT  0 59.244 0.192 59.268 ;
    END
  END pw_data[29]
  PIN pw_data[2]
    DIRECTION OUTPUT ;
    USE SIGNAL ;
    PORT
      LAYER M4 ;
        RECT  0 53.532 0.192 53.556 ;
    END
  END pw_data[2]
  PIN pw_data[30]
    DIRECTION OUTPUT ;
    USE SIGNAL ;
    PORT
      LAYER M4 ;
        RECT  0 59.484 0.192 59.508 ;
    END
  END pw_data[30]
  PIN pw_data[31]
    DIRECTION OUTPUT ;
    USE SIGNAL ;
    PORT
      LAYER M4 ;
        RECT  0 59.676 0.192 59.7 ;
    END
  END pw_data[31]
  PIN pw_data[32]
    DIRECTION OUTPUT ;
    USE SIGNAL ;
    PORT
      LAYER M4 ;
        RECT  0 59.868 0.192 59.892 ;
    END
  END pw_data[32]
  PIN pw_data[33]
    DIRECTION OUTPUT ;
    USE SIGNAL ;
    PORT
      LAYER M4 ;
        RECT  0 60.108 0.192 60.132 ;
    END
  END pw_data[33]
  PIN pw_data[34]
    DIRECTION OUTPUT ;
    USE SIGNAL ;
    PORT
      LAYER M4 ;
        RECT  0 60.3 0.192 60.324 ;
    END
  END pw_data[34]
  PIN pw_data[35]
    DIRECTION OUTPUT ;
    USE SIGNAL ;
    PORT
      LAYER M4 ;
        RECT  0 60.54 0.192 60.564 ;
    END
  END pw_data[35]
  PIN pw_data[36]
    DIRECTION OUTPUT ;
    USE SIGNAL ;
    PORT
      LAYER M4 ;
        RECT  0 60.732 0.192 60.756 ;
    END
  END pw_data[36]
  PIN pw_data[37]
    DIRECTION OUTPUT ;
    USE SIGNAL ;
    PORT
      LAYER M4 ;
        RECT  0 60.924 0.192 60.948 ;
    END
  END pw_data[37]
  PIN pw_data[38]
    DIRECTION OUTPUT ;
    USE SIGNAL ;
    PORT
      LAYER M4 ;
        RECT  0 61.164 0.192 61.188 ;
    END
  END pw_data[38]
  PIN pw_data[39]
    DIRECTION OUTPUT ;
    USE SIGNAL ;
    PORT
      LAYER M4 ;
        RECT  0 61.356 0.192 61.38 ;
    END
  END pw_data[39]
  PIN pw_data[3]
    DIRECTION OUTPUT ;
    USE SIGNAL ;
    PORT
      LAYER M4 ;
        RECT  0 53.772 0.192 53.796 ;
    END
  END pw_data[3]
  PIN pw_data[40]
    DIRECTION OUTPUT ;
    USE SIGNAL ;
    PORT
      LAYER M4 ;
        RECT  0 61.596 0.192 61.62 ;
    END
  END pw_data[40]
  PIN pw_data[41]
    DIRECTION OUTPUT ;
    USE SIGNAL ;
    PORT
      LAYER M4 ;
        RECT  0 61.788 0.192 61.812 ;
    END
  END pw_data[41]
  PIN pw_data[42]
    DIRECTION OUTPUT ;
    USE SIGNAL ;
    PORT
      LAYER M4 ;
        RECT  0 62.028 0.192 62.052 ;
    END
  END pw_data[42]
  PIN pw_data[43]
    DIRECTION OUTPUT ;
    USE SIGNAL ;
    PORT
      LAYER M4 ;
        RECT  0 62.22 0.192 62.244 ;
    END
  END pw_data[43]
  PIN pw_data[44]
    DIRECTION OUTPUT ;
    USE SIGNAL ;
    PORT
      LAYER M4 ;
        RECT  0 62.412 0.192 62.436 ;
    END
  END pw_data[44]
  PIN pw_data[45]
    DIRECTION OUTPUT ;
    USE SIGNAL ;
    PORT
      LAYER M4 ;
        RECT  0 62.652 0.192 62.676 ;
    END
  END pw_data[45]
  PIN pw_data[46]
    DIRECTION OUTPUT ;
    USE SIGNAL ;
    PORT
      LAYER M4 ;
        RECT  0 62.844 0.192 62.868 ;
    END
  END pw_data[46]
  PIN pw_data[47]
    DIRECTION OUTPUT ;
    USE SIGNAL ;
    PORT
      LAYER M4 ;
        RECT  0 63.084 0.192 63.108 ;
    END
  END pw_data[47]
  PIN pw_data[48]
    DIRECTION OUTPUT ;
    USE SIGNAL ;
    PORT
      LAYER M4 ;
        RECT  0 63.276 0.192 63.3 ;
    END
  END pw_data[48]
  PIN pw_data[49]
    DIRECTION OUTPUT ;
    USE SIGNAL ;
    PORT
      LAYER M4 ;
        RECT  0 63.468 0.192 63.492 ;
    END
  END pw_data[49]
  PIN pw_data[4]
    DIRECTION OUTPUT ;
    USE SIGNAL ;
    PORT
      LAYER M4 ;
        RECT  0 53.964 0.192 53.988 ;
    END
  END pw_data[4]
  PIN pw_data[50]
    DIRECTION OUTPUT ;
    USE SIGNAL ;
    PORT
      LAYER M4 ;
        RECT  0 63.708 0.192 63.732 ;
    END
  END pw_data[50]
  PIN pw_data[51]
    DIRECTION OUTPUT ;
    USE SIGNAL ;
    PORT
      LAYER M4 ;
        RECT  0 63.9 0.192 63.924 ;
    END
  END pw_data[51]
  PIN pw_data[52]
    DIRECTION OUTPUT ;
    USE SIGNAL ;
    PORT
      LAYER M4 ;
        RECT  0 64.14 0.192 64.164 ;
    END
  END pw_data[52]
  PIN pw_data[53]
    DIRECTION OUTPUT ;
    USE SIGNAL ;
    PORT
      LAYER M4 ;
        RECT  0 64.332 0.192 64.356 ;
    END
  END pw_data[53]
  PIN pw_data[54]
    DIRECTION OUTPUT ;
    USE SIGNAL ;
    PORT
      LAYER M4 ;
        RECT  0 64.524 0.192 64.548 ;
    END
  END pw_data[54]
  PIN pw_data[55]
    DIRECTION OUTPUT ;
    USE SIGNAL ;
    PORT
      LAYER M4 ;
        RECT  0 64.764 0.192 64.788 ;
    END
  END pw_data[55]
  PIN pw_data[56]
    DIRECTION OUTPUT ;
    USE SIGNAL ;
    PORT
      LAYER M4 ;
        RECT  0 64.956 0.192 64.98 ;
    END
  END pw_data[56]
  PIN pw_data[57]
    DIRECTION OUTPUT ;
    USE SIGNAL ;
    PORT
      LAYER M4 ;
        RECT  0 65.196 0.192 65.22 ;
    END
  END pw_data[57]
  PIN pw_data[58]
    DIRECTION OUTPUT ;
    USE SIGNAL ;
    PORT
      LAYER M4 ;
        RECT  0 65.388 0.192 65.412 ;
    END
  END pw_data[58]
  PIN pw_data[59]
    DIRECTION OUTPUT ;
    USE SIGNAL ;
    PORT
      LAYER M4 ;
        RECT  0 65.58 0.192 65.604 ;
    END
  END pw_data[59]
  PIN pw_data[5]
    DIRECTION OUTPUT ;
    USE SIGNAL ;
    PORT
      LAYER M4 ;
        RECT  0 54.204 0.192 54.228 ;
    END
  END pw_data[5]
  PIN pw_data[60]
    DIRECTION OUTPUT ;
    USE SIGNAL ;
    PORT
      LAYER M4 ;
        RECT  0 65.82 0.192 65.844 ;
    END
  END pw_data[60]
  PIN pw_data[61]
    DIRECTION OUTPUT ;
    USE SIGNAL ;
    PORT
      LAYER M4 ;
        RECT  0 66.012 0.192 66.036 ;
    END
  END pw_data[61]
  PIN pw_data[62]
    DIRECTION OUTPUT ;
    USE SIGNAL ;
    PORT
      LAYER M4 ;
        RECT  0 66.252 0.192 66.276 ;
    END
  END pw_data[62]
  PIN pw_data[63]
    DIRECTION OUTPUT ;
    USE SIGNAL ;
    PORT
      LAYER M4 ;
        RECT  0 66.444 0.192 66.468 ;
    END
  END pw_data[63]
  PIN pw_data[64]
    DIRECTION OUTPUT ;
    USE SIGNAL ;
    PORT
      LAYER M4 ;
        RECT  0 66.636 0.192 66.66 ;
    END
  END pw_data[64]
  PIN pw_data[65]
    DIRECTION OUTPUT ;
    USE SIGNAL ;
    PORT
      LAYER M4 ;
        RECT  0 66.876 0.192 66.9 ;
    END
  END pw_data[65]
  PIN pw_data[66]
    DIRECTION OUTPUT ;
    USE SIGNAL ;
    PORT
      LAYER M4 ;
        RECT  0 67.068 0.192 67.092 ;
    END
  END pw_data[66]
  PIN pw_data[67]
    DIRECTION OUTPUT ;
    USE SIGNAL ;
    PORT
      LAYER M4 ;
        RECT  0 67.308 0.192 67.332 ;
    END
  END pw_data[67]
  PIN pw_data[68]
    DIRECTION OUTPUT ;
    USE SIGNAL ;
    PORT
      LAYER M4 ;
        RECT  0 67.5 0.192 67.524 ;
    END
  END pw_data[68]
  PIN pw_data[69]
    DIRECTION OUTPUT ;
    USE SIGNAL ;
    PORT
      LAYER M4 ;
        RECT  0 67.692 0.192 67.716 ;
    END
  END pw_data[69]
  PIN pw_data[6]
    DIRECTION OUTPUT ;
    USE SIGNAL ;
    PORT
      LAYER M4 ;
        RECT  0 54.396 0.192 54.42 ;
    END
  END pw_data[6]
  PIN pw_data[70]
    DIRECTION OUTPUT ;
    USE SIGNAL ;
    PORT
      LAYER M4 ;
        RECT  0 67.932 0.192 67.956 ;
    END
  END pw_data[70]
  PIN pw_data[71]
    DIRECTION OUTPUT ;
    USE SIGNAL ;
    PORT
      LAYER M4 ;
        RECT  0 68.124 0.192 68.148 ;
    END
  END pw_data[71]
  PIN pw_data[72]
    DIRECTION OUTPUT ;
    USE SIGNAL ;
    PORT
      LAYER M4 ;
        RECT  0 68.364 0.192 68.388 ;
    END
  END pw_data[72]
  PIN pw_data[73]
    DIRECTION OUTPUT ;
    USE SIGNAL ;
    PORT
      LAYER M4 ;
        RECT  0 68.556 0.192 68.58 ;
    END
  END pw_data[73]
  PIN pw_data[74]
    DIRECTION OUTPUT ;
    USE SIGNAL ;
    PORT
      LAYER M4 ;
        RECT  0 68.748 0.192 68.772 ;
    END
  END pw_data[74]
  PIN pw_data[75]
    DIRECTION OUTPUT ;
    USE SIGNAL ;
    PORT
      LAYER M4 ;
        RECT  0 68.988 0.192 69.012 ;
    END
  END pw_data[75]
  PIN pw_data[76]
    DIRECTION OUTPUT ;
    USE SIGNAL ;
    PORT
      LAYER M4 ;
        RECT  0 69.18 0.192 69.204 ;
    END
  END pw_data[76]
  PIN pw_data[77]
    DIRECTION OUTPUT ;
    USE SIGNAL ;
    PORT
      LAYER M4 ;
        RECT  0 69.42 0.192 69.444 ;
    END
  END pw_data[77]
  PIN pw_data[78]
    DIRECTION OUTPUT ;
    USE SIGNAL ;
    PORT
      LAYER M4 ;
        RECT  0 69.612 0.192 69.636 ;
    END
  END pw_data[78]
  PIN pw_data[79]
    DIRECTION OUTPUT ;
    USE SIGNAL ;
    PORT
      LAYER M4 ;
        RECT  0 69.804 0.192 69.828 ;
    END
  END pw_data[79]
  PIN pw_data[7]
    DIRECTION OUTPUT ;
    USE SIGNAL ;
    PORT
      LAYER M4 ;
        RECT  0 54.588 0.192 54.612 ;
    END
  END pw_data[7]
  PIN pw_data[80]
    DIRECTION OUTPUT ;
    USE SIGNAL ;
    PORT
      LAYER M4 ;
        RECT  0 70.044 0.192 70.068 ;
    END
  END pw_data[80]
  PIN pw_data[81]
    DIRECTION OUTPUT ;
    USE SIGNAL ;
    PORT
      LAYER M4 ;
        RECT  0 70.236 0.192 70.26 ;
    END
  END pw_data[81]
  PIN pw_data[82]
    DIRECTION OUTPUT ;
    USE SIGNAL ;
    PORT
      LAYER M4 ;
        RECT  0 70.476 0.192 70.5 ;
    END
  END pw_data[82]
  PIN pw_data[83]
    DIRECTION OUTPUT ;
    USE SIGNAL ;
    PORT
      LAYER M4 ;
        RECT  0 70.668 0.192 70.692 ;
    END
  END pw_data[83]
  PIN pw_data[84]
    DIRECTION OUTPUT ;
    USE SIGNAL ;
    PORT
      LAYER M4 ;
        RECT  0 70.908 0.192 70.932 ;
    END
  END pw_data[84]
  PIN pw_data[85]
    DIRECTION OUTPUT ;
    USE SIGNAL ;
    PORT
      LAYER M4 ;
        RECT  0 71.1 0.192 71.124 ;
    END
  END pw_data[85]
  PIN pw_data[86]
    DIRECTION OUTPUT ;
    USE SIGNAL ;
    PORT
      LAYER M4 ;
        RECT  0 71.292 0.192 71.316 ;
    END
  END pw_data[86]
  PIN pw_data[87]
    DIRECTION OUTPUT ;
    USE SIGNAL ;
    PORT
      LAYER M4 ;
        RECT  0 71.532 0.192 71.556 ;
    END
  END pw_data[87]
  PIN pw_data[88]
    DIRECTION OUTPUT ;
    USE SIGNAL ;
    PORT
      LAYER M4 ;
        RECT  0 71.724 0.192 71.748 ;
    END
  END pw_data[88]
  PIN pw_data[89]
    DIRECTION OUTPUT ;
    USE SIGNAL ;
    PORT
      LAYER M4 ;
        RECT  0 71.964 0.192 71.988 ;
    END
  END pw_data[89]
  PIN pw_data[8]
    DIRECTION OUTPUT ;
    USE SIGNAL ;
    PORT
      LAYER M4 ;
        RECT  0 54.828 0.192 54.852 ;
    END
  END pw_data[8]
  PIN pw_data[90]
    DIRECTION OUTPUT ;
    USE SIGNAL ;
    PORT
      LAYER M4 ;
        RECT  0 72.156 0.192 72.18 ;
    END
  END pw_data[90]
  PIN pw_data[91]
    DIRECTION OUTPUT ;
    USE SIGNAL ;
    PORT
      LAYER M4 ;
        RECT  0 72.348 0.192 72.372 ;
    END
  END pw_data[91]
  PIN pw_data[92]
    DIRECTION OUTPUT ;
    USE SIGNAL ;
    PORT
      LAYER M4 ;
        RECT  0 72.588 0.192 72.612 ;
    END
  END pw_data[92]
  PIN pw_data[93]
    DIRECTION OUTPUT ;
    USE SIGNAL ;
    PORT
      LAYER M4 ;
        RECT  0 72.78 0.192 72.804 ;
    END
  END pw_data[93]
  PIN pw_data[94]
    DIRECTION OUTPUT ;
    USE SIGNAL ;
    PORT
      LAYER M4 ;
        RECT  0 73.02 0.192 73.044 ;
    END
  END pw_data[94]
  PIN pw_data[95]
    DIRECTION OUTPUT ;
    USE SIGNAL ;
    PORT
      LAYER M4 ;
        RECT  0 73.212 0.192 73.236 ;
    END
  END pw_data[95]
  PIN pw_data[96]
    DIRECTION OUTPUT ;
    USE SIGNAL ;
    PORT
      LAYER M4 ;
        RECT  0 73.404 0.192 73.428 ;
    END
  END pw_data[96]
  PIN pw_data[97]
    DIRECTION OUTPUT ;
    USE SIGNAL ;
    PORT
      LAYER M4 ;
        RECT  0 73.644 0.192 73.668 ;
    END
  END pw_data[97]
  PIN pw_data[98]
    DIRECTION OUTPUT ;
    USE SIGNAL ;
    PORT
      LAYER M4 ;
        RECT  0 73.836 0.192 73.86 ;
    END
  END pw_data[98]
  PIN pw_data[99]
    DIRECTION OUTPUT ;
    USE SIGNAL ;
    PORT
      LAYER M4 ;
        RECT  0 74.076 0.192 74.1 ;
    END
  END pw_data[99]
  PIN pw_data[9]
    DIRECTION OUTPUT ;
    USE SIGNAL ;
    PORT
      LAYER M4 ;
        RECT  0 55.02 0.192 55.044 ;
    END
  END pw_data[9]
  PIN pw_we[0]
    DIRECTION OUTPUT ;
    USE SIGNAL ;
    PORT
      LAYER M5 ;
        RECT  62.028 86.208 62.052 86.4 ;
    END
  END pw_we[0]
  PIN ready
    DIRECTION OUTPUT ;
    USE SIGNAL ;
    PORT
      LAYER M5 ;
        RECT  61.596 86.208 61.62 86.4 ;
    END
  END ready
  PIN rec[0]
    DIRECTION OUTPUT ;
    USE SIGNAL ;
    PORT
      LAYER M4 ;
        RECT  0 2.172 0.192 2.196 ;
    END
  END rec[0]
  PIN rec[100]
    DIRECTION OUTPUT ;
    USE SIGNAL ;
    PORT
      LAYER M4 ;
        RECT  0 23.292 0.192 23.316 ;
    END
  END rec[100]
  PIN rec[101]
    DIRECTION OUTPUT ;
    USE SIGNAL ;
    PORT
      LAYER M4 ;
        RECT  0 23.532 0.192 23.556 ;
    END
  END rec[101]
  PIN rec[102]
    DIRECTION OUTPUT ;
    USE SIGNAL ;
    PORT
      LAYER M4 ;
        RECT  0 23.724 0.192 23.748 ;
    END
  END rec[102]
  PIN rec[103]
    DIRECTION OUTPUT ;
    USE SIGNAL ;
    PORT
      LAYER M4 ;
        RECT  0 23.964 0.192 23.988 ;
    END
  END rec[103]
  PIN rec[104]
    DIRECTION OUTPUT ;
    USE SIGNAL ;
    PORT
      LAYER M4 ;
        RECT  0 24.156 0.192 24.18 ;
    END
  END rec[104]
  PIN rec[105]
    DIRECTION OUTPUT ;
    USE SIGNAL ;
    PORT
      LAYER M4 ;
        RECT  0 24.348 0.192 24.372 ;
    END
  END rec[105]
  PIN rec[106]
    DIRECTION OUTPUT ;
    USE SIGNAL ;
    PORT
      LAYER M4 ;
        RECT  0 24.588 0.192 24.612 ;
    END
  END rec[106]
  PIN rec[107]
    DIRECTION OUTPUT ;
    USE SIGNAL ;
    PORT
      LAYER M4 ;
        RECT  0 24.78 0.192 24.804 ;
    END
  END rec[107]
  PIN rec[108]
    DIRECTION OUTPUT ;
    USE SIGNAL ;
    PORT
      LAYER M4 ;
        RECT  0 25.02 0.192 25.044 ;
    END
  END rec[108]
  PIN rec[109]
    DIRECTION OUTPUT ;
    USE SIGNAL ;
    PORT
      LAYER M4 ;
        RECT  0 25.212 0.192 25.236 ;
    END
  END rec[109]
  PIN rec[10]
    DIRECTION OUTPUT ;
    USE SIGNAL ;
    PORT
      LAYER M4 ;
        RECT  0 4.284 0.192 4.308 ;
    END
  END rec[10]
  PIN rec[110]
    DIRECTION OUTPUT ;
    USE SIGNAL ;
    PORT
      LAYER M4 ;
        RECT  0 25.452 0.192 25.476 ;
    END
  END rec[110]
  PIN rec[111]
    DIRECTION OUTPUT ;
    USE SIGNAL ;
    PORT
      LAYER M4 ;
        RECT  0 25.644 0.192 25.668 ;
    END
  END rec[111]
  PIN rec[112]
    DIRECTION OUTPUT ;
    USE SIGNAL ;
    PORT
      LAYER M4 ;
        RECT  0 25.836 0.192 25.86 ;
    END
  END rec[112]
  PIN rec[113]
    DIRECTION OUTPUT ;
    USE SIGNAL ;
    PORT
      LAYER M4 ;
        RECT  0 26.076 0.192 26.1 ;
    END
  END rec[113]
  PIN rec[114]
    DIRECTION OUTPUT ;
    USE SIGNAL ;
    PORT
      LAYER M4 ;
        RECT  0 26.268 0.192 26.292 ;
    END
  END rec[114]
  PIN rec[115]
    DIRECTION OUTPUT ;
    USE SIGNAL ;
    PORT
      LAYER M4 ;
        RECT  0 26.508 0.192 26.532 ;
    END
  END rec[115]
  PIN rec[116]
    DIRECTION OUTPUT ;
    USE SIGNAL ;
    PORT
      LAYER M4 ;
        RECT  0 26.7 0.192 26.724 ;
    END
  END rec[116]
  PIN rec[117]
    DIRECTION OUTPUT ;
    USE SIGNAL ;
    PORT
      LAYER M4 ;
        RECT  0 26.892 0.192 26.916 ;
    END
  END rec[117]
  PIN rec[118]
    DIRECTION OUTPUT ;
    USE SIGNAL ;
    PORT
      LAYER M4 ;
        RECT  0 27.132 0.192 27.156 ;
    END
  END rec[118]
  PIN rec[119]
    DIRECTION OUTPUT ;
    USE SIGNAL ;
    PORT
      LAYER M4 ;
        RECT  0 27.324 0.192 27.348 ;
    END
  END rec[119]
  PIN rec[11]
    DIRECTION OUTPUT ;
    USE SIGNAL ;
    PORT
      LAYER M4 ;
        RECT  0 4.476 0.192 4.5 ;
    END
  END rec[11]
  PIN rec[120]
    DIRECTION OUTPUT ;
    USE SIGNAL ;
    PORT
      LAYER M4 ;
        RECT  0 27.564 0.192 27.588 ;
    END
  END rec[120]
  PIN rec[121]
    DIRECTION OUTPUT ;
    USE SIGNAL ;
    PORT
      LAYER M4 ;
        RECT  0 27.756 0.192 27.78 ;
    END
  END rec[121]
  PIN rec[122]
    DIRECTION OUTPUT ;
    USE SIGNAL ;
    PORT
      LAYER M4 ;
        RECT  0 27.948 0.192 27.972 ;
    END
  END rec[122]
  PIN rec[123]
    DIRECTION OUTPUT ;
    USE SIGNAL ;
    PORT
      LAYER M4 ;
        RECT  0 28.188 0.192 28.212 ;
    END
  END rec[123]
  PIN rec[124]
    DIRECTION OUTPUT ;
    USE SIGNAL ;
    PORT
      LAYER M4 ;
        RECT  0 28.38 0.192 28.404 ;
    END
  END rec[124]
  PIN rec[125]
    DIRECTION OUTPUT ;
    USE SIGNAL ;
    PORT
      LAYER M4 ;
        RECT  0 28.62 0.192 28.644 ;
    END
  END rec[125]
  PIN rec[126]
    DIRECTION OUTPUT ;
    USE SIGNAL ;
    PORT
      LAYER M4 ;
        RECT  0 28.812 0.192 28.836 ;
    END
  END rec[126]
  PIN rec[127]
    DIRECTION OUTPUT ;
    USE SIGNAL ;
    PORT
      LAYER M4 ;
        RECT  0 29.004 0.192 29.028 ;
    END
  END rec[127]
  PIN rec[128]
    DIRECTION OUTPUT ;
    USE SIGNAL ;
    PORT
      LAYER M4 ;
        RECT  0 29.244 0.192 29.268 ;
    END
  END rec[128]
  PIN rec[129]
    DIRECTION OUTPUT ;
    USE SIGNAL ;
    PORT
      LAYER M4 ;
        RECT  0 29.436 0.192 29.46 ;
    END
  END rec[129]
  PIN rec[12]
    DIRECTION OUTPUT ;
    USE SIGNAL ;
    PORT
      LAYER M4 ;
        RECT  0 4.716 0.192 4.74 ;
    END
  END rec[12]
  PIN rec[130]
    DIRECTION OUTPUT ;
    USE SIGNAL ;
    PORT
      LAYER M4 ;
        RECT  0 29.676 0.192 29.7 ;
    END
  END rec[130]
  PIN rec[131]
    DIRECTION OUTPUT ;
    USE SIGNAL ;
    PORT
      LAYER M4 ;
        RECT  0 29.868 0.192 29.892 ;
    END
  END rec[131]
  PIN rec[132]
    DIRECTION OUTPUT ;
    USE SIGNAL ;
    PORT
      LAYER M4 ;
        RECT  0 30.06 0.192 30.084 ;
    END
  END rec[132]
  PIN rec[133]
    DIRECTION OUTPUT ;
    USE SIGNAL ;
    PORT
      LAYER M4 ;
        RECT  0 30.3 0.192 30.324 ;
    END
  END rec[133]
  PIN rec[134]
    DIRECTION OUTPUT ;
    USE SIGNAL ;
    PORT
      LAYER M4 ;
        RECT  0 30.492 0.192 30.516 ;
    END
  END rec[134]
  PIN rec[135]
    DIRECTION OUTPUT ;
    USE SIGNAL ;
    PORT
      LAYER M4 ;
        RECT  0 30.732 0.192 30.756 ;
    END
  END rec[135]
  PIN rec[136]
    DIRECTION OUTPUT ;
    USE SIGNAL ;
    PORT
      LAYER M4 ;
        RECT  0 30.924 0.192 30.948 ;
    END
  END rec[136]
  PIN rec[137]
    DIRECTION OUTPUT ;
    USE SIGNAL ;
    PORT
      LAYER M4 ;
        RECT  0 31.116 0.192 31.14 ;
    END
  END rec[137]
  PIN rec[138]
    DIRECTION OUTPUT ;
    USE SIGNAL ;
    PORT
      LAYER M4 ;
        RECT  0 31.356 0.192 31.38 ;
    END
  END rec[138]
  PIN rec[139]
    DIRECTION OUTPUT ;
    USE SIGNAL ;
    PORT
      LAYER M4 ;
        RECT  0 31.548 0.192 31.572 ;
    END
  END rec[139]
  PIN rec[13]
    DIRECTION OUTPUT ;
    USE SIGNAL ;
    PORT
      LAYER M4 ;
        RECT  0 4.908 0.192 4.932 ;
    END
  END rec[13]
  PIN rec[140]
    DIRECTION OUTPUT ;
    USE SIGNAL ;
    PORT
      LAYER M4 ;
        RECT  0 31.788 0.192 31.812 ;
    END
  END rec[140]
  PIN rec[141]
    DIRECTION OUTPUT ;
    USE SIGNAL ;
    PORT
      LAYER M4 ;
        RECT  0 31.98 0.192 32.004 ;
    END
  END rec[141]
  PIN rec[142]
    DIRECTION OUTPUT ;
    USE SIGNAL ;
    PORT
      LAYER M4 ;
        RECT  0 32.172 0.192 32.196 ;
    END
  END rec[142]
  PIN rec[143]
    DIRECTION OUTPUT ;
    USE SIGNAL ;
    PORT
      LAYER M4 ;
        RECT  0 32.412 0.192 32.436 ;
    END
  END rec[143]
  PIN rec[144]
    DIRECTION OUTPUT ;
    USE SIGNAL ;
    PORT
      LAYER M4 ;
        RECT  0 32.604 0.192 32.628 ;
    END
  END rec[144]
  PIN rec[145]
    DIRECTION OUTPUT ;
    USE SIGNAL ;
    PORT
      LAYER M4 ;
        RECT  0 32.844 0.192 32.868 ;
    END
  END rec[145]
  PIN rec[146]
    DIRECTION OUTPUT ;
    USE SIGNAL ;
    PORT
      LAYER M4 ;
        RECT  0 33.036 0.192 33.06 ;
    END
  END rec[146]
  PIN rec[147]
    DIRECTION OUTPUT ;
    USE SIGNAL ;
    PORT
      LAYER M4 ;
        RECT  0 33.228 0.192 33.252 ;
    END
  END rec[147]
  PIN rec[148]
    DIRECTION OUTPUT ;
    USE SIGNAL ;
    PORT
      LAYER M4 ;
        RECT  0 33.468 0.192 33.492 ;
    END
  END rec[148]
  PIN rec[149]
    DIRECTION OUTPUT ;
    USE SIGNAL ;
    PORT
      LAYER M4 ;
        RECT  0 33.66 0.192 33.684 ;
    END
  END rec[149]
  PIN rec[14]
    DIRECTION OUTPUT ;
    USE SIGNAL ;
    PORT
      LAYER M4 ;
        RECT  0 5.148 0.192 5.172 ;
    END
  END rec[14]
  PIN rec[150]
    DIRECTION OUTPUT ;
    USE SIGNAL ;
    PORT
      LAYER M4 ;
        RECT  0 33.9 0.192 33.924 ;
    END
  END rec[150]
  PIN rec[151]
    DIRECTION OUTPUT ;
    USE SIGNAL ;
    PORT
      LAYER M4 ;
        RECT  0 34.092 0.192 34.116 ;
    END
  END rec[151]
  PIN rec[152]
    DIRECTION OUTPUT ;
    USE SIGNAL ;
    PORT
      LAYER M4 ;
        RECT  0 34.332 0.192 34.356 ;
    END
  END rec[152]
  PIN rec[153]
    DIRECTION OUTPUT ;
    USE SIGNAL ;
    PORT
      LAYER M4 ;
        RECT  0 34.524 0.192 34.548 ;
    END
  END rec[153]
  PIN rec[154]
    DIRECTION OUTPUT ;
    USE SIGNAL ;
    PORT
      LAYER M4 ;
        RECT  0 34.716 0.192 34.74 ;
    END
  END rec[154]
  PIN rec[155]
    DIRECTION OUTPUT ;
    USE SIGNAL ;
    PORT
      LAYER M4 ;
        RECT  0 34.956 0.192 34.98 ;
    END
  END rec[155]
  PIN rec[156]
    DIRECTION OUTPUT ;
    USE SIGNAL ;
    PORT
      LAYER M4 ;
        RECT  0 35.148 0.192 35.172 ;
    END
  END rec[156]
  PIN rec[157]
    DIRECTION OUTPUT ;
    USE SIGNAL ;
    PORT
      LAYER M4 ;
        RECT  0 35.388 0.192 35.412 ;
    END
  END rec[157]
  PIN rec[158]
    DIRECTION OUTPUT ;
    USE SIGNAL ;
    PORT
      LAYER M4 ;
        RECT  0 35.58 0.192 35.604 ;
    END
  END rec[158]
  PIN rec[159]
    DIRECTION OUTPUT ;
    USE SIGNAL ;
    PORT
      LAYER M4 ;
        RECT  0 35.772 0.192 35.796 ;
    END
  END rec[159]
  PIN rec[15]
    DIRECTION OUTPUT ;
    USE SIGNAL ;
    PORT
      LAYER M4 ;
        RECT  0 5.34 0.192 5.364 ;
    END
  END rec[15]
  PIN rec[160]
    DIRECTION OUTPUT ;
    USE SIGNAL ;
    PORT
      LAYER M4 ;
        RECT  0 36.012 0.192 36.036 ;
    END
  END rec[160]
  PIN rec[161]
    DIRECTION OUTPUT ;
    USE SIGNAL ;
    PORT
      LAYER M4 ;
        RECT  0 36.204 0.192 36.228 ;
    END
  END rec[161]
  PIN rec[162]
    DIRECTION OUTPUT ;
    USE SIGNAL ;
    PORT
      LAYER M4 ;
        RECT  0 36.444 0.192 36.468 ;
    END
  END rec[162]
  PIN rec[163]
    DIRECTION OUTPUT ;
    USE SIGNAL ;
    PORT
      LAYER M4 ;
        RECT  0 36.636 0.192 36.66 ;
    END
  END rec[163]
  PIN rec[164]
    DIRECTION OUTPUT ;
    USE SIGNAL ;
    PORT
      LAYER M4 ;
        RECT  0 36.828 0.192 36.852 ;
    END
  END rec[164]
  PIN rec[165]
    DIRECTION OUTPUT ;
    USE SIGNAL ;
    PORT
      LAYER M4 ;
        RECT  0 37.068 0.192 37.092 ;
    END
  END rec[165]
  PIN rec[166]
    DIRECTION OUTPUT ;
    USE SIGNAL ;
    PORT
      LAYER M4 ;
        RECT  0 37.26 0.192 37.284 ;
    END
  END rec[166]
  PIN rec[167]
    DIRECTION OUTPUT ;
    USE SIGNAL ;
    PORT
      LAYER M4 ;
        RECT  0 37.5 0.192 37.524 ;
    END
  END rec[167]
  PIN rec[168]
    DIRECTION OUTPUT ;
    USE SIGNAL ;
    PORT
      LAYER M4 ;
        RECT  0 37.692 0.192 37.716 ;
    END
  END rec[168]
  PIN rec[169]
    DIRECTION OUTPUT ;
    USE SIGNAL ;
    PORT
      LAYER M4 ;
        RECT  0 37.884 0.192 37.908 ;
    END
  END rec[169]
  PIN rec[16]
    DIRECTION OUTPUT ;
    USE SIGNAL ;
    PORT
      LAYER M4 ;
        RECT  0 5.532 0.192 5.556 ;
    END
  END rec[16]
  PIN rec[170]
    DIRECTION OUTPUT ;
    USE SIGNAL ;
    PORT
      LAYER M4 ;
        RECT  0 38.124 0.192 38.148 ;
    END
  END rec[170]
  PIN rec[171]
    DIRECTION OUTPUT ;
    USE SIGNAL ;
    PORT
      LAYER M4 ;
        RECT  0 38.316 0.192 38.34 ;
    END
  END rec[171]
  PIN rec[172]
    DIRECTION OUTPUT ;
    USE SIGNAL ;
    PORT
      LAYER M4 ;
        RECT  0 38.556 0.192 38.58 ;
    END
  END rec[172]
  PIN rec[173]
    DIRECTION OUTPUT ;
    USE SIGNAL ;
    PORT
      LAYER M4 ;
        RECT  0 38.748 0.192 38.772 ;
    END
  END rec[173]
  PIN rec[174]
    DIRECTION OUTPUT ;
    USE SIGNAL ;
    PORT
      LAYER M4 ;
        RECT  0 38.94 0.192 38.964 ;
    END
  END rec[174]
  PIN rec[175]
    DIRECTION OUTPUT ;
    USE SIGNAL ;
    PORT
      LAYER M4 ;
        RECT  0 39.18 0.192 39.204 ;
    END
  END rec[175]
  PIN rec[176]
    DIRECTION OUTPUT ;
    USE SIGNAL ;
    PORT
      LAYER M4 ;
        RECT  0 39.372 0.192 39.396 ;
    END
  END rec[176]
  PIN rec[177]
    DIRECTION OUTPUT ;
    USE SIGNAL ;
    PORT
      LAYER M4 ;
        RECT  0 39.612 0.192 39.636 ;
    END
  END rec[177]
  PIN rec[178]
    DIRECTION OUTPUT ;
    USE SIGNAL ;
    PORT
      LAYER M4 ;
        RECT  0 39.804 0.192 39.828 ;
    END
  END rec[178]
  PIN rec[179]
    DIRECTION OUTPUT ;
    USE SIGNAL ;
    PORT
      LAYER M4 ;
        RECT  0 39.996 0.192 40.02 ;
    END
  END rec[179]
  PIN rec[17]
    DIRECTION OUTPUT ;
    USE SIGNAL ;
    PORT
      LAYER M4 ;
        RECT  0 5.772 0.192 5.796 ;
    END
  END rec[17]
  PIN rec[180]
    DIRECTION OUTPUT ;
    USE SIGNAL ;
    PORT
      LAYER M4 ;
        RECT  0 40.236 0.192 40.26 ;
    END
  END rec[180]
  PIN rec[181]
    DIRECTION OUTPUT ;
    USE SIGNAL ;
    PORT
      LAYER M4 ;
        RECT  0 40.428 0.192 40.452 ;
    END
  END rec[181]
  PIN rec[182]
    DIRECTION OUTPUT ;
    USE SIGNAL ;
    PORT
      LAYER M4 ;
        RECT  0 40.668 0.192 40.692 ;
    END
  END rec[182]
  PIN rec[183]
    DIRECTION OUTPUT ;
    USE SIGNAL ;
    PORT
      LAYER M4 ;
        RECT  0 40.86 0.192 40.884 ;
    END
  END rec[183]
  PIN rec[184]
    DIRECTION OUTPUT ;
    USE SIGNAL ;
    PORT
      LAYER M4 ;
        RECT  0 41.052 0.192 41.076 ;
    END
  END rec[184]
  PIN rec[185]
    DIRECTION OUTPUT ;
    USE SIGNAL ;
    PORT
      LAYER M4 ;
        RECT  0 41.292 0.192 41.316 ;
    END
  END rec[185]
  PIN rec[186]
    DIRECTION OUTPUT ;
    USE SIGNAL ;
    PORT
      LAYER M4 ;
        RECT  0 41.484 0.192 41.508 ;
    END
  END rec[186]
  PIN rec[187]
    DIRECTION OUTPUT ;
    USE SIGNAL ;
    PORT
      LAYER M4 ;
        RECT  0 41.724 0.192 41.748 ;
    END
  END rec[187]
  PIN rec[188]
    DIRECTION OUTPUT ;
    USE SIGNAL ;
    PORT
      LAYER M4 ;
        RECT  0 41.916 0.192 41.94 ;
    END
  END rec[188]
  PIN rec[189]
    DIRECTION OUTPUT ;
    USE SIGNAL ;
    PORT
      LAYER M4 ;
        RECT  0 42.108 0.192 42.132 ;
    END
  END rec[189]
  PIN rec[18]
    DIRECTION OUTPUT ;
    USE SIGNAL ;
    PORT
      LAYER M4 ;
        RECT  0 5.964 0.192 5.988 ;
    END
  END rec[18]
  PIN rec[190]
    DIRECTION OUTPUT ;
    USE SIGNAL ;
    PORT
      LAYER M4 ;
        RECT  0 42.348 0.192 42.372 ;
    END
  END rec[190]
  PIN rec[191]
    DIRECTION OUTPUT ;
    USE SIGNAL ;
    PORT
      LAYER M4 ;
        RECT  0 42.54 0.192 42.564 ;
    END
  END rec[191]
  PIN rec[192]
    DIRECTION OUTPUT ;
    USE SIGNAL ;
    PORT
      LAYER M4 ;
        RECT  0 42.78 0.192 42.804 ;
    END
  END rec[192]
  PIN rec[193]
    DIRECTION OUTPUT ;
    USE SIGNAL ;
    PORT
      LAYER M4 ;
        RECT  0 42.972 0.192 42.996 ;
    END
  END rec[193]
  PIN rec[194]
    DIRECTION OUTPUT ;
    USE SIGNAL ;
    PORT
      LAYER M4 ;
        RECT  0 43.212 0.192 43.236 ;
    END
  END rec[194]
  PIN rec[195]
    DIRECTION OUTPUT ;
    USE SIGNAL ;
    PORT
      LAYER M4 ;
        RECT  0 43.404 0.192 43.428 ;
    END
  END rec[195]
  PIN rec[196]
    DIRECTION OUTPUT ;
    USE SIGNAL ;
    PORT
      LAYER M4 ;
        RECT  0 43.596 0.192 43.62 ;
    END
  END rec[196]
  PIN rec[197]
    DIRECTION OUTPUT ;
    USE SIGNAL ;
    PORT
      LAYER M4 ;
        RECT  0 43.836 0.192 43.86 ;
    END
  END rec[197]
  PIN rec[198]
    DIRECTION OUTPUT ;
    USE SIGNAL ;
    PORT
      LAYER M4 ;
        RECT  0 44.028 0.192 44.052 ;
    END
  END rec[198]
  PIN rec[199]
    DIRECTION OUTPUT ;
    USE SIGNAL ;
    PORT
      LAYER M4 ;
        RECT  0 44.268 0.192 44.292 ;
    END
  END rec[199]
  PIN rec[19]
    DIRECTION OUTPUT ;
    USE SIGNAL ;
    PORT
      LAYER M4 ;
        RECT  0 6.204 0.192 6.228 ;
    END
  END rec[19]
  PIN rec[1]
    DIRECTION OUTPUT ;
    USE SIGNAL ;
    PORT
      LAYER M4 ;
        RECT  0 2.364 0.192 2.388 ;
    END
  END rec[1]
  PIN rec[200]
    DIRECTION OUTPUT ;
    USE SIGNAL ;
    PORT
      LAYER M4 ;
        RECT  0 44.46 0.192 44.484 ;
    END
  END rec[200]
  PIN rec[201]
    DIRECTION OUTPUT ;
    USE SIGNAL ;
    PORT
      LAYER M4 ;
        RECT  0 44.652 0.192 44.676 ;
    END
  END rec[201]
  PIN rec[202]
    DIRECTION OUTPUT ;
    USE SIGNAL ;
    PORT
      LAYER M4 ;
        RECT  0 44.892 0.192 44.916 ;
    END
  END rec[202]
  PIN rec[203]
    DIRECTION OUTPUT ;
    USE SIGNAL ;
    PORT
      LAYER M4 ;
        RECT  0 45.084 0.192 45.108 ;
    END
  END rec[203]
  PIN rec[204]
    DIRECTION OUTPUT ;
    USE SIGNAL ;
    PORT
      LAYER M4 ;
        RECT  0 45.324 0.192 45.348 ;
    END
  END rec[204]
  PIN rec[205]
    DIRECTION OUTPUT ;
    USE SIGNAL ;
    PORT
      LAYER M4 ;
        RECT  0 45.516 0.192 45.54 ;
    END
  END rec[205]
  PIN rec[206]
    DIRECTION OUTPUT ;
    USE SIGNAL ;
    PORT
      LAYER M4 ;
        RECT  0 45.708 0.192 45.732 ;
    END
  END rec[206]
  PIN rec[207]
    DIRECTION OUTPUT ;
    USE SIGNAL ;
    PORT
      LAYER M4 ;
        RECT  0 45.948 0.192 45.972 ;
    END
  END rec[207]
  PIN rec[208]
    DIRECTION OUTPUT ;
    USE SIGNAL ;
    PORT
      LAYER M4 ;
        RECT  0 46.14 0.192 46.164 ;
    END
  END rec[208]
  PIN rec[209]
    DIRECTION OUTPUT ;
    USE SIGNAL ;
    PORT
      LAYER M4 ;
        RECT  0 46.38 0.192 46.404 ;
    END
  END rec[209]
  PIN rec[20]
    DIRECTION OUTPUT ;
    USE SIGNAL ;
    PORT
      LAYER M4 ;
        RECT  0 6.396 0.192 6.42 ;
    END
  END rec[20]
  PIN rec[210]
    DIRECTION OUTPUT ;
    USE SIGNAL ;
    PORT
      LAYER M4 ;
        RECT  0 46.572 0.192 46.596 ;
    END
  END rec[210]
  PIN rec[211]
    DIRECTION OUTPUT ;
    USE SIGNAL ;
    PORT
      LAYER M4 ;
        RECT  0 46.764 0.192 46.788 ;
    END
  END rec[211]
  PIN rec[212]
    DIRECTION OUTPUT ;
    USE SIGNAL ;
    PORT
      LAYER M4 ;
        RECT  0 47.004 0.192 47.028 ;
    END
  END rec[212]
  PIN rec[213]
    DIRECTION OUTPUT ;
    USE SIGNAL ;
    PORT
      LAYER M4 ;
        RECT  0 47.196 0.192 47.22 ;
    END
  END rec[213]
  PIN rec[214]
    DIRECTION OUTPUT ;
    USE SIGNAL ;
    PORT
      LAYER M4 ;
        RECT  0 47.436 0.192 47.46 ;
    END
  END rec[214]
  PIN rec[215]
    DIRECTION OUTPUT ;
    USE SIGNAL ;
    PORT
      LAYER M4 ;
        RECT  0 47.628 0.192 47.652 ;
    END
  END rec[215]
  PIN rec[216]
    DIRECTION OUTPUT ;
    USE SIGNAL ;
    PORT
      LAYER M4 ;
        RECT  0 47.82 0.192 47.844 ;
    END
  END rec[216]
  PIN rec[217]
    DIRECTION OUTPUT ;
    USE SIGNAL ;
    PORT
      LAYER M4 ;
        RECT  0 48.06 0.192 48.084 ;
    END
  END rec[217]
  PIN rec[218]
    DIRECTION OUTPUT ;
    USE SIGNAL ;
    PORT
      LAYER M4 ;
        RECT  0 48.252 0.192 48.276 ;
    END
  END rec[218]
  PIN rec[219]
    DIRECTION OUTPUT ;
    USE SIGNAL ;
    PORT
      LAYER M4 ;
        RECT  0 48.492 0.192 48.516 ;
    END
  END rec[219]
  PIN rec[21]
    DIRECTION OUTPUT ;
    USE SIGNAL ;
    PORT
      LAYER M4 ;
        RECT  0 6.588 0.192 6.612 ;
    END
  END rec[21]
  PIN rec[220]
    DIRECTION OUTPUT ;
    USE SIGNAL ;
    PORT
      LAYER M4 ;
        RECT  0 48.684 0.192 48.708 ;
    END
  END rec[220]
  PIN rec[22]
    DIRECTION OUTPUT ;
    USE SIGNAL ;
    PORT
      LAYER M4 ;
        RECT  0 6.828 0.192 6.852 ;
    END
  END rec[22]
  PIN rec[23]
    DIRECTION OUTPUT ;
    USE SIGNAL ;
    PORT
      LAYER M4 ;
        RECT  0 7.02 0.192 7.044 ;
    END
  END rec[23]
  PIN rec[24]
    DIRECTION OUTPUT ;
    USE SIGNAL ;
    PORT
      LAYER M4 ;
        RECT  0 7.26 0.192 7.284 ;
    END
  END rec[24]
  PIN rec[25]
    DIRECTION OUTPUT ;
    USE SIGNAL ;
    PORT
      LAYER M4 ;
        RECT  0 7.452 0.192 7.476 ;
    END
  END rec[25]
  PIN rec[26]
    DIRECTION OUTPUT ;
    USE SIGNAL ;
    PORT
      LAYER M4 ;
        RECT  0 7.692 0.192 7.716 ;
    END
  END rec[26]
  PIN rec[27]
    DIRECTION OUTPUT ;
    USE SIGNAL ;
    PORT
      LAYER M4 ;
        RECT  0 7.884 0.192 7.908 ;
    END
  END rec[27]
  PIN rec[28]
    DIRECTION OUTPUT ;
    USE SIGNAL ;
    PORT
      LAYER M4 ;
        RECT  0 8.076 0.192 8.1 ;
    END
  END rec[28]
  PIN rec[29]
    DIRECTION OUTPUT ;
    USE SIGNAL ;
    PORT
      LAYER M4 ;
        RECT  0 8.316 0.192 8.34 ;
    END
  END rec[29]
  PIN rec[2]
    DIRECTION OUTPUT ;
    USE SIGNAL ;
    PORT
      LAYER M4 ;
        RECT  0 2.604 0.192 2.628 ;
    END
  END rec[2]
  PIN rec[30]
    DIRECTION OUTPUT ;
    USE SIGNAL ;
    PORT
      LAYER M4 ;
        RECT  0 8.508 0.192 8.532 ;
    END
  END rec[30]
  PIN rec[31]
    DIRECTION OUTPUT ;
    USE SIGNAL ;
    PORT
      LAYER M4 ;
        RECT  0 8.748 0.192 8.772 ;
    END
  END rec[31]
  PIN rec[32]
    DIRECTION OUTPUT ;
    USE SIGNAL ;
    PORT
      LAYER M4 ;
        RECT  0 8.94 0.192 8.964 ;
    END
  END rec[32]
  PIN rec[33]
    DIRECTION OUTPUT ;
    USE SIGNAL ;
    PORT
      LAYER M4 ;
        RECT  0 9.132 0.192 9.156 ;
    END
  END rec[33]
  PIN rec[34]
    DIRECTION OUTPUT ;
    USE SIGNAL ;
    PORT
      LAYER M4 ;
        RECT  0 9.372 0.192 9.396 ;
    END
  END rec[34]
  PIN rec[35]
    DIRECTION OUTPUT ;
    USE SIGNAL ;
    PORT
      LAYER M4 ;
        RECT  0 9.564 0.192 9.588 ;
    END
  END rec[35]
  PIN rec[36]
    DIRECTION OUTPUT ;
    USE SIGNAL ;
    PORT
      LAYER M4 ;
        RECT  0 9.804 0.192 9.828 ;
    END
  END rec[36]
  PIN rec[37]
    DIRECTION OUTPUT ;
    USE SIGNAL ;
    PORT
      LAYER M4 ;
        RECT  0 9.996 0.192 10.02 ;
    END
  END rec[37]
  PIN rec[38]
    DIRECTION OUTPUT ;
    USE SIGNAL ;
    PORT
      LAYER M4 ;
        RECT  0 10.188 0.192 10.212 ;
    END
  END rec[38]
  PIN rec[39]
    DIRECTION OUTPUT ;
    USE SIGNAL ;
    PORT
      LAYER M4 ;
        RECT  0 10.428 0.192 10.452 ;
    END
  END rec[39]
  PIN rec[3]
    DIRECTION OUTPUT ;
    USE SIGNAL ;
    PORT
      LAYER M4 ;
        RECT  0 2.796 0.192 2.82 ;
    END
  END rec[3]
  PIN rec[40]
    DIRECTION OUTPUT ;
    USE SIGNAL ;
    PORT
      LAYER M4 ;
        RECT  0 10.62 0.192 10.644 ;
    END
  END rec[40]
  PIN rec[41]
    DIRECTION OUTPUT ;
    USE SIGNAL ;
    PORT
      LAYER M4 ;
        RECT  0 10.86 0.192 10.884 ;
    END
  END rec[41]
  PIN rec[42]
    DIRECTION OUTPUT ;
    USE SIGNAL ;
    PORT
      LAYER M4 ;
        RECT  0 11.052 0.192 11.076 ;
    END
  END rec[42]
  PIN rec[43]
    DIRECTION OUTPUT ;
    USE SIGNAL ;
    PORT
      LAYER M4 ;
        RECT  0 11.244 0.192 11.268 ;
    END
  END rec[43]
  PIN rec[44]
    DIRECTION OUTPUT ;
    USE SIGNAL ;
    PORT
      LAYER M4 ;
        RECT  0 11.484 0.192 11.508 ;
    END
  END rec[44]
  PIN rec[45]
    DIRECTION OUTPUT ;
    USE SIGNAL ;
    PORT
      LAYER M4 ;
        RECT  0 11.676 0.192 11.7 ;
    END
  END rec[45]
  PIN rec[46]
    DIRECTION OUTPUT ;
    USE SIGNAL ;
    PORT
      LAYER M4 ;
        RECT  0 11.916 0.192 11.94 ;
    END
  END rec[46]
  PIN rec[47]
    DIRECTION OUTPUT ;
    USE SIGNAL ;
    PORT
      LAYER M4 ;
        RECT  0 12.108 0.192 12.132 ;
    END
  END rec[47]
  PIN rec[48]
    DIRECTION OUTPUT ;
    USE SIGNAL ;
    PORT
      LAYER M4 ;
        RECT  0 12.3 0.192 12.324 ;
    END
  END rec[48]
  PIN rec[49]
    DIRECTION OUTPUT ;
    USE SIGNAL ;
    PORT
      LAYER M4 ;
        RECT  0 12.54 0.192 12.564 ;
    END
  END rec[49]
  PIN rec[4]
    DIRECTION OUTPUT ;
    USE SIGNAL ;
    PORT
      LAYER M4 ;
        RECT  0 3.036 0.192 3.06 ;
    END
  END rec[4]
  PIN rec[50]
    DIRECTION OUTPUT ;
    USE SIGNAL ;
    PORT
      LAYER M4 ;
        RECT  0 12.732 0.192 12.756 ;
    END
  END rec[50]
  PIN rec[51]
    DIRECTION OUTPUT ;
    USE SIGNAL ;
    PORT
      LAYER M4 ;
        RECT  0 12.972 0.192 12.996 ;
    END
  END rec[51]
  PIN rec[52]
    DIRECTION OUTPUT ;
    USE SIGNAL ;
    PORT
      LAYER M4 ;
        RECT  0 13.164 0.192 13.188 ;
    END
  END rec[52]
  PIN rec[53]
    DIRECTION OUTPUT ;
    USE SIGNAL ;
    PORT
      LAYER M4 ;
        RECT  0 13.356 0.192 13.38 ;
    END
  END rec[53]
  PIN rec[54]
    DIRECTION OUTPUT ;
    USE SIGNAL ;
    PORT
      LAYER M4 ;
        RECT  0 13.596 0.192 13.62 ;
    END
  END rec[54]
  PIN rec[55]
    DIRECTION OUTPUT ;
    USE SIGNAL ;
    PORT
      LAYER M4 ;
        RECT  0 13.788 0.192 13.812 ;
    END
  END rec[55]
  PIN rec[56]
    DIRECTION OUTPUT ;
    USE SIGNAL ;
    PORT
      LAYER M4 ;
        RECT  0 14.028 0.192 14.052 ;
    END
  END rec[56]
  PIN rec[57]
    DIRECTION OUTPUT ;
    USE SIGNAL ;
    PORT
      LAYER M4 ;
        RECT  0 14.22 0.192 14.244 ;
    END
  END rec[57]
  PIN rec[58]
    DIRECTION OUTPUT ;
    USE SIGNAL ;
    PORT
      LAYER M4 ;
        RECT  0 14.412 0.192 14.436 ;
    END
  END rec[58]
  PIN rec[59]
    DIRECTION OUTPUT ;
    USE SIGNAL ;
    PORT
      LAYER M4 ;
        RECT  0 14.652 0.192 14.676 ;
    END
  END rec[59]
  PIN rec[5]
    DIRECTION OUTPUT ;
    USE SIGNAL ;
    PORT
      LAYER M4 ;
        RECT  0 3.228 0.192 3.252 ;
    END
  END rec[5]
  PIN rec[60]
    DIRECTION OUTPUT ;
    USE SIGNAL ;
    PORT
      LAYER M4 ;
        RECT  0 14.844 0.192 14.868 ;
    END
  END rec[60]
  PIN rec[61]
    DIRECTION OUTPUT ;
    USE SIGNAL ;
    PORT
      LAYER M4 ;
        RECT  0 15.084 0.192 15.108 ;
    END
  END rec[61]
  PIN rec[62]
    DIRECTION OUTPUT ;
    USE SIGNAL ;
    PORT
      LAYER M4 ;
        RECT  0 15.276 0.192 15.3 ;
    END
  END rec[62]
  PIN rec[63]
    DIRECTION OUTPUT ;
    USE SIGNAL ;
    PORT
      LAYER M4 ;
        RECT  0 15.468 0.192 15.492 ;
    END
  END rec[63]
  PIN rec[64]
    DIRECTION OUTPUT ;
    USE SIGNAL ;
    PORT
      LAYER M4 ;
        RECT  0 15.708 0.192 15.732 ;
    END
  END rec[64]
  PIN rec[65]
    DIRECTION OUTPUT ;
    USE SIGNAL ;
    PORT
      LAYER M4 ;
        RECT  0 15.9 0.192 15.924 ;
    END
  END rec[65]
  PIN rec[66]
    DIRECTION OUTPUT ;
    USE SIGNAL ;
    PORT
      LAYER M4 ;
        RECT  0 16.14 0.192 16.164 ;
    END
  END rec[66]
  PIN rec[67]
    DIRECTION OUTPUT ;
    USE SIGNAL ;
    PORT
      LAYER M4 ;
        RECT  0 16.332 0.192 16.356 ;
    END
  END rec[67]
  PIN rec[68]
    DIRECTION OUTPUT ;
    USE SIGNAL ;
    PORT
      LAYER M4 ;
        RECT  0 16.572 0.192 16.596 ;
    END
  END rec[68]
  PIN rec[69]
    DIRECTION OUTPUT ;
    USE SIGNAL ;
    PORT
      LAYER M4 ;
        RECT  0 16.764 0.192 16.788 ;
    END
  END rec[69]
  PIN rec[6]
    DIRECTION OUTPUT ;
    USE SIGNAL ;
    PORT
      LAYER M4 ;
        RECT  0 3.42 0.192 3.444 ;
    END
  END rec[6]
  PIN rec[70]
    DIRECTION OUTPUT ;
    USE SIGNAL ;
    PORT
      LAYER M4 ;
        RECT  0 16.956 0.192 16.98 ;
    END
  END rec[70]
  PIN rec[71]
    DIRECTION OUTPUT ;
    USE SIGNAL ;
    PORT
      LAYER M4 ;
        RECT  0 17.196 0.192 17.22 ;
    END
  END rec[71]
  PIN rec[72]
    DIRECTION OUTPUT ;
    USE SIGNAL ;
    PORT
      LAYER M4 ;
        RECT  0 17.388 0.192 17.412 ;
    END
  END rec[72]
  PIN rec[73]
    DIRECTION OUTPUT ;
    USE SIGNAL ;
    PORT
      LAYER M4 ;
        RECT  0 17.628 0.192 17.652 ;
    END
  END rec[73]
  PIN rec[74]
    DIRECTION OUTPUT ;
    USE SIGNAL ;
    PORT
      LAYER M4 ;
        RECT  0 17.82 0.192 17.844 ;
    END
  END rec[74]
  PIN rec[75]
    DIRECTION OUTPUT ;
    USE SIGNAL ;
    PORT
      LAYER M4 ;
        RECT  0 18.012 0.192 18.036 ;
    END
  END rec[75]
  PIN rec[76]
    DIRECTION OUTPUT ;
    USE SIGNAL ;
    PORT
      LAYER M4 ;
        RECT  0 18.252 0.192 18.276 ;
    END
  END rec[76]
  PIN rec[77]
    DIRECTION OUTPUT ;
    USE SIGNAL ;
    PORT
      LAYER M4 ;
        RECT  0 18.444 0.192 18.468 ;
    END
  END rec[77]
  PIN rec[78]
    DIRECTION OUTPUT ;
    USE SIGNAL ;
    PORT
      LAYER M4 ;
        RECT  0 18.684 0.192 18.708 ;
    END
  END rec[78]
  PIN rec[79]
    DIRECTION OUTPUT ;
    USE SIGNAL ;
    PORT
      LAYER M4 ;
        RECT  0 18.876 0.192 18.9 ;
    END
  END rec[79]
  PIN rec[7]
    DIRECTION OUTPUT ;
    USE SIGNAL ;
    PORT
      LAYER M4 ;
        RECT  0 3.66 0.192 3.684 ;
    END
  END rec[7]
  PIN rec[80]
    DIRECTION OUTPUT ;
    USE SIGNAL ;
    PORT
      LAYER M4 ;
        RECT  0 19.068 0.192 19.092 ;
    END
  END rec[80]
  PIN rec[81]
    DIRECTION OUTPUT ;
    USE SIGNAL ;
    PORT
      LAYER M4 ;
        RECT  0 19.308 0.192 19.332 ;
    END
  END rec[81]
  PIN rec[82]
    DIRECTION OUTPUT ;
    USE SIGNAL ;
    PORT
      LAYER M4 ;
        RECT  0 19.5 0.192 19.524 ;
    END
  END rec[82]
  PIN rec[83]
    DIRECTION OUTPUT ;
    USE SIGNAL ;
    PORT
      LAYER M4 ;
        RECT  0 19.74 0.192 19.764 ;
    END
  END rec[83]
  PIN rec[84]
    DIRECTION OUTPUT ;
    USE SIGNAL ;
    PORT
      LAYER M4 ;
        RECT  0 19.932 0.192 19.956 ;
    END
  END rec[84]
  PIN rec[85]
    DIRECTION OUTPUT ;
    USE SIGNAL ;
    PORT
      LAYER M4 ;
        RECT  0 20.124 0.192 20.148 ;
    END
  END rec[85]
  PIN rec[86]
    DIRECTION OUTPUT ;
    USE SIGNAL ;
    PORT
      LAYER M4 ;
        RECT  0 20.364 0.192 20.388 ;
    END
  END rec[86]
  PIN rec[87]
    DIRECTION OUTPUT ;
    USE SIGNAL ;
    PORT
      LAYER M4 ;
        RECT  0 20.556 0.192 20.58 ;
    END
  END rec[87]
  PIN rec[88]
    DIRECTION OUTPUT ;
    USE SIGNAL ;
    PORT
      LAYER M4 ;
        RECT  0 20.796 0.192 20.82 ;
    END
  END rec[88]
  PIN rec[89]
    DIRECTION OUTPUT ;
    USE SIGNAL ;
    PORT
      LAYER M4 ;
        RECT  0 20.988 0.192 21.012 ;
    END
  END rec[89]
  PIN rec[8]
    DIRECTION OUTPUT ;
    USE SIGNAL ;
    PORT
      LAYER M4 ;
        RECT  0 3.852 0.192 3.876 ;
    END
  END rec[8]
  PIN rec[90]
    DIRECTION OUTPUT ;
    USE SIGNAL ;
    PORT
      LAYER M4 ;
        RECT  0 21.18 0.192 21.204 ;
    END
  END rec[90]
  PIN rec[91]
    DIRECTION OUTPUT ;
    USE SIGNAL ;
    PORT
      LAYER M4 ;
        RECT  0 21.42 0.192 21.444 ;
    END
  END rec[91]
  PIN rec[92]
    DIRECTION OUTPUT ;
    USE SIGNAL ;
    PORT
      LAYER M4 ;
        RECT  0 21.612 0.192 21.636 ;
    END
  END rec[92]
  PIN rec[93]
    DIRECTION OUTPUT ;
    USE SIGNAL ;
    PORT
      LAYER M4 ;
        RECT  0 21.852 0.192 21.876 ;
    END
  END rec[93]
  PIN rec[94]
    DIRECTION OUTPUT ;
    USE SIGNAL ;
    PORT
      LAYER M4 ;
        RECT  0 22.044 0.192 22.068 ;
    END
  END rec[94]
  PIN rec[95]
    DIRECTION OUTPUT ;
    USE SIGNAL ;
    PORT
      LAYER M4 ;
        RECT  0 22.236 0.192 22.26 ;
    END
  END rec[95]
  PIN rec[96]
    DIRECTION OUTPUT ;
    USE SIGNAL ;
    PORT
      LAYER M4 ;
        RECT  0 22.476 0.192 22.5 ;
    END
  END rec[96]
  PIN rec[97]
    DIRECTION OUTPUT ;
    USE SIGNAL ;
    PORT
      LAYER M4 ;
        RECT  0 22.668 0.192 22.692 ;
    END
  END rec[97]
  PIN rec[98]
    DIRECTION OUTPUT ;
    USE SIGNAL ;
    PORT
      LAYER M4 ;
        RECT  0 22.908 0.192 22.932 ;
    END
  END rec[98]
  PIN rec[99]
    DIRECTION OUTPUT ;
    USE SIGNAL ;
    PORT
      LAYER M4 ;
        RECT  0 23.1 0.192 23.124 ;
    END
  END rec[99]
  PIN rec[9]
    DIRECTION OUTPUT ;
    USE SIGNAL ;
    PORT
      LAYER M4 ;
        RECT  0 4.092 0.192 4.116 ;
    END
  END rec[9]
  PIN rst_n
    DIRECTION INPUT ;
    USE SIGNAL ;
    PORT
      LAYER M4 ;
        RECT  0 52.716 0.192 52.74 ;
    END
  END rst_n
  PIN start_v
    DIRECTION OUTPUT ;
    USE SIGNAL ;
    PORT
      LAYER M5 ;
        RECT  62.22 86.208 62.244 86.4 ;
    END
  END start_v
  PIN tgt[0]
    DIRECTION INPUT ;
    USE SIGNAL ;
    PORT
      LAYER M4 ;
        RECT  0 50.796 0.192 50.82 ;
    END
  END tgt[0]
  PIN tgt[1]
    DIRECTION INPUT ;
    USE SIGNAL ;
    PORT
      LAYER M4 ;
        RECT  0 50.988 0.192 51.012 ;
    END
  END tgt[1]
  PIN tgt[2]
    DIRECTION INPUT ;
    USE SIGNAL ;
    PORT
      LAYER M4 ;
        RECT  0 51.228 0.192 51.252 ;
    END
  END tgt[2]
  PIN tgt[3]
    DIRECTION INPUT ;
    USE SIGNAL ;
    PORT
      LAYER M4 ;
        RECT  0 51.42 0.192 51.444 ;
    END
  END tgt[3]
  PIN tgt[4]
    DIRECTION INPUT ;
    USE SIGNAL ;
    PORT
      LAYER M4 ;
        RECT  0 51.66 0.192 51.684 ;
    END
  END tgt[4]
  PIN tgt[5]
    DIRECTION INPUT ;
    USE SIGNAL ;
    PORT
      LAYER M4 ;
        RECT  0 51.852 0.192 51.876 ;
    END
  END tgt[5]
  PIN tgt[6]
    DIRECTION INPUT ;
    USE SIGNAL ;
    PORT
      LAYER M4 ;
        RECT  0 52.044 0.192 52.068 ;
    END
  END tgt[6]
  PIN tgt[7]
    DIRECTION INPUT ;
    USE SIGNAL ;
    PORT
      LAYER M4 ;
        RECT  0 52.284 0.192 52.308 ;
    END
  END tgt[7]
  PIN VSS
    DIRECTION INOUT ;
    USE GROUND ;
    PORT
      LAYER M5 ;
        RECT  79.764 4.297 79.884 82.103 ;
        RECT  75.444 4.297 75.564 82.103 ;
        RECT  71.124 4.297 71.244 82.103 ;
        RECT  66.804 4.297 66.924 82.103 ;
        RECT  62.484 4.297 62.604 82.103 ;
        RECT  58.164 4.297 58.284 82.103 ;
        RECT  53.844 4.297 53.964 82.103 ;
        RECT  49.524 4.297 49.644 82.103 ;
        RECT  45.204 4.297 45.324 82.103 ;
        RECT  40.884 4.297 41.004 82.103 ;
        RECT  36.564 4.297 36.684 82.103 ;
        RECT  32.244 4.297 32.364 82.103 ;
        RECT  27.924 4.297 28.044 82.103 ;
        RECT  23.604 4.297 23.724 82.103 ;
        RECT  19.284 4.297 19.404 82.103 ;
        RECT  14.964 4.297 15.084 82.103 ;
        RECT  10.644 4.297 10.764 82.103 ;
        RECT  6.324 4.297 6.444 82.103 ;
    END
  END VSS
  PIN VDD
    DIRECTION INOUT ;
    USE POWER ;
    PORT
      LAYER M5 ;
        RECT  79.956 4.311 80.076 82.089 ;
        RECT  75.636 4.311 75.756 82.089 ;
        RECT  71.316 4.311 71.436 82.089 ;
        RECT  66.996 4.311 67.116 82.089 ;
        RECT  62.676 4.311 62.796 82.089 ;
        RECT  58.356 4.311 58.476 82.089 ;
        RECT  54.036 4.311 54.156 82.089 ;
        RECT  49.716 4.311 49.836 82.089 ;
        RECT  45.396 4.311 45.516 82.089 ;
        RECT  41.076 4.311 41.196 82.089 ;
        RECT  36.756 4.311 36.876 82.089 ;
        RECT  32.436 4.311 32.556 82.089 ;
        RECT  28.116 4.311 28.236 82.089 ;
        RECT  23.796 4.311 23.916 82.089 ;
        RECT  19.476 4.311 19.596 82.089 ;
        RECT  15.156 4.311 15.276 82.089 ;
        RECT  10.836 4.311 10.956 82.089 ;
        RECT  6.516 4.311 6.636 82.089 ;
    END
  END VDD
  OBS
    LAYER RVTN ;
     RECT  0 0 86.4 86.4 ;
    LAYER RVTP ;
     RECT  0 0 86.4 86.4 ;
    LAYER M1 ;
     RECT  0 0 86.4 86.4 ;
    LAYER M2 ;
     RECT  0 0 86.4 86.4 ;
    LAYER M3 ;
     RECT  0 0 86.4 86.4 ;
    LAYER M4 ;
     RECT  0 0 86.4 86.4 ;
    LAYER M5 ;
     RECT  0 0 86.4 86.4 ;
  END
END ot_hbm_static_cfg_collar_idx256r
END LIBRARY
